VERSION 5.8 ;
BUSBITCHARS "[]" ;
DIVIDERCHAR "/" ;
UNITS
    DATABASE MICRONS 1000 ;
END UNITS

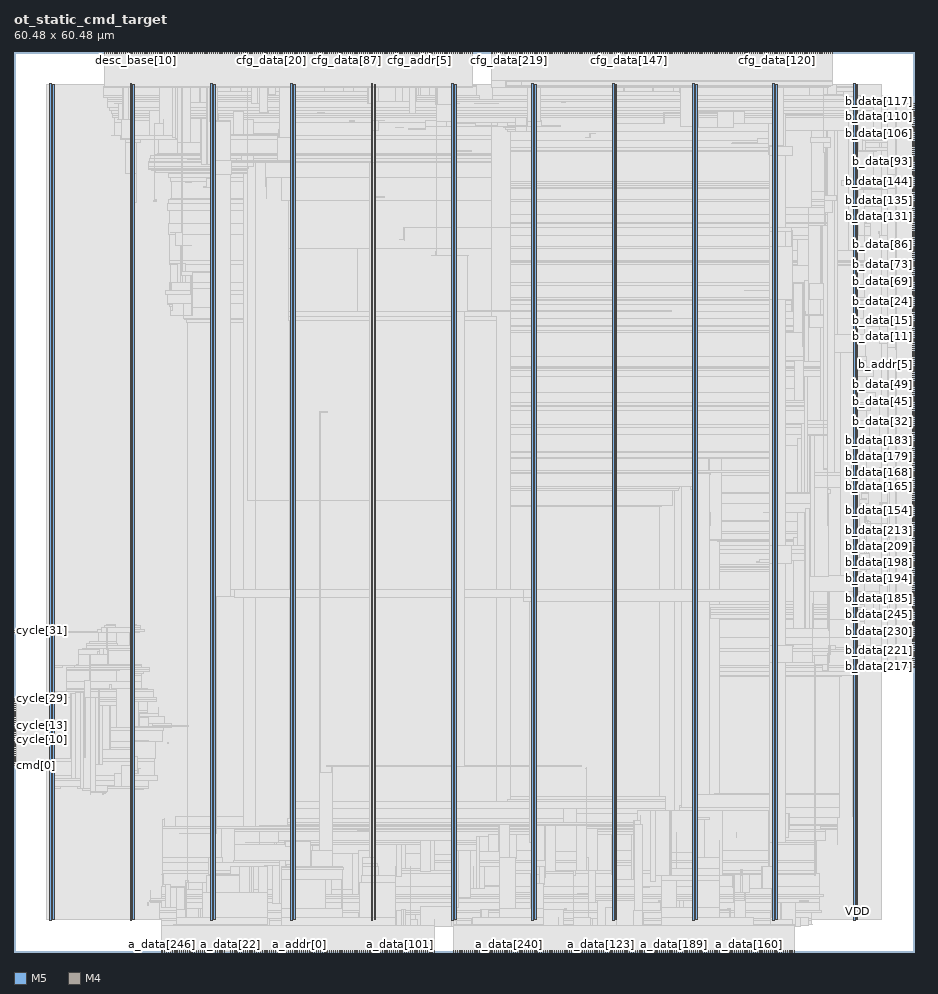
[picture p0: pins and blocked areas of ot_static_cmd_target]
MACRO ot_static_cmd_target
  FOREIGN ot_static_cmd_target 0 0 ;
  CLASS BLOCK ;
  SIZE 60.48 BY 60.48 ;
  PIN a_addr[0]
    DIRECTION OUTPUT ;
    USE SIGNAL ;
    PORT
      LAYER M5 ;
        RECT  19.152 0 19.176 0.084 ;
    END
  END a_addr[0]
  PIN a_addr[1]
    DIRECTION OUTPUT ;
    USE SIGNAL ;
    PORT
      LAYER M5 ;
        RECT  19.296 0 19.32 0.084 ;
    END
  END a_addr[1]
  PIN a_addr[2]
    DIRECTION OUTPUT ;
    USE SIGNAL ;
    PORT
      LAYER M5 ;
        RECT  19.44 0 19.464 0.084 ;
    END
  END a_addr[2]
  PIN a_addr[3]
    DIRECTION OUTPUT ;
    USE SIGNAL ;
    PORT
      LAYER M5 ;
        RECT  19.584 0 19.608 0.084 ;
    END
  END a_addr[3]
  PIN a_addr[4]
    DIRECTION OUTPUT ;
    USE SIGNAL ;
    PORT
      LAYER M5 ;
        RECT  19.728 0 19.752 0.084 ;
    END
  END a_addr[4]
  PIN a_addr[5]
    DIRECTION OUTPUT ;
    USE SIGNAL ;
    PORT
      LAYER M5 ;
        RECT  19.872 0 19.896 0.084 ;
    END
  END a_addr[5]
  PIN a_addr[6]
    DIRECTION OUTPUT ;
    USE SIGNAL ;
    PORT
      LAYER M5 ;
        RECT  20.016 0 20.04 0.084 ;
    END
  END a_addr[6]
  PIN a_addr[7]
    DIRECTION OUTPUT ;
    USE SIGNAL ;
    PORT
      LAYER M5 ;
        RECT  20.16 0 20.184 0.084 ;
    END
  END a_addr[7]
  PIN a_addr[8]
    DIRECTION OUTPUT ;
    USE SIGNAL ;
    PORT
      LAYER M5 ;
        RECT  20.304 0 20.328 0.084 ;
    END
  END a_addr[8]
  PIN a_addr[9]
    DIRECTION OUTPUT ;
    USE SIGNAL ;
    PORT
      LAYER M5 ;
        RECT  20.448 0 20.472 0.084 ;
    END
  END a_addr[9]
  PIN a_data[0]
    DIRECTION OUTPUT ;
    USE SIGNAL ;
    PORT
      LAYER M5 ;
        RECT  20.592 0 20.616 0.084 ;
    END
  END a_data[0]
  PIN a_data[100]
    DIRECTION OUTPUT ;
    USE SIGNAL ;
    PORT
      LAYER M5 ;
        RECT  25.776 0 25.8 0.084 ;
    END
  END a_data[100]
  PIN a_data[101]
    DIRECTION OUTPUT ;
    USE SIGNAL ;
    PORT
      LAYER M5 ;
        RECT  25.92 0 25.944 0.084 ;
    END
  END a_data[101]
  PIN a_data[102]
    DIRECTION OUTPUT ;
    USE SIGNAL ;
    PORT
      LAYER M5 ;
        RECT  26.064 0 26.088 0.084 ;
    END
  END a_data[102]
  PIN a_data[103]
    DIRECTION OUTPUT ;
    USE SIGNAL ;
    PORT
      LAYER M5 ;
        RECT  26.208 0 26.232 0.084 ;
    END
  END a_data[103]
  PIN a_data[104]
    DIRECTION OUTPUT ;
    USE SIGNAL ;
    PORT
      LAYER M5 ;
        RECT  26.352 0 26.376 0.084 ;
    END
  END a_data[104]
  PIN a_data[105]
    DIRECTION OUTPUT ;
    USE SIGNAL ;
    PORT
      LAYER M5 ;
        RECT  26.496 0 26.52 0.084 ;
    END
  END a_data[105]
  PIN a_data[106]
    DIRECTION OUTPUT ;
    USE SIGNAL ;
    PORT
      LAYER M5 ;
        RECT  26.64 0 26.664 0.084 ;
    END
  END a_data[106]
  PIN a_data[107]
    DIRECTION OUTPUT ;
    USE SIGNAL ;
    PORT
      LAYER M5 ;
        RECT  26.784 0 26.808 0.084 ;
    END
  END a_data[107]
  PIN a_data[108]
    DIRECTION OUTPUT ;
    USE SIGNAL ;
    PORT
      LAYER M5 ;
        RECT  26.928 0 26.952 0.084 ;
    END
  END a_data[108]
  PIN a_data[109]
    DIRECTION OUTPUT ;
    USE SIGNAL ;
    PORT
      LAYER M5 ;
        RECT  27.072 0 27.096 0.084 ;
    END
  END a_data[109]
  PIN a_data[10]
    DIRECTION OUTPUT ;
    USE SIGNAL ;
    PORT
      LAYER M5 ;
        RECT  22.032 0 22.056 0.084 ;
    END
  END a_data[10]
  PIN a_data[110]
    DIRECTION OUTPUT ;
    USE SIGNAL ;
    PORT
      LAYER M5 ;
        RECT  27.216 0 27.24 0.084 ;
    END
  END a_data[110]
  PIN a_data[111]
    DIRECTION OUTPUT ;
    USE SIGNAL ;
    PORT
      LAYER M5 ;
        RECT  27.36 0 27.384 0.084 ;
    END
  END a_data[111]
  PIN a_data[112]
    DIRECTION OUTPUT ;
    USE SIGNAL ;
    PORT
      LAYER M5 ;
        RECT  27.504 0 27.528 0.084 ;
    END
  END a_data[112]
  PIN a_data[113]
    DIRECTION OUTPUT ;
    USE SIGNAL ;
    PORT
      LAYER M5 ;
        RECT  27.648 0 27.672 0.084 ;
    END
  END a_data[113]
  PIN a_data[114]
    DIRECTION OUTPUT ;
    USE SIGNAL ;
    PORT
      LAYER M5 ;
        RECT  27.792 0 27.816 0.084 ;
    END
  END a_data[114]
  PIN a_data[115]
    DIRECTION OUTPUT ;
    USE SIGNAL ;
    PORT
      LAYER M5 ;
        RECT  27.936 0 27.96 0.084 ;
    END
  END a_data[115]
  PIN a_data[116]
    DIRECTION OUTPUT ;
    USE SIGNAL ;
    PORT
      LAYER M5 ;
        RECT  28.08 0 28.104 0.084 ;
    END
  END a_data[116]
  PIN a_data[117]
    DIRECTION OUTPUT ;
    USE SIGNAL ;
    PORT
      LAYER M5 ;
        RECT  28.224 0 28.248 0.084 ;
    END
  END a_data[117]
  PIN a_data[118]
    DIRECTION OUTPUT ;
    USE SIGNAL ;
    PORT
      LAYER M5 ;
        RECT  38.736 0 38.76 0.084 ;
    END
  END a_data[118]
  PIN a_data[119]
    DIRECTION OUTPUT ;
    USE SIGNAL ;
    PORT
      LAYER M5 ;
        RECT  38.88 0 38.904 0.084 ;
    END
  END a_data[119]
  PIN a_data[11]
    DIRECTION OUTPUT ;
    USE SIGNAL ;
    PORT
      LAYER M5 ;
        RECT  22.176 0 22.2 0.084 ;
    END
  END a_data[11]
  PIN a_data[120]
    DIRECTION OUTPUT ;
    USE SIGNAL ;
    PORT
      LAYER M5 ;
        RECT  39.024 0 39.048 0.084 ;
    END
  END a_data[120]
  PIN a_data[121]
    DIRECTION OUTPUT ;
    USE SIGNAL ;
    PORT
      LAYER M5 ;
        RECT  39.168 0 39.192 0.084 ;
    END
  END a_data[121]
  PIN a_data[122]
    DIRECTION OUTPUT ;
    USE SIGNAL ;
    PORT
      LAYER M5 ;
        RECT  39.312 0 39.336 0.084 ;
    END
  END a_data[122]
  PIN a_data[123]
    DIRECTION OUTPUT ;
    USE SIGNAL ;
    PORT
      LAYER M5 ;
        RECT  39.456 0 39.48 0.084 ;
    END
  END a_data[123]
  PIN a_data[124]
    DIRECTION OUTPUT ;
    USE SIGNAL ;
    PORT
      LAYER M5 ;
        RECT  39.6 0 39.624 0.084 ;
    END
  END a_data[124]
  PIN a_data[125]
    DIRECTION OUTPUT ;
    USE SIGNAL ;
    PORT
      LAYER M5 ;
        RECT  39.744 0 39.768 0.084 ;
    END
  END a_data[125]
  PIN a_data[126]
    DIRECTION OUTPUT ;
    USE SIGNAL ;
    PORT
      LAYER M5 ;
        RECT  39.888 0 39.912 0.084 ;
    END
  END a_data[126]
  PIN a_data[127]
    DIRECTION OUTPUT ;
    USE SIGNAL ;
    PORT
      LAYER M5 ;
        RECT  40.032 0 40.056 0.084 ;
    END
  END a_data[127]
  PIN a_data[128]
    DIRECTION OUTPUT ;
    USE SIGNAL ;
    PORT
      LAYER M5 ;
        RECT  40.176 0 40.2 0.084 ;
    END
  END a_data[128]
  PIN a_data[129]
    DIRECTION OUTPUT ;
    USE SIGNAL ;
    PORT
      LAYER M5 ;
        RECT  40.32 0 40.344 0.084 ;
    END
  END a_data[129]
  PIN a_data[12]
    DIRECTION OUTPUT ;
    USE SIGNAL ;
    PORT
      LAYER M5 ;
        RECT  22.32 0 22.344 0.084 ;
    END
  END a_data[12]
  PIN a_data[130]
    DIRECTION OUTPUT ;
    USE SIGNAL ;
    PORT
      LAYER M5 ;
        RECT  40.464 0 40.488 0.084 ;
    END
  END a_data[130]
  PIN a_data[131]
    DIRECTION OUTPUT ;
    USE SIGNAL ;
    PORT
      LAYER M5 ;
        RECT  40.608 0 40.632 0.084 ;
    END
  END a_data[131]
  PIN a_data[132]
    DIRECTION OUTPUT ;
    USE SIGNAL ;
    PORT
      LAYER M5 ;
        RECT  40.752 0 40.776 0.084 ;
    END
  END a_data[132]
  PIN a_data[133]
    DIRECTION OUTPUT ;
    USE SIGNAL ;
    PORT
      LAYER M5 ;
        RECT  40.896 0 40.92 0.084 ;
    END
  END a_data[133]
  PIN a_data[134]
    DIRECTION OUTPUT ;
    USE SIGNAL ;
    PORT
      LAYER M5 ;
        RECT  41.04 0 41.064 0.084 ;
    END
  END a_data[134]
  PIN a_data[135]
    DIRECTION OUTPUT ;
    USE SIGNAL ;
    PORT
      LAYER M5 ;
        RECT  41.184 0 41.208 0.084 ;
    END
  END a_data[135]
  PIN a_data[136]
    DIRECTION OUTPUT ;
    USE SIGNAL ;
    PORT
      LAYER M5 ;
        RECT  41.328 0 41.352 0.084 ;
    END
  END a_data[136]
  PIN a_data[137]
    DIRECTION OUTPUT ;
    USE SIGNAL ;
    PORT
      LAYER M5 ;
        RECT  41.472 0 41.496 0.084 ;
    END
  END a_data[137]
  PIN a_data[138]
    DIRECTION OUTPUT ;
    USE SIGNAL ;
    PORT
      LAYER M5 ;
        RECT  41.616 0 41.64 0.084 ;
    END
  END a_data[138]
  PIN a_data[139]
    DIRECTION OUTPUT ;
    USE SIGNAL ;
    PORT
      LAYER M5 ;
        RECT  41.76 0 41.784 0.084 ;
    END
  END a_data[139]
  PIN a_data[13]
    DIRECTION OUTPUT ;
    USE SIGNAL ;
    PORT
      LAYER M5 ;
        RECT  22.464 0 22.488 0.084 ;
    END
  END a_data[13]
  PIN a_data[140]
    DIRECTION OUTPUT ;
    USE SIGNAL ;
    PORT
      LAYER M5 ;
        RECT  41.904 0 41.928 0.084 ;
    END
  END a_data[140]
  PIN a_data[141]
    DIRECTION OUTPUT ;
    USE SIGNAL ;
    PORT
      LAYER M5 ;
        RECT  42.048 0 42.072 0.084 ;
    END
  END a_data[141]
  PIN a_data[142]
    DIRECTION OUTPUT ;
    USE SIGNAL ;
    PORT
      LAYER M5 ;
        RECT  42.192 0 42.216 0.084 ;
    END
  END a_data[142]
  PIN a_data[143]
    DIRECTION OUTPUT ;
    USE SIGNAL ;
    PORT
      LAYER M5 ;
        RECT  42.336 0 42.36 0.084 ;
    END
  END a_data[143]
  PIN a_data[144]
    DIRECTION OUTPUT ;
    USE SIGNAL ;
    PORT
      LAYER M5 ;
        RECT  42.48 0 42.504 0.084 ;
    END
  END a_data[144]
  PIN a_data[145]
    DIRECTION OUTPUT ;
    USE SIGNAL ;
    PORT
      LAYER M5 ;
        RECT  42.624 0 42.648 0.084 ;
    END
  END a_data[145]
  PIN a_data[146]
    DIRECTION OUTPUT ;
    USE SIGNAL ;
    PORT
      LAYER M5 ;
        RECT  42.768 0 42.792 0.084 ;
    END
  END a_data[146]
  PIN a_data[147]
    DIRECTION OUTPUT ;
    USE SIGNAL ;
    PORT
      LAYER M5 ;
        RECT  42.912 0 42.936 0.084 ;
    END
  END a_data[147]
  PIN a_data[148]
    DIRECTION OUTPUT ;
    USE SIGNAL ;
    PORT
      LAYER M5 ;
        RECT  43.056 0 43.08 0.084 ;
    END
  END a_data[148]
  PIN a_data[149]
    DIRECTION OUTPUT ;
    USE SIGNAL ;
    PORT
      LAYER M5 ;
        RECT  43.2 0 43.224 0.084 ;
    END
  END a_data[149]
  PIN a_data[14]
    DIRECTION OUTPUT ;
    USE SIGNAL ;
    PORT
      LAYER M5 ;
        RECT  22.608 0 22.632 0.084 ;
    END
  END a_data[14]
  PIN a_data[150]
    DIRECTION OUTPUT ;
    USE SIGNAL ;
    PORT
      LAYER M5 ;
        RECT  47.952 0 47.976 0.084 ;
    END
  END a_data[150]
  PIN a_data[151]
    DIRECTION OUTPUT ;
    USE SIGNAL ;
    PORT
      LAYER M5 ;
        RECT  48.096 0 48.12 0.084 ;
    END
  END a_data[151]
  PIN a_data[152]
    DIRECTION OUTPUT ;
    USE SIGNAL ;
    PORT
      LAYER M5 ;
        RECT  48.24 0 48.264 0.084 ;
    END
  END a_data[152]
  PIN a_data[153]
    DIRECTION OUTPUT ;
    USE SIGNAL ;
    PORT
      LAYER M5 ;
        RECT  48.384 0 48.408 0.084 ;
    END
  END a_data[153]
  PIN a_data[154]
    DIRECTION OUTPUT ;
    USE SIGNAL ;
    PORT
      LAYER M5 ;
        RECT  48.528 0 48.552 0.084 ;
    END
  END a_data[154]
  PIN a_data[155]
    DIRECTION OUTPUT ;
    USE SIGNAL ;
    PORT
      LAYER M5 ;
        RECT  48.672 0 48.696 0.084 ;
    END
  END a_data[155]
  PIN a_data[156]
    DIRECTION OUTPUT ;
    USE SIGNAL ;
    PORT
      LAYER M5 ;
        RECT  48.816 0 48.84 0.084 ;
    END
  END a_data[156]
  PIN a_data[157]
    DIRECTION OUTPUT ;
    USE SIGNAL ;
    PORT
      LAYER M5 ;
        RECT  48.96 0 48.984 0.084 ;
    END
  END a_data[157]
  PIN a_data[158]
    DIRECTION OUTPUT ;
    USE SIGNAL ;
    PORT
      LAYER M5 ;
        RECT  49.104 0 49.128 0.084 ;
    END
  END a_data[158]
  PIN a_data[159]
    DIRECTION OUTPUT ;
    USE SIGNAL ;
    PORT
      LAYER M5 ;
        RECT  49.248 0 49.272 0.084 ;
    END
  END a_data[159]
  PIN a_data[15]
    DIRECTION OUTPUT ;
    USE SIGNAL ;
    PORT
      LAYER M5 ;
        RECT  22.752 0 22.776 0.084 ;
    END
  END a_data[15]
  PIN a_data[160]
    DIRECTION OUTPUT ;
    USE SIGNAL ;
    PORT
      LAYER M5 ;
        RECT  49.392 0 49.416 0.084 ;
    END
  END a_data[160]
  PIN a_data[161]
    DIRECTION OUTPUT ;
    USE SIGNAL ;
    PORT
      LAYER M5 ;
        RECT  49.536 0 49.56 0.084 ;
    END
  END a_data[161]
  PIN a_data[162]
    DIRECTION OUTPUT ;
    USE SIGNAL ;
    PORT
      LAYER M5 ;
        RECT  49.68 0 49.704 0.084 ;
    END
  END a_data[162]
  PIN a_data[163]
    DIRECTION OUTPUT ;
    USE SIGNAL ;
    PORT
      LAYER M5 ;
        RECT  49.824 0 49.848 0.084 ;
    END
  END a_data[163]
  PIN a_data[164]
    DIRECTION OUTPUT ;
    USE SIGNAL ;
    PORT
      LAYER M5 ;
        RECT  49.968 0 49.992 0.084 ;
    END
  END a_data[164]
  PIN a_data[165]
    DIRECTION OUTPUT ;
    USE SIGNAL ;
    PORT
      LAYER M5 ;
        RECT  50.112 0 50.136 0.084 ;
    END
  END a_data[165]
  PIN a_data[166]
    DIRECTION OUTPUT ;
    USE SIGNAL ;
    PORT
      LAYER M5 ;
        RECT  50.256 0 50.28 0.084 ;
    END
  END a_data[166]
  PIN a_data[167]
    DIRECTION OUTPUT ;
    USE SIGNAL ;
    PORT
      LAYER M5 ;
        RECT  50.4 0 50.424 0.084 ;
    END
  END a_data[167]
  PIN a_data[168]
    DIRECTION OUTPUT ;
    USE SIGNAL ;
    PORT
      LAYER M5 ;
        RECT  50.544 0 50.568 0.084 ;
    END
  END a_data[168]
  PIN a_data[169]
    DIRECTION OUTPUT ;
    USE SIGNAL ;
    PORT
      LAYER M5 ;
        RECT  50.688 0 50.712 0.084 ;
    END
  END a_data[169]
  PIN a_data[16]
    DIRECTION OUTPUT ;
    USE SIGNAL ;
    PORT
      LAYER M5 ;
        RECT  22.896 0 22.92 0.084 ;
    END
  END a_data[16]
  PIN a_data[170]
    DIRECTION OUTPUT ;
    USE SIGNAL ;
    PORT
      LAYER M5 ;
        RECT  50.832 0 50.856 0.084 ;
    END
  END a_data[170]
  PIN a_data[171]
    DIRECTION OUTPUT ;
    USE SIGNAL ;
    PORT
      LAYER M5 ;
        RECT  50.976 0 51 0.084 ;
    END
  END a_data[171]
  PIN a_data[172]
    DIRECTION OUTPUT ;
    USE SIGNAL ;
    PORT
      LAYER M5 ;
        RECT  51.12 0 51.144 0.084 ;
    END
  END a_data[172]
  PIN a_data[173]
    DIRECTION OUTPUT ;
    USE SIGNAL ;
    PORT
      LAYER M5 ;
        RECT  51.264 0 51.288 0.084 ;
    END
  END a_data[173]
  PIN a_data[174]
    DIRECTION OUTPUT ;
    USE SIGNAL ;
    PORT
      LAYER M5 ;
        RECT  51.408 0 51.432 0.084 ;
    END
  END a_data[174]
  PIN a_data[175]
    DIRECTION OUTPUT ;
    USE SIGNAL ;
    PORT
      LAYER M5 ;
        RECT  51.552 0 51.576 0.084 ;
    END
  END a_data[175]
  PIN a_data[176]
    DIRECTION OUTPUT ;
    USE SIGNAL ;
    PORT
      LAYER M5 ;
        RECT  51.696 0 51.72 0.084 ;
    END
  END a_data[176]
  PIN a_data[177]
    DIRECTION OUTPUT ;
    USE SIGNAL ;
    PORT
      LAYER M5 ;
        RECT  51.84 0 51.864 0.084 ;
    END
  END a_data[177]
  PIN a_data[178]
    DIRECTION OUTPUT ;
    USE SIGNAL ;
    PORT
      LAYER M5 ;
        RECT  51.984 0 52.008 0.084 ;
    END
  END a_data[178]
  PIN a_data[179]
    DIRECTION OUTPUT ;
    USE SIGNAL ;
    PORT
      LAYER M5 ;
        RECT  52.128 0 52.152 0.084 ;
    END
  END a_data[179]
  PIN a_data[17]
    DIRECTION OUTPUT ;
    USE SIGNAL ;
    PORT
      LAYER M5 ;
        RECT  23.04 0 23.064 0.084 ;
    END
  END a_data[17]
  PIN a_data[180]
    DIRECTION OUTPUT ;
    USE SIGNAL ;
    PORT
      LAYER M5 ;
        RECT  52.272 0 52.296 0.084 ;
    END
  END a_data[180]
  PIN a_data[181]
    DIRECTION OUTPUT ;
    USE SIGNAL ;
    PORT
      LAYER M5 ;
        RECT  52.416 0 52.44 0.084 ;
    END
  END a_data[181]
  PIN a_data[182]
    DIRECTION OUTPUT ;
    USE SIGNAL ;
    PORT
      LAYER M5 ;
        RECT  43.344 0 43.368 0.084 ;
    END
  END a_data[182]
  PIN a_data[183]
    DIRECTION OUTPUT ;
    USE SIGNAL ;
    PORT
      LAYER M5 ;
        RECT  43.488 0 43.512 0.084 ;
    END
  END a_data[183]
  PIN a_data[184]
    DIRECTION OUTPUT ;
    USE SIGNAL ;
    PORT
      LAYER M5 ;
        RECT  43.632 0 43.656 0.084 ;
    END
  END a_data[184]
  PIN a_data[185]
    DIRECTION OUTPUT ;
    USE SIGNAL ;
    PORT
      LAYER M5 ;
        RECT  43.776 0 43.8 0.084 ;
    END
  END a_data[185]
  PIN a_data[186]
    DIRECTION OUTPUT ;
    USE SIGNAL ;
    PORT
      LAYER M5 ;
        RECT  43.92 0 43.944 0.084 ;
    END
  END a_data[186]
  PIN a_data[187]
    DIRECTION OUTPUT ;
    USE SIGNAL ;
    PORT
      LAYER M5 ;
        RECT  44.064 0 44.088 0.084 ;
    END
  END a_data[187]
  PIN a_data[188]
    DIRECTION OUTPUT ;
    USE SIGNAL ;
    PORT
      LAYER M5 ;
        RECT  44.208 0 44.232 0.084 ;
    END
  END a_data[188]
  PIN a_data[189]
    DIRECTION OUTPUT ;
    USE SIGNAL ;
    PORT
      LAYER M5 ;
        RECT  44.352 0 44.376 0.084 ;
    END
  END a_data[189]
  PIN a_data[18]
    DIRECTION OUTPUT ;
    USE SIGNAL ;
    PORT
      LAYER M5 ;
        RECT  23.184 0 23.208 0.084 ;
    END
  END a_data[18]
  PIN a_data[190]
    DIRECTION OUTPUT ;
    USE SIGNAL ;
    PORT
      LAYER M5 ;
        RECT  44.496 0 44.52 0.084 ;
    END
  END a_data[190]
  PIN a_data[191]
    DIRECTION OUTPUT ;
    USE SIGNAL ;
    PORT
      LAYER M5 ;
        RECT  44.64 0 44.664 0.084 ;
    END
  END a_data[191]
  PIN a_data[192]
    DIRECTION OUTPUT ;
    USE SIGNAL ;
    PORT
      LAYER M5 ;
        RECT  44.784 0 44.808 0.084 ;
    END
  END a_data[192]
  PIN a_data[193]
    DIRECTION OUTPUT ;
    USE SIGNAL ;
    PORT
      LAYER M5 ;
        RECT  44.928 0 44.952 0.084 ;
    END
  END a_data[193]
  PIN a_data[194]
    DIRECTION OUTPUT ;
    USE SIGNAL ;
    PORT
      LAYER M5 ;
        RECT  45.072 0 45.096 0.084 ;
    END
  END a_data[194]
  PIN a_data[195]
    DIRECTION OUTPUT ;
    USE SIGNAL ;
    PORT
      LAYER M5 ;
        RECT  45.216 0 45.24 0.084 ;
    END
  END a_data[195]
  PIN a_data[196]
    DIRECTION OUTPUT ;
    USE SIGNAL ;
    PORT
      LAYER M5 ;
        RECT  45.36 0 45.384 0.084 ;
    END
  END a_data[196]
  PIN a_data[197]
    DIRECTION OUTPUT ;
    USE SIGNAL ;
    PORT
      LAYER M5 ;
        RECT  45.504 0 45.528 0.084 ;
    END
  END a_data[197]
  PIN a_data[198]
    DIRECTION OUTPUT ;
    USE SIGNAL ;
    PORT
      LAYER M5 ;
        RECT  45.648 0 45.672 0.084 ;
    END
  END a_data[198]
  PIN a_data[199]
    DIRECTION OUTPUT ;
    USE SIGNAL ;
    PORT
      LAYER M5 ;
        RECT  45.792 0 45.816 0.084 ;
    END
  END a_data[199]
  PIN a_data[19]
    DIRECTION OUTPUT ;
    USE SIGNAL ;
    PORT
      LAYER M5 ;
        RECT  23.328 0 23.352 0.084 ;
    END
  END a_data[19]
  PIN a_data[1]
    DIRECTION OUTPUT ;
    USE SIGNAL ;
    PORT
      LAYER M5 ;
        RECT  20.736 0 20.76 0.084 ;
    END
  END a_data[1]
  PIN a_data[200]
    DIRECTION OUTPUT ;
    USE SIGNAL ;
    PORT
      LAYER M5 ;
        RECT  45.936 0 45.96 0.084 ;
    END
  END a_data[200]
  PIN a_data[201]
    DIRECTION OUTPUT ;
    USE SIGNAL ;
    PORT
      LAYER M5 ;
        RECT  46.08 0 46.104 0.084 ;
    END
  END a_data[201]
  PIN a_data[202]
    DIRECTION OUTPUT ;
    USE SIGNAL ;
    PORT
      LAYER M5 ;
        RECT  46.224 0 46.248 0.084 ;
    END
  END a_data[202]
  PIN a_data[203]
    DIRECTION OUTPUT ;
    USE SIGNAL ;
    PORT
      LAYER M5 ;
        RECT  46.368 0 46.392 0.084 ;
    END
  END a_data[203]
  PIN a_data[204]
    DIRECTION OUTPUT ;
    USE SIGNAL ;
    PORT
      LAYER M5 ;
        RECT  46.512 0 46.536 0.084 ;
    END
  END a_data[204]
  PIN a_data[205]
    DIRECTION OUTPUT ;
    USE SIGNAL ;
    PORT
      LAYER M5 ;
        RECT  46.656 0 46.68 0.084 ;
    END
  END a_data[205]
  PIN a_data[206]
    DIRECTION OUTPUT ;
    USE SIGNAL ;
    PORT
      LAYER M5 ;
        RECT  46.8 0 46.824 0.084 ;
    END
  END a_data[206]
  PIN a_data[207]
    DIRECTION OUTPUT ;
    USE SIGNAL ;
    PORT
      LAYER M5 ;
        RECT  46.944 0 46.968 0.084 ;
    END
  END a_data[207]
  PIN a_data[208]
    DIRECTION OUTPUT ;
    USE SIGNAL ;
    PORT
      LAYER M5 ;
        RECT  47.088 0 47.112 0.084 ;
    END
  END a_data[208]
  PIN a_data[209]
    DIRECTION OUTPUT ;
    USE SIGNAL ;
    PORT
      LAYER M5 ;
        RECT  47.232 0 47.256 0.084 ;
    END
  END a_data[209]
  PIN a_data[20]
    DIRECTION OUTPUT ;
    USE SIGNAL ;
    PORT
      LAYER M5 ;
        RECT  23.472 0 23.496 0.084 ;
    END
  END a_data[20]
  PIN a_data[210]
    DIRECTION OUTPUT ;
    USE SIGNAL ;
    PORT
      LAYER M5 ;
        RECT  47.376 0 47.4 0.084 ;
    END
  END a_data[210]
  PIN a_data[211]
    DIRECTION OUTPUT ;
    USE SIGNAL ;
    PORT
      LAYER M5 ;
        RECT  47.52 0 47.544 0.084 ;
    END
  END a_data[211]
  PIN a_data[212]
    DIRECTION OUTPUT ;
    USE SIGNAL ;
    PORT
      LAYER M5 ;
        RECT  47.664 0 47.688 0.084 ;
    END
  END a_data[212]
  PIN a_data[213]
    DIRECTION OUTPUT ;
    USE SIGNAL ;
    PORT
      LAYER M5 ;
        RECT  47.808 0 47.832 0.084 ;
    END
  END a_data[213]
  PIN a_data[214]
    DIRECTION OUTPUT ;
    USE SIGNAL ;
    PORT
      LAYER M5 ;
        RECT  29.52 0 29.544 0.084 ;
    END
  END a_data[214]
  PIN a_data[215]
    DIRECTION OUTPUT ;
    USE SIGNAL ;
    PORT
      LAYER M5 ;
        RECT  29.664 0 29.688 0.084 ;
    END
  END a_data[215]
  PIN a_data[216]
    DIRECTION OUTPUT ;
    USE SIGNAL ;
    PORT
      LAYER M5 ;
        RECT  29.808 0 29.832 0.084 ;
    END
  END a_data[216]
  PIN a_data[217]
    DIRECTION OUTPUT ;
    USE SIGNAL ;
    PORT
      LAYER M5 ;
        RECT  29.952 0 29.976 0.084 ;
    END
  END a_data[217]
  PIN a_data[218]
    DIRECTION OUTPUT ;
    USE SIGNAL ;
    PORT
      LAYER M5 ;
        RECT  30.096 0 30.12 0.084 ;
    END
  END a_data[218]
  PIN a_data[219]
    DIRECTION OUTPUT ;
    USE SIGNAL ;
    PORT
      LAYER M5 ;
        RECT  30.24 0 30.264 0.084 ;
    END
  END a_data[219]
  PIN a_data[21]
    DIRECTION OUTPUT ;
    USE SIGNAL ;
    PORT
      LAYER M5 ;
        RECT  23.616 0 23.64 0.084 ;
    END
  END a_data[21]
  PIN a_data[220]
    DIRECTION OUTPUT ;
    USE SIGNAL ;
    PORT
      LAYER M5 ;
        RECT  30.384 0 30.408 0.084 ;
    END
  END a_data[220]
  PIN a_data[221]
    DIRECTION OUTPUT ;
    USE SIGNAL ;
    PORT
      LAYER M5 ;
        RECT  30.528 0 30.552 0.084 ;
    END
  END a_data[221]
  PIN a_data[222]
    DIRECTION OUTPUT ;
    USE SIGNAL ;
    PORT
      LAYER M5 ;
        RECT  30.672 0 30.696 0.084 ;
    END
  END a_data[222]
  PIN a_data[223]
    DIRECTION OUTPUT ;
    USE SIGNAL ;
    PORT
      LAYER M5 ;
        RECT  30.816 0 30.84 0.084 ;
    END
  END a_data[223]
  PIN a_data[224]
    DIRECTION OUTPUT ;
    USE SIGNAL ;
    PORT
      LAYER M5 ;
        RECT  30.96 0 30.984 0.084 ;
    END
  END a_data[224]
  PIN a_data[225]
    DIRECTION OUTPUT ;
    USE SIGNAL ;
    PORT
      LAYER M5 ;
        RECT  31.104 0 31.128 0.084 ;
    END
  END a_data[225]
  PIN a_data[226]
    DIRECTION OUTPUT ;
    USE SIGNAL ;
    PORT
      LAYER M5 ;
        RECT  31.248 0 31.272 0.084 ;
    END
  END a_data[226]
  PIN a_data[227]
    DIRECTION OUTPUT ;
    USE SIGNAL ;
    PORT
      LAYER M5 ;
        RECT  31.392 0 31.416 0.084 ;
    END
  END a_data[227]
  PIN a_data[228]
    DIRECTION OUTPUT ;
    USE SIGNAL ;
    PORT
      LAYER M5 ;
        RECT  31.536 0 31.56 0.084 ;
    END
  END a_data[228]
  PIN a_data[229]
    DIRECTION OUTPUT ;
    USE SIGNAL ;
    PORT
      LAYER M5 ;
        RECT  31.68 0 31.704 0.084 ;
    END
  END a_data[229]
  PIN a_data[22]
    DIRECTION OUTPUT ;
    USE SIGNAL ;
    PORT
      LAYER M5 ;
        RECT  14.544 0 14.568 0.084 ;
    END
  END a_data[22]
  PIN a_data[230]
    DIRECTION OUTPUT ;
    USE SIGNAL ;
    PORT
      LAYER M5 ;
        RECT  31.824 0 31.848 0.084 ;
    END
  END a_data[230]
  PIN a_data[231]
    DIRECTION OUTPUT ;
    USE SIGNAL ;
    PORT
      LAYER M5 ;
        RECT  31.968 0 31.992 0.084 ;
    END
  END a_data[231]
  PIN a_data[232]
    DIRECTION OUTPUT ;
    USE SIGNAL ;
    PORT
      LAYER M5 ;
        RECT  32.112 0 32.136 0.084 ;
    END
  END a_data[232]
  PIN a_data[233]
    DIRECTION OUTPUT ;
    USE SIGNAL ;
    PORT
      LAYER M5 ;
        RECT  32.256 0 32.28 0.084 ;
    END
  END a_data[233]
  PIN a_data[234]
    DIRECTION OUTPUT ;
    USE SIGNAL ;
    PORT
      LAYER M5 ;
        RECT  32.4 0 32.424 0.084 ;
    END
  END a_data[234]
  PIN a_data[235]
    DIRECTION OUTPUT ;
    USE SIGNAL ;
    PORT
      LAYER M5 ;
        RECT  32.544 0 32.568 0.084 ;
    END
  END a_data[235]
  PIN a_data[236]
    DIRECTION OUTPUT ;
    USE SIGNAL ;
    PORT
      LAYER M5 ;
        RECT  32.688 0 32.712 0.084 ;
    END
  END a_data[236]
  PIN a_data[237]
    DIRECTION OUTPUT ;
    USE SIGNAL ;
    PORT
      LAYER M5 ;
        RECT  32.832 0 32.856 0.084 ;
    END
  END a_data[237]
  PIN a_data[238]
    DIRECTION OUTPUT ;
    USE SIGNAL ;
    PORT
      LAYER M5 ;
        RECT  32.976 0 33 0.084 ;
    END
  END a_data[238]
  PIN a_data[239]
    DIRECTION OUTPUT ;
    USE SIGNAL ;
    PORT
      LAYER M5 ;
        RECT  33.12 0 33.144 0.084 ;
    END
  END a_data[239]
  PIN a_data[23]
    DIRECTION OUTPUT ;
    USE SIGNAL ;
    PORT
      LAYER M5 ;
        RECT  14.688 0 14.712 0.084 ;
    END
  END a_data[23]
  PIN a_data[240]
    DIRECTION OUTPUT ;
    USE SIGNAL ;
    PORT
      LAYER M5 ;
        RECT  33.264 0 33.288 0.084 ;
    END
  END a_data[240]
  PIN a_data[241]
    DIRECTION OUTPUT ;
    USE SIGNAL ;
    PORT
      LAYER M5 ;
        RECT  33.408 0 33.432 0.084 ;
    END
  END a_data[241]
  PIN a_data[242]
    DIRECTION OUTPUT ;
    USE SIGNAL ;
    PORT
      LAYER M5 ;
        RECT  33.552 0 33.576 0.084 ;
    END
  END a_data[242]
  PIN a_data[243]
    DIRECTION OUTPUT ;
    USE SIGNAL ;
    PORT
      LAYER M5 ;
        RECT  33.696 0 33.72 0.084 ;
    END
  END a_data[243]
  PIN a_data[244]
    DIRECTION OUTPUT ;
    USE SIGNAL ;
    PORT
      LAYER M5 ;
        RECT  33.84 0 33.864 0.084 ;
    END
  END a_data[244]
  PIN a_data[245]
    DIRECTION OUTPUT ;
    USE SIGNAL ;
    PORT
      LAYER M5 ;
        RECT  33.984 0 34.008 0.084 ;
    END
  END a_data[245]
  PIN a_data[246]
    DIRECTION OUTPUT ;
    USE SIGNAL ;
    PORT
      LAYER M5 ;
        RECT  9.936 0 9.96 0.084 ;
    END
  END a_data[246]
  PIN a_data[247]
    DIRECTION OUTPUT ;
    USE SIGNAL ;
    PORT
      LAYER M5 ;
        RECT  10.08 0 10.104 0.084 ;
    END
  END a_data[247]
  PIN a_data[248]
    DIRECTION OUTPUT ;
    USE SIGNAL ;
    PORT
      LAYER M5 ;
        RECT  10.224 0 10.248 0.084 ;
    END
  END a_data[248]
  PIN a_data[249]
    DIRECTION OUTPUT ;
    USE SIGNAL ;
    PORT
      LAYER M5 ;
        RECT  10.368 0 10.392 0.084 ;
    END
  END a_data[249]
  PIN a_data[24]
    DIRECTION OUTPUT ;
    USE SIGNAL ;
    PORT
      LAYER M5 ;
        RECT  14.832 0 14.856 0.084 ;
    END
  END a_data[24]
  PIN a_data[250]
    DIRECTION OUTPUT ;
    USE SIGNAL ;
    PORT
      LAYER M5 ;
        RECT  10.512 0 10.536 0.084 ;
    END
  END a_data[250]
  PIN a_data[251]
    DIRECTION OUTPUT ;
    USE SIGNAL ;
    PORT
      LAYER M5 ;
        RECT  10.656 0 10.68 0.084 ;
    END
  END a_data[251]
  PIN a_data[252]
    DIRECTION OUTPUT ;
    USE SIGNAL ;
    PORT
      LAYER M5 ;
        RECT  10.8 0 10.824 0.084 ;
    END
  END a_data[252]
  PIN a_data[253]
    DIRECTION OUTPUT ;
    USE SIGNAL ;
    PORT
      LAYER M5 ;
        RECT  10.944 0 10.968 0.084 ;
    END
  END a_data[253]
  PIN a_data[254]
    DIRECTION OUTPUT ;
    USE SIGNAL ;
    PORT
      LAYER M5 ;
        RECT  11.088 0 11.112 0.084 ;
    END
  END a_data[254]
  PIN a_data[255]
    DIRECTION OUTPUT ;
    USE SIGNAL ;
    PORT
      LAYER M5 ;
        RECT  11.232 0 11.256 0.084 ;
    END
  END a_data[255]
  PIN a_data[25]
    DIRECTION OUTPUT ;
    USE SIGNAL ;
    PORT
      LAYER M5 ;
        RECT  14.976 0 15 0.084 ;
    END
  END a_data[25]
  PIN a_data[26]
    DIRECTION OUTPUT ;
    USE SIGNAL ;
    PORT
      LAYER M5 ;
        RECT  15.12 0 15.144 0.084 ;
    END
  END a_data[26]
  PIN a_data[27]
    DIRECTION OUTPUT ;
    USE SIGNAL ;
    PORT
      LAYER M5 ;
        RECT  15.264 0 15.288 0.084 ;
    END
  END a_data[27]
  PIN a_data[28]
    DIRECTION OUTPUT ;
    USE SIGNAL ;
    PORT
      LAYER M5 ;
        RECT  15.408 0 15.432 0.084 ;
    END
  END a_data[28]
  PIN a_data[29]
    DIRECTION OUTPUT ;
    USE SIGNAL ;
    PORT
      LAYER M5 ;
        RECT  15.552 0 15.576 0.084 ;
    END
  END a_data[29]
  PIN a_data[2]
    DIRECTION OUTPUT ;
    USE SIGNAL ;
    PORT
      LAYER M5 ;
        RECT  20.88 0 20.904 0.084 ;
    END
  END a_data[2]
  PIN a_data[30]
    DIRECTION OUTPUT ;
    USE SIGNAL ;
    PORT
      LAYER M5 ;
        RECT  15.696 0 15.72 0.084 ;
    END
  END a_data[30]
  PIN a_data[31]
    DIRECTION OUTPUT ;
    USE SIGNAL ;
    PORT
      LAYER M5 ;
        RECT  15.84 0 15.864 0.084 ;
    END
  END a_data[31]
  PIN a_data[32]
    DIRECTION OUTPUT ;
    USE SIGNAL ;
    PORT
      LAYER M5 ;
        RECT  15.984 0 16.008 0.084 ;
    END
  END a_data[32]
  PIN a_data[33]
    DIRECTION OUTPUT ;
    USE SIGNAL ;
    PORT
      LAYER M5 ;
        RECT  16.128 0 16.152 0.084 ;
    END
  END a_data[33]
  PIN a_data[34]
    DIRECTION OUTPUT ;
    USE SIGNAL ;
    PORT
      LAYER M5 ;
        RECT  16.272 0 16.296 0.084 ;
    END
  END a_data[34]
  PIN a_data[35]
    DIRECTION OUTPUT ;
    USE SIGNAL ;
    PORT
      LAYER M5 ;
        RECT  16.416 0 16.44 0.084 ;
    END
  END a_data[35]
  PIN a_data[36]
    DIRECTION OUTPUT ;
    USE SIGNAL ;
    PORT
      LAYER M5 ;
        RECT  16.56 0 16.584 0.084 ;
    END
  END a_data[36]
  PIN a_data[37]
    DIRECTION OUTPUT ;
    USE SIGNAL ;
    PORT
      LAYER M5 ;
        RECT  16.704 0 16.728 0.084 ;
    END
  END a_data[37]
  PIN a_data[38]
    DIRECTION OUTPUT ;
    USE SIGNAL ;
    PORT
      LAYER M5 ;
        RECT  16.848 0 16.872 0.084 ;
    END
  END a_data[38]
  PIN a_data[39]
    DIRECTION OUTPUT ;
    USE SIGNAL ;
    PORT
      LAYER M5 ;
        RECT  16.992 0 17.016 0.084 ;
    END
  END a_data[39]
  PIN a_data[3]
    DIRECTION OUTPUT ;
    USE SIGNAL ;
    PORT
      LAYER M5 ;
        RECT  21.024 0 21.048 0.084 ;
    END
  END a_data[3]
  PIN a_data[40]
    DIRECTION OUTPUT ;
    USE SIGNAL ;
    PORT
      LAYER M5 ;
        RECT  17.136 0 17.16 0.084 ;
    END
  END a_data[40]
  PIN a_data[41]
    DIRECTION OUTPUT ;
    USE SIGNAL ;
    PORT
      LAYER M5 ;
        RECT  17.28 0 17.304 0.084 ;
    END
  END a_data[41]
  PIN a_data[42]
    DIRECTION OUTPUT ;
    USE SIGNAL ;
    PORT
      LAYER M5 ;
        RECT  17.424 0 17.448 0.084 ;
    END
  END a_data[42]
  PIN a_data[43]
    DIRECTION OUTPUT ;
    USE SIGNAL ;
    PORT
      LAYER M5 ;
        RECT  17.568 0 17.592 0.084 ;
    END
  END a_data[43]
  PIN a_data[44]
    DIRECTION OUTPUT ;
    USE SIGNAL ;
    PORT
      LAYER M5 ;
        RECT  17.712 0 17.736 0.084 ;
    END
  END a_data[44]
  PIN a_data[45]
    DIRECTION OUTPUT ;
    USE SIGNAL ;
    PORT
      LAYER M5 ;
        RECT  17.856 0 17.88 0.084 ;
    END
  END a_data[45]
  PIN a_data[46]
    DIRECTION OUTPUT ;
    USE SIGNAL ;
    PORT
      LAYER M5 ;
        RECT  18 0 18.024 0.084 ;
    END
  END a_data[46]
  PIN a_data[47]
    DIRECTION OUTPUT ;
    USE SIGNAL ;
    PORT
      LAYER M5 ;
        RECT  18.144 0 18.168 0.084 ;
    END
  END a_data[47]
  PIN a_data[48]
    DIRECTION OUTPUT ;
    USE SIGNAL ;
    PORT
      LAYER M5 ;
        RECT  18.288 0 18.312 0.084 ;
    END
  END a_data[48]
  PIN a_data[49]
    DIRECTION OUTPUT ;
    USE SIGNAL ;
    PORT
      LAYER M5 ;
        RECT  18.432 0 18.456 0.084 ;
    END
  END a_data[49]
  PIN a_data[4]
    DIRECTION OUTPUT ;
    USE SIGNAL ;
    PORT
      LAYER M5 ;
        RECT  21.168 0 21.192 0.084 ;
    END
  END a_data[4]
  PIN a_data[50]
    DIRECTION OUTPUT ;
    USE SIGNAL ;
    PORT
      LAYER M5 ;
        RECT  18.576 0 18.6 0.084 ;
    END
  END a_data[50]
  PIN a_data[51]
    DIRECTION OUTPUT ;
    USE SIGNAL ;
    PORT
      LAYER M5 ;
        RECT  18.72 0 18.744 0.084 ;
    END
  END a_data[51]
  PIN a_data[52]
    DIRECTION OUTPUT ;
    USE SIGNAL ;
    PORT
      LAYER M5 ;
        RECT  18.864 0 18.888 0.084 ;
    END
  END a_data[52]
  PIN a_data[53]
    DIRECTION OUTPUT ;
    USE SIGNAL ;
    PORT
      LAYER M5 ;
        RECT  19.008 0 19.032 0.084 ;
    END
  END a_data[53]
  PIN a_data[54]
    DIRECTION OUTPUT ;
    USE SIGNAL ;
    PORT
      LAYER M5 ;
        RECT  34.128 0 34.152 0.084 ;
    END
  END a_data[54]
  PIN a_data[55]
    DIRECTION OUTPUT ;
    USE SIGNAL ;
    PORT
      LAYER M5 ;
        RECT  34.272 0 34.296 0.084 ;
    END
  END a_data[55]
  PIN a_data[56]
    DIRECTION OUTPUT ;
    USE SIGNAL ;
    PORT
      LAYER M5 ;
        RECT  34.416 0 34.44 0.084 ;
    END
  END a_data[56]
  PIN a_data[57]
    DIRECTION OUTPUT ;
    USE SIGNAL ;
    PORT
      LAYER M5 ;
        RECT  34.56 0 34.584 0.084 ;
    END
  END a_data[57]
  PIN a_data[58]
    DIRECTION OUTPUT ;
    USE SIGNAL ;
    PORT
      LAYER M5 ;
        RECT  34.704 0 34.728 0.084 ;
    END
  END a_data[58]
  PIN a_data[59]
    DIRECTION OUTPUT ;
    USE SIGNAL ;
    PORT
      LAYER M5 ;
        RECT  34.848 0 34.872 0.084 ;
    END
  END a_data[59]
  PIN a_data[5]
    DIRECTION OUTPUT ;
    USE SIGNAL ;
    PORT
      LAYER M5 ;
        RECT  21.312 0 21.336 0.084 ;
    END
  END a_data[5]
  PIN a_data[60]
    DIRECTION OUTPUT ;
    USE SIGNAL ;
    PORT
      LAYER M5 ;
        RECT  34.992 0 35.016 0.084 ;
    END
  END a_data[60]
  PIN a_data[61]
    DIRECTION OUTPUT ;
    USE SIGNAL ;
    PORT
      LAYER M5 ;
        RECT  35.136 0 35.16 0.084 ;
    END
  END a_data[61]
  PIN a_data[62]
    DIRECTION OUTPUT ;
    USE SIGNAL ;
    PORT
      LAYER M5 ;
        RECT  35.28 0 35.304 0.084 ;
    END
  END a_data[62]
  PIN a_data[63]
    DIRECTION OUTPUT ;
    USE SIGNAL ;
    PORT
      LAYER M5 ;
        RECT  35.424 0 35.448 0.084 ;
    END
  END a_data[63]
  PIN a_data[64]
    DIRECTION OUTPUT ;
    USE SIGNAL ;
    PORT
      LAYER M5 ;
        RECT  35.568 0 35.592 0.084 ;
    END
  END a_data[64]
  PIN a_data[65]
    DIRECTION OUTPUT ;
    USE SIGNAL ;
    PORT
      LAYER M5 ;
        RECT  35.712 0 35.736 0.084 ;
    END
  END a_data[65]
  PIN a_data[66]
    DIRECTION OUTPUT ;
    USE SIGNAL ;
    PORT
      LAYER M5 ;
        RECT  35.856 0 35.88 0.084 ;
    END
  END a_data[66]
  PIN a_data[67]
    DIRECTION OUTPUT ;
    USE SIGNAL ;
    PORT
      LAYER M5 ;
        RECT  36 0 36.024 0.084 ;
    END
  END a_data[67]
  PIN a_data[68]
    DIRECTION OUTPUT ;
    USE SIGNAL ;
    PORT
      LAYER M5 ;
        RECT  36.144 0 36.168 0.084 ;
    END
  END a_data[68]
  PIN a_data[69]
    DIRECTION OUTPUT ;
    USE SIGNAL ;
    PORT
      LAYER M5 ;
        RECT  36.288 0 36.312 0.084 ;
    END
  END a_data[69]
  PIN a_data[6]
    DIRECTION OUTPUT ;
    USE SIGNAL ;
    PORT
      LAYER M5 ;
        RECT  21.456 0 21.48 0.084 ;
    END
  END a_data[6]
  PIN a_data[70]
    DIRECTION OUTPUT ;
    USE SIGNAL ;
    PORT
      LAYER M5 ;
        RECT  36.432 0 36.456 0.084 ;
    END
  END a_data[70]
  PIN a_data[71]
    DIRECTION OUTPUT ;
    USE SIGNAL ;
    PORT
      LAYER M5 ;
        RECT  36.576 0 36.6 0.084 ;
    END
  END a_data[71]
  PIN a_data[72]
    DIRECTION OUTPUT ;
    USE SIGNAL ;
    PORT
      LAYER M5 ;
        RECT  36.72 0 36.744 0.084 ;
    END
  END a_data[72]
  PIN a_data[73]
    DIRECTION OUTPUT ;
    USE SIGNAL ;
    PORT
      LAYER M5 ;
        RECT  36.864 0 36.888 0.084 ;
    END
  END a_data[73]
  PIN a_data[74]
    DIRECTION OUTPUT ;
    USE SIGNAL ;
    PORT
      LAYER M5 ;
        RECT  37.008 0 37.032 0.084 ;
    END
  END a_data[74]
  PIN a_data[75]
    DIRECTION OUTPUT ;
    USE SIGNAL ;
    PORT
      LAYER M5 ;
        RECT  37.152 0 37.176 0.084 ;
    END
  END a_data[75]
  PIN a_data[76]
    DIRECTION OUTPUT ;
    USE SIGNAL ;
    PORT
      LAYER M5 ;
        RECT  37.296 0 37.32 0.084 ;
    END
  END a_data[76]
  PIN a_data[77]
    DIRECTION OUTPUT ;
    USE SIGNAL ;
    PORT
      LAYER M5 ;
        RECT  37.44 0 37.464 0.084 ;
    END
  END a_data[77]
  PIN a_data[78]
    DIRECTION OUTPUT ;
    USE SIGNAL ;
    PORT
      LAYER M5 ;
        RECT  37.584 0 37.608 0.084 ;
    END
  END a_data[78]
  PIN a_data[79]
    DIRECTION OUTPUT ;
    USE SIGNAL ;
    PORT
      LAYER M5 ;
        RECT  37.728 0 37.752 0.084 ;
    END
  END a_data[79]
  PIN a_data[7]
    DIRECTION OUTPUT ;
    USE SIGNAL ;
    PORT
      LAYER M5 ;
        RECT  21.6 0 21.624 0.084 ;
    END
  END a_data[7]
  PIN a_data[80]
    DIRECTION OUTPUT ;
    USE SIGNAL ;
    PORT
      LAYER M5 ;
        RECT  37.872 0 37.896 0.084 ;
    END
  END a_data[80]
  PIN a_data[81]
    DIRECTION OUTPUT ;
    USE SIGNAL ;
    PORT
      LAYER M5 ;
        RECT  38.016 0 38.04 0.084 ;
    END
  END a_data[81]
  PIN a_data[82]
    DIRECTION OUTPUT ;
    USE SIGNAL ;
    PORT
      LAYER M5 ;
        RECT  38.16 0 38.184 0.084 ;
    END
  END a_data[82]
  PIN a_data[83]
    DIRECTION OUTPUT ;
    USE SIGNAL ;
    PORT
      LAYER M5 ;
        RECT  38.304 0 38.328 0.084 ;
    END
  END a_data[83]
  PIN a_data[84]
    DIRECTION OUTPUT ;
    USE SIGNAL ;
    PORT
      LAYER M5 ;
        RECT  38.448 0 38.472 0.084 ;
    END
  END a_data[84]
  PIN a_data[85]
    DIRECTION OUTPUT ;
    USE SIGNAL ;
    PORT
      LAYER M5 ;
        RECT  38.592 0 38.616 0.084 ;
    END
  END a_data[85]
  PIN a_data[86]
    DIRECTION OUTPUT ;
    USE SIGNAL ;
    PORT
      LAYER M5 ;
        RECT  23.76 0 23.784 0.084 ;
    END
  END a_data[86]
  PIN a_data[87]
    DIRECTION OUTPUT ;
    USE SIGNAL ;
    PORT
      LAYER M5 ;
        RECT  23.904 0 23.928 0.084 ;
    END
  END a_data[87]
  PIN a_data[88]
    DIRECTION OUTPUT ;
    USE SIGNAL ;
    PORT
      LAYER M5 ;
        RECT  24.048 0 24.072 0.084 ;
    END
  END a_data[88]
  PIN a_data[89]
    DIRECTION OUTPUT ;
    USE SIGNAL ;
    PORT
      LAYER M5 ;
        RECT  24.192 0 24.216 0.084 ;
    END
  END a_data[89]
  PIN a_data[8]
    DIRECTION OUTPUT ;
    USE SIGNAL ;
    PORT
      LAYER M5 ;
        RECT  21.744 0 21.768 0.084 ;
    END
  END a_data[8]
  PIN a_data[90]
    DIRECTION OUTPUT ;
    USE SIGNAL ;
    PORT
      LAYER M5 ;
        RECT  24.336 0 24.36 0.084 ;
    END
  END a_data[90]
  PIN a_data[91]
    DIRECTION OUTPUT ;
    USE SIGNAL ;
    PORT
      LAYER M5 ;
        RECT  24.48 0 24.504 0.084 ;
    END
  END a_data[91]
  PIN a_data[92]
    DIRECTION OUTPUT ;
    USE SIGNAL ;
    PORT
      LAYER M5 ;
        RECT  24.624 0 24.648 0.084 ;
    END
  END a_data[92]
  PIN a_data[93]
    DIRECTION OUTPUT ;
    USE SIGNAL ;
    PORT
      LAYER M5 ;
        RECT  24.768 0 24.792 0.084 ;
    END
  END a_data[93]
  PIN a_data[94]
    DIRECTION OUTPUT ;
    USE SIGNAL ;
    PORT
      LAYER M5 ;
        RECT  24.912 0 24.936 0.084 ;
    END
  END a_data[94]
  PIN a_data[95]
    DIRECTION OUTPUT ;
    USE SIGNAL ;
    PORT
      LAYER M5 ;
        RECT  25.056 0 25.08 0.084 ;
    END
  END a_data[95]
  PIN a_data[96]
    DIRECTION OUTPUT ;
    USE SIGNAL ;
    PORT
      LAYER M5 ;
        RECT  25.2 0 25.224 0.084 ;
    END
  END a_data[96]
  PIN a_data[97]
    DIRECTION OUTPUT ;
    USE SIGNAL ;
    PORT
      LAYER M5 ;
        RECT  25.344 0 25.368 0.084 ;
    END
  END a_data[97]
  PIN a_data[98]
    DIRECTION OUTPUT ;
    USE SIGNAL ;
    PORT
      LAYER M5 ;
        RECT  25.488 0 25.512 0.084 ;
    END
  END a_data[98]
  PIN a_data[99]
    DIRECTION OUTPUT ;
    USE SIGNAL ;
    PORT
      LAYER M5 ;
        RECT  25.632 0 25.656 0.084 ;
    END
  END a_data[99]
  PIN a_data[9]
    DIRECTION OUTPUT ;
    USE SIGNAL ;
    PORT
      LAYER M5 ;
        RECT  21.888 0 21.912 0.084 ;
    END
  END a_data[9]
  PIN a_we
    DIRECTION OUTPUT ;
    USE SIGNAL ;
    PORT
      LAYER M5 ;
        RECT  11.376 0 11.4 0.084 ;
    END
  END a_we
  PIN active
    DIRECTION OUTPUT ;
    USE SIGNAL ;
    PORT
      LAYER M5 ;
        RECT  26.352 60.396 26.376 60.48 ;
    END
  END active
  PIN b_addr[0]
    DIRECTION OUTPUT ;
    USE SIGNAL ;
    PORT
      LAYER M4 ;
        RECT  60.396 38.736 60.48 38.76 ;
    END
  END b_addr[0]
  PIN b_addr[1]
    DIRECTION OUTPUT ;
    USE SIGNAL ;
    PORT
      LAYER M4 ;
        RECT  60.396 38.88 60.48 38.904 ;
    END
  END b_addr[1]
  PIN b_addr[2]
    DIRECTION OUTPUT ;
    USE SIGNAL ;
    PORT
      LAYER M4 ;
        RECT  60.396 39.024 60.48 39.048 ;
    END
  END b_addr[2]
  PIN b_addr[3]
    DIRECTION OUTPUT ;
    USE SIGNAL ;
    PORT
      LAYER M4 ;
        RECT  60.396 39.168 60.48 39.192 ;
    END
  END b_addr[3]
  PIN b_addr[4]
    DIRECTION OUTPUT ;
    USE SIGNAL ;
    PORT
      LAYER M4 ;
        RECT  60.396 39.312 60.48 39.336 ;
    END
  END b_addr[4]
  PIN b_addr[5]
    DIRECTION OUTPUT ;
    USE SIGNAL ;
    PORT
      LAYER M4 ;
        RECT  60.396 39.456 60.48 39.48 ;
    END
  END b_addr[5]
  PIN b_addr[6]
    DIRECTION OUTPUT ;
    USE SIGNAL ;
    PORT
      LAYER M4 ;
        RECT  60.396 39.6 60.48 39.624 ;
    END
  END b_addr[6]
  PIN b_data[0]
    DIRECTION OUTPUT ;
    USE SIGNAL ;
    PORT
      LAYER M4 ;
        RECT  60.396 39.744 60.48 39.768 ;
    END
  END b_data[0]
  PIN b_data[100]
    DIRECTION OUTPUT ;
    USE SIGNAL ;
    PORT
      LAYER M4 ;
        RECT  60.396 54.144 60.48 54.168 ;
    END
  END b_data[100]
  PIN b_data[101]
    DIRECTION OUTPUT ;
    USE SIGNAL ;
    PORT
      LAYER M4 ;
        RECT  60.396 54.288 60.48 54.312 ;
    END
  END b_data[101]
  PIN b_data[102]
    DIRECTION OUTPUT ;
    USE SIGNAL ;
    PORT
      LAYER M4 ;
        RECT  60.396 54.432 60.48 54.456 ;
    END
  END b_data[102]
  PIN b_data[103]
    DIRECTION OUTPUT ;
    USE SIGNAL ;
    PORT
      LAYER M4 ;
        RECT  60.396 54.576 60.48 54.6 ;
    END
  END b_data[103]
  PIN b_data[104]
    DIRECTION OUTPUT ;
    USE SIGNAL ;
    PORT
      LAYER M4 ;
        RECT  60.396 54.72 60.48 54.744 ;
    END
  END b_data[104]
  PIN b_data[105]
    DIRECTION OUTPUT ;
    USE SIGNAL ;
    PORT
      LAYER M4 ;
        RECT  60.396 54.864 60.48 54.888 ;
    END
  END b_data[105]
  PIN b_data[106]
    DIRECTION OUTPUT ;
    USE SIGNAL ;
    PORT
      LAYER M4 ;
        RECT  60.396 55.008 60.48 55.032 ;
    END
  END b_data[106]
  PIN b_data[107]
    DIRECTION OUTPUT ;
    USE SIGNAL ;
    PORT
      LAYER M4 ;
        RECT  60.396 55.152 60.48 55.176 ;
    END
  END b_data[107]
  PIN b_data[108]
    DIRECTION OUTPUT ;
    USE SIGNAL ;
    PORT
      LAYER M4 ;
        RECT  60.396 55.296 60.48 55.32 ;
    END
  END b_data[108]
  PIN b_data[109]
    DIRECTION OUTPUT ;
    USE SIGNAL ;
    PORT
      LAYER M4 ;
        RECT  60.396 55.44 60.48 55.464 ;
    END
  END b_data[109]
  PIN b_data[10]
    DIRECTION OUTPUT ;
    USE SIGNAL ;
    PORT
      LAYER M4 ;
        RECT  60.396 41.184 60.48 41.208 ;
    END
  END b_data[10]
  PIN b_data[110]
    DIRECTION OUTPUT ;
    USE SIGNAL ;
    PORT
      LAYER M4 ;
        RECT  60.396 55.584 60.48 55.608 ;
    END
  END b_data[110]
  PIN b_data[111]
    DIRECTION OUTPUT ;
    USE SIGNAL ;
    PORT
      LAYER M4 ;
        RECT  60.396 55.728 60.48 55.752 ;
    END
  END b_data[111]
  PIN b_data[112]
    DIRECTION OUTPUT ;
    USE SIGNAL ;
    PORT
      LAYER M4 ;
        RECT  60.396 55.872 60.48 55.896 ;
    END
  END b_data[112]
  PIN b_data[113]
    DIRECTION OUTPUT ;
    USE SIGNAL ;
    PORT
      LAYER M4 ;
        RECT  60.396 56.016 60.48 56.04 ;
    END
  END b_data[113]
  PIN b_data[114]
    DIRECTION OUTPUT ;
    USE SIGNAL ;
    PORT
      LAYER M4 ;
        RECT  60.396 56.16 60.48 56.184 ;
    END
  END b_data[114]
  PIN b_data[115]
    DIRECTION OUTPUT ;
    USE SIGNAL ;
    PORT
      LAYER M4 ;
        RECT  60.396 56.304 60.48 56.328 ;
    END
  END b_data[115]
  PIN b_data[116]
    DIRECTION OUTPUT ;
    USE SIGNAL ;
    PORT
      LAYER M4 ;
        RECT  60.396 56.448 60.48 56.472 ;
    END
  END b_data[116]
  PIN b_data[117]
    DIRECTION OUTPUT ;
    USE SIGNAL ;
    PORT
      LAYER M4 ;
        RECT  60.396 56.592 60.48 56.616 ;
    END
  END b_data[117]
  PIN b_data[118]
    DIRECTION OUTPUT ;
    USE SIGNAL ;
    PORT
      LAYER M4 ;
        RECT  60.396 56.736 60.48 56.76 ;
    END
  END b_data[118]
  PIN b_data[119]
    DIRECTION OUTPUT ;
    USE SIGNAL ;
    PORT
      LAYER M4 ;
        RECT  60.396 56.88 60.48 56.904 ;
    END
  END b_data[119]
  PIN b_data[11]
    DIRECTION OUTPUT ;
    USE SIGNAL ;
    PORT
      LAYER M4 ;
        RECT  60.396 41.328 60.48 41.352 ;
    END
  END b_data[11]
  PIN b_data[120]
    DIRECTION OUTPUT ;
    USE SIGNAL ;
    PORT
      LAYER M4 ;
        RECT  60.396 57.024 60.48 57.048 ;
    END
  END b_data[120]
  PIN b_data[121]
    DIRECTION OUTPUT ;
    USE SIGNAL ;
    PORT
      LAYER M4 ;
        RECT  60.396 47.952 60.48 47.976 ;
    END
  END b_data[121]
  PIN b_data[122]
    DIRECTION OUTPUT ;
    USE SIGNAL ;
    PORT
      LAYER M4 ;
        RECT  60.396 48.096 60.48 48.12 ;
    END
  END b_data[122]
  PIN b_data[123]
    DIRECTION OUTPUT ;
    USE SIGNAL ;
    PORT
      LAYER M4 ;
        RECT  60.396 48.24 60.48 48.264 ;
    END
  END b_data[123]
  PIN b_data[124]
    DIRECTION OUTPUT ;
    USE SIGNAL ;
    PORT
      LAYER M4 ;
        RECT  60.396 48.384 60.48 48.408 ;
    END
  END b_data[124]
  PIN b_data[125]
    DIRECTION OUTPUT ;
    USE SIGNAL ;
    PORT
      LAYER M4 ;
        RECT  60.396 48.528 60.48 48.552 ;
    END
  END b_data[125]
  PIN b_data[126]
    DIRECTION OUTPUT ;
    USE SIGNAL ;
    PORT
      LAYER M4 ;
        RECT  60.396 48.672 60.48 48.696 ;
    END
  END b_data[126]
  PIN b_data[127]
    DIRECTION OUTPUT ;
    USE SIGNAL ;
    PORT
      LAYER M4 ;
        RECT  60.396 48.816 60.48 48.84 ;
    END
  END b_data[127]
  PIN b_data[128]
    DIRECTION OUTPUT ;
    USE SIGNAL ;
    PORT
      LAYER M4 ;
        RECT  60.396 48.96 60.48 48.984 ;
    END
  END b_data[128]
  PIN b_data[129]
    DIRECTION OUTPUT ;
    USE SIGNAL ;
    PORT
      LAYER M4 ;
        RECT  60.396 49.104 60.48 49.128 ;
    END
  END b_data[129]
  PIN b_data[12]
    DIRECTION OUTPUT ;
    USE SIGNAL ;
    PORT
      LAYER M4 ;
        RECT  60.396 41.472 60.48 41.496 ;
    END
  END b_data[12]
  PIN b_data[130]
    DIRECTION OUTPUT ;
    USE SIGNAL ;
    PORT
      LAYER M4 ;
        RECT  60.396 49.248 60.48 49.272 ;
    END
  END b_data[130]
  PIN b_data[131]
    DIRECTION OUTPUT ;
    USE SIGNAL ;
    PORT
      LAYER M4 ;
        RECT  60.396 49.392 60.48 49.416 ;
    END
  END b_data[131]
  PIN b_data[132]
    DIRECTION OUTPUT ;
    USE SIGNAL ;
    PORT
      LAYER M4 ;
        RECT  60.396 49.536 60.48 49.56 ;
    END
  END b_data[132]
  PIN b_data[133]
    DIRECTION OUTPUT ;
    USE SIGNAL ;
    PORT
      LAYER M4 ;
        RECT  60.396 49.68 60.48 49.704 ;
    END
  END b_data[133]
  PIN b_data[134]
    DIRECTION OUTPUT ;
    USE SIGNAL ;
    PORT
      LAYER M4 ;
        RECT  60.396 49.824 60.48 49.848 ;
    END
  END b_data[134]
  PIN b_data[135]
    DIRECTION OUTPUT ;
    USE SIGNAL ;
    PORT
      LAYER M4 ;
        RECT  60.396 49.968 60.48 49.992 ;
    END
  END b_data[135]
  PIN b_data[136]
    DIRECTION OUTPUT ;
    USE SIGNAL ;
    PORT
      LAYER M4 ;
        RECT  60.396 50.112 60.48 50.136 ;
    END
  END b_data[136]
  PIN b_data[137]
    DIRECTION OUTPUT ;
    USE SIGNAL ;
    PORT
      LAYER M4 ;
        RECT  60.396 50.256 60.48 50.28 ;
    END
  END b_data[137]
  PIN b_data[138]
    DIRECTION OUTPUT ;
    USE SIGNAL ;
    PORT
      LAYER M4 ;
        RECT  60.396 50.4 60.48 50.424 ;
    END
  END b_data[138]
  PIN b_data[139]
    DIRECTION OUTPUT ;
    USE SIGNAL ;
    PORT
      LAYER M4 ;
        RECT  60.396 50.544 60.48 50.568 ;
    END
  END b_data[139]
  PIN b_data[13]
    DIRECTION OUTPUT ;
    USE SIGNAL ;
    PORT
      LAYER M4 ;
        RECT  60.396 41.616 60.48 41.64 ;
    END
  END b_data[13]
  PIN b_data[140]
    DIRECTION OUTPUT ;
    USE SIGNAL ;
    PORT
      LAYER M4 ;
        RECT  60.396 50.688 60.48 50.712 ;
    END
  END b_data[140]
  PIN b_data[141]
    DIRECTION OUTPUT ;
    USE SIGNAL ;
    PORT
      LAYER M4 ;
        RECT  60.396 50.832 60.48 50.856 ;
    END
  END b_data[141]
  PIN b_data[142]
    DIRECTION OUTPUT ;
    USE SIGNAL ;
    PORT
      LAYER M4 ;
        RECT  60.396 50.976 60.48 51 ;
    END
  END b_data[142]
  PIN b_data[143]
    DIRECTION OUTPUT ;
    USE SIGNAL ;
    PORT
      LAYER M4 ;
        RECT  60.396 51.12 60.48 51.144 ;
    END
  END b_data[143]
  PIN b_data[144]
    DIRECTION OUTPUT ;
    USE SIGNAL ;
    PORT
      LAYER M4 ;
        RECT  60.396 51.264 60.48 51.288 ;
    END
  END b_data[144]
  PIN b_data[145]
    DIRECTION OUTPUT ;
    USE SIGNAL ;
    PORT
      LAYER M4 ;
        RECT  60.396 51.408 60.48 51.432 ;
    END
  END b_data[145]
  PIN b_data[146]
    DIRECTION OUTPUT ;
    USE SIGNAL ;
    PORT
      LAYER M4 ;
        RECT  60.396 51.552 60.48 51.576 ;
    END
  END b_data[146]
  PIN b_data[147]
    DIRECTION OUTPUT ;
    USE SIGNAL ;
    PORT
      LAYER M4 ;
        RECT  60.396 51.696 60.48 51.72 ;
    END
  END b_data[147]
  PIN b_data[148]
    DIRECTION OUTPUT ;
    USE SIGNAL ;
    PORT
      LAYER M4 ;
        RECT  60.396 51.84 60.48 51.864 ;
    END
  END b_data[148]
  PIN b_data[149]
    DIRECTION OUTPUT ;
    USE SIGNAL ;
    PORT
      LAYER M4 ;
        RECT  60.396 51.984 60.48 52.008 ;
    END
  END b_data[149]
  PIN b_data[14]
    DIRECTION OUTPUT ;
    USE SIGNAL ;
    PORT
      LAYER M4 ;
        RECT  60.396 41.76 60.48 41.784 ;
    END
  END b_data[14]
  PIN b_data[150]
    DIRECTION OUTPUT ;
    USE SIGNAL ;
    PORT
      LAYER M4 ;
        RECT  60.396 52.128 60.48 52.152 ;
    END
  END b_data[150]
  PIN b_data[151]
    DIRECTION OUTPUT ;
    USE SIGNAL ;
    PORT
      LAYER M4 ;
        RECT  60.396 52.272 60.48 52.296 ;
    END
  END b_data[151]
  PIN b_data[152]
    DIRECTION OUTPUT ;
    USE SIGNAL ;
    PORT
      LAYER M4 ;
        RECT  60.396 52.416 60.48 52.44 ;
    END
  END b_data[152]
  PIN b_data[153]
    DIRECTION OUTPUT ;
    USE SIGNAL ;
    PORT
      LAYER M4 ;
        RECT  60.396 29.52 60.48 29.544 ;
    END
  END b_data[153]
  PIN b_data[154]
    DIRECTION OUTPUT ;
    USE SIGNAL ;
    PORT
      LAYER M4 ;
        RECT  60.396 29.664 60.48 29.688 ;
    END
  END b_data[154]
  PIN b_data[155]
    DIRECTION OUTPUT ;
    USE SIGNAL ;
    PORT
      LAYER M4 ;
        RECT  60.396 29.808 60.48 29.832 ;
    END
  END b_data[155]
  PIN b_data[156]
    DIRECTION OUTPUT ;
    USE SIGNAL ;
    PORT
      LAYER M4 ;
        RECT  60.396 29.952 60.48 29.976 ;
    END
  END b_data[156]
  PIN b_data[157]
    DIRECTION OUTPUT ;
    USE SIGNAL ;
    PORT
      LAYER M4 ;
        RECT  60.396 30.096 60.48 30.12 ;
    END
  END b_data[157]
  PIN b_data[158]
    DIRECTION OUTPUT ;
    USE SIGNAL ;
    PORT
      LAYER M4 ;
        RECT  60.396 30.24 60.48 30.264 ;
    END
  END b_data[158]
  PIN b_data[159]
    DIRECTION OUTPUT ;
    USE SIGNAL ;
    PORT
      LAYER M4 ;
        RECT  60.396 30.384 60.48 30.408 ;
    END
  END b_data[159]
  PIN b_data[15]
    DIRECTION OUTPUT ;
    USE SIGNAL ;
    PORT
      LAYER M4 ;
        RECT  60.396 41.904 60.48 41.928 ;
    END
  END b_data[15]
  PIN b_data[160]
    DIRECTION OUTPUT ;
    USE SIGNAL ;
    PORT
      LAYER M4 ;
        RECT  60.396 30.528 60.48 30.552 ;
    END
  END b_data[160]
  PIN b_data[161]
    DIRECTION OUTPUT ;
    USE SIGNAL ;
    PORT
      LAYER M4 ;
        RECT  60.396 30.672 60.48 30.696 ;
    END
  END b_data[161]
  PIN b_data[162]
    DIRECTION OUTPUT ;
    USE SIGNAL ;
    PORT
      LAYER M4 ;
        RECT  60.396 30.816 60.48 30.84 ;
    END
  END b_data[162]
  PIN b_data[163]
    DIRECTION OUTPUT ;
    USE SIGNAL ;
    PORT
      LAYER M4 ;
        RECT  60.396 30.96 60.48 30.984 ;
    END
  END b_data[163]
  PIN b_data[164]
    DIRECTION OUTPUT ;
    USE SIGNAL ;
    PORT
      LAYER M4 ;
        RECT  60.396 31.104 60.48 31.128 ;
    END
  END b_data[164]
  PIN b_data[165]
    DIRECTION OUTPUT ;
    USE SIGNAL ;
    PORT
      LAYER M4 ;
        RECT  60.396 31.248 60.48 31.272 ;
    END
  END b_data[165]
  PIN b_data[166]
    DIRECTION OUTPUT ;
    USE SIGNAL ;
    PORT
      LAYER M4 ;
        RECT  60.396 31.392 60.48 31.416 ;
    END
  END b_data[166]
  PIN b_data[167]
    DIRECTION OUTPUT ;
    USE SIGNAL ;
    PORT
      LAYER M4 ;
        RECT  60.396 31.536 60.48 31.56 ;
    END
  END b_data[167]
  PIN b_data[168]
    DIRECTION OUTPUT ;
    USE SIGNAL ;
    PORT
      LAYER M4 ;
        RECT  60.396 31.68 60.48 31.704 ;
    END
  END b_data[168]
  PIN b_data[169]
    DIRECTION OUTPUT ;
    USE SIGNAL ;
    PORT
      LAYER M4 ;
        RECT  60.396 31.824 60.48 31.848 ;
    END
  END b_data[169]
  PIN b_data[16]
    DIRECTION OUTPUT ;
    USE SIGNAL ;
    PORT
      LAYER M4 ;
        RECT  60.396 42.048 60.48 42.072 ;
    END
  END b_data[16]
  PIN b_data[170]
    DIRECTION OUTPUT ;
    USE SIGNAL ;
    PORT
      LAYER M4 ;
        RECT  60.396 31.968 60.48 31.992 ;
    END
  END b_data[170]
  PIN b_data[171]
    DIRECTION OUTPUT ;
    USE SIGNAL ;
    PORT
      LAYER M4 ;
        RECT  60.396 32.112 60.48 32.136 ;
    END
  END b_data[171]
  PIN b_data[172]
    DIRECTION OUTPUT ;
    USE SIGNAL ;
    PORT
      LAYER M4 ;
        RECT  60.396 32.256 60.48 32.28 ;
    END
  END b_data[172]
  PIN b_data[173]
    DIRECTION OUTPUT ;
    USE SIGNAL ;
    PORT
      LAYER M4 ;
        RECT  60.396 32.4 60.48 32.424 ;
    END
  END b_data[173]
  PIN b_data[174]
    DIRECTION OUTPUT ;
    USE SIGNAL ;
    PORT
      LAYER M4 ;
        RECT  60.396 32.544 60.48 32.568 ;
    END
  END b_data[174]
  PIN b_data[175]
    DIRECTION OUTPUT ;
    USE SIGNAL ;
    PORT
      LAYER M4 ;
        RECT  60.396 32.688 60.48 32.712 ;
    END
  END b_data[175]
  PIN b_data[176]
    DIRECTION OUTPUT ;
    USE SIGNAL ;
    PORT
      LAYER M4 ;
        RECT  60.396 32.832 60.48 32.856 ;
    END
  END b_data[176]
  PIN b_data[177]
    DIRECTION OUTPUT ;
    USE SIGNAL ;
    PORT
      LAYER M4 ;
        RECT  60.396 32.976 60.48 33 ;
    END
  END b_data[177]
  PIN b_data[178]
    DIRECTION OUTPUT ;
    USE SIGNAL ;
    PORT
      LAYER M4 ;
        RECT  60.396 33.12 60.48 33.144 ;
    END
  END b_data[178]
  PIN b_data[179]
    DIRECTION OUTPUT ;
    USE SIGNAL ;
    PORT
      LAYER M4 ;
        RECT  60.396 33.264 60.48 33.288 ;
    END
  END b_data[179]
  PIN b_data[17]
    DIRECTION OUTPUT ;
    USE SIGNAL ;
    PORT
      LAYER M4 ;
        RECT  60.396 42.192 60.48 42.216 ;
    END
  END b_data[17]
  PIN b_data[180]
    DIRECTION OUTPUT ;
    USE SIGNAL ;
    PORT
      LAYER M4 ;
        RECT  60.396 33.408 60.48 33.432 ;
    END
  END b_data[180]
  PIN b_data[181]
    DIRECTION OUTPUT ;
    USE SIGNAL ;
    PORT
      LAYER M4 ;
        RECT  60.396 33.552 60.48 33.576 ;
    END
  END b_data[181]
  PIN b_data[182]
    DIRECTION OUTPUT ;
    USE SIGNAL ;
    PORT
      LAYER M4 ;
        RECT  60.396 33.696 60.48 33.72 ;
    END
  END b_data[182]
  PIN b_data[183]
    DIRECTION OUTPUT ;
    USE SIGNAL ;
    PORT
      LAYER M4 ;
        RECT  60.396 33.84 60.48 33.864 ;
    END
  END b_data[183]
  PIN b_data[184]
    DIRECTION OUTPUT ;
    USE SIGNAL ;
    PORT
      LAYER M4 ;
        RECT  60.396 33.984 60.48 34.008 ;
    END
  END b_data[184]
  PIN b_data[185]
    DIRECTION OUTPUT ;
    USE SIGNAL ;
    PORT
      LAYER M4 ;
        RECT  60.396 23.76 60.48 23.784 ;
    END
  END b_data[185]
  PIN b_data[186]
    DIRECTION OUTPUT ;
    USE SIGNAL ;
    PORT
      LAYER M4 ;
        RECT  60.396 23.904 60.48 23.928 ;
    END
  END b_data[186]
  PIN b_data[187]
    DIRECTION OUTPUT ;
    USE SIGNAL ;
    PORT
      LAYER M4 ;
        RECT  60.396 24.048 60.48 24.072 ;
    END
  END b_data[187]
  PIN b_data[188]
    DIRECTION OUTPUT ;
    USE SIGNAL ;
    PORT
      LAYER M4 ;
        RECT  60.396 24.192 60.48 24.216 ;
    END
  END b_data[188]
  PIN b_data[189]
    DIRECTION OUTPUT ;
    USE SIGNAL ;
    PORT
      LAYER M4 ;
        RECT  60.396 24.336 60.48 24.36 ;
    END
  END b_data[189]
  PIN b_data[18]
    DIRECTION OUTPUT ;
    USE SIGNAL ;
    PORT
      LAYER M4 ;
        RECT  60.396 42.336 60.48 42.36 ;
    END
  END b_data[18]
  PIN b_data[190]
    DIRECTION OUTPUT ;
    USE SIGNAL ;
    PORT
      LAYER M4 ;
        RECT  60.396 24.48 60.48 24.504 ;
    END
  END b_data[190]
  PIN b_data[191]
    DIRECTION OUTPUT ;
    USE SIGNAL ;
    PORT
      LAYER M4 ;
        RECT  60.396 24.624 60.48 24.648 ;
    END
  END b_data[191]
  PIN b_data[192]
    DIRECTION OUTPUT ;
    USE SIGNAL ;
    PORT
      LAYER M4 ;
        RECT  60.396 24.768 60.48 24.792 ;
    END
  END b_data[192]
  PIN b_data[193]
    DIRECTION OUTPUT ;
    USE SIGNAL ;
    PORT
      LAYER M4 ;
        RECT  60.396 24.912 60.48 24.936 ;
    END
  END b_data[193]
  PIN b_data[194]
    DIRECTION OUTPUT ;
    USE SIGNAL ;
    PORT
      LAYER M4 ;
        RECT  60.396 25.056 60.48 25.08 ;
    END
  END b_data[194]
  PIN b_data[195]
    DIRECTION OUTPUT ;
    USE SIGNAL ;
    PORT
      LAYER M4 ;
        RECT  60.396 25.2 60.48 25.224 ;
    END
  END b_data[195]
  PIN b_data[196]
    DIRECTION OUTPUT ;
    USE SIGNAL ;
    PORT
      LAYER M4 ;
        RECT  60.396 25.344 60.48 25.368 ;
    END
  END b_data[196]
  PIN b_data[197]
    DIRECTION OUTPUT ;
    USE SIGNAL ;
    PORT
      LAYER M4 ;
        RECT  60.396 25.488 60.48 25.512 ;
    END
  END b_data[197]
  PIN b_data[198]
    DIRECTION OUTPUT ;
    USE SIGNAL ;
    PORT
      LAYER M4 ;
        RECT  60.396 25.632 60.48 25.656 ;
    END
  END b_data[198]
  PIN b_data[199]
    DIRECTION OUTPUT ;
    USE SIGNAL ;
    PORT
      LAYER M4 ;
        RECT  60.396 25.776 60.48 25.8 ;
    END
  END b_data[199]
  PIN b_data[19]
    DIRECTION OUTPUT ;
    USE SIGNAL ;
    PORT
      LAYER M4 ;
        RECT  60.396 42.48 60.48 42.504 ;
    END
  END b_data[19]
  PIN b_data[1]
    DIRECTION OUTPUT ;
    USE SIGNAL ;
    PORT
      LAYER M4 ;
        RECT  60.396 39.888 60.48 39.912 ;
    END
  END b_data[1]
  PIN b_data[200]
    DIRECTION OUTPUT ;
    USE SIGNAL ;
    PORT
      LAYER M4 ;
        RECT  60.396 25.92 60.48 25.944 ;
    END
  END b_data[200]
  PIN b_data[201]
    DIRECTION OUTPUT ;
    USE SIGNAL ;
    PORT
      LAYER M4 ;
        RECT  60.396 26.064 60.48 26.088 ;
    END
  END b_data[201]
  PIN b_data[202]
    DIRECTION OUTPUT ;
    USE SIGNAL ;
    PORT
      LAYER M4 ;
        RECT  60.396 26.208 60.48 26.232 ;
    END
  END b_data[202]
  PIN b_data[203]
    DIRECTION OUTPUT ;
    USE SIGNAL ;
    PORT
      LAYER M4 ;
        RECT  60.396 26.352 60.48 26.376 ;
    END
  END b_data[203]
  PIN b_data[204]
    DIRECTION OUTPUT ;
    USE SIGNAL ;
    PORT
      LAYER M4 ;
        RECT  60.396 26.496 60.48 26.52 ;
    END
  END b_data[204]
  PIN b_data[205]
    DIRECTION OUTPUT ;
    USE SIGNAL ;
    PORT
      LAYER M4 ;
        RECT  60.396 26.64 60.48 26.664 ;
    END
  END b_data[205]
  PIN b_data[206]
    DIRECTION OUTPUT ;
    USE SIGNAL ;
    PORT
      LAYER M4 ;
        RECT  60.396 26.784 60.48 26.808 ;
    END
  END b_data[206]
  PIN b_data[207]
    DIRECTION OUTPUT ;
    USE SIGNAL ;
    PORT
      LAYER M4 ;
        RECT  60.396 26.928 60.48 26.952 ;
    END
  END b_data[207]
  PIN b_data[208]
    DIRECTION OUTPUT ;
    USE SIGNAL ;
    PORT
      LAYER M4 ;
        RECT  60.396 27.072 60.48 27.096 ;
    END
  END b_data[208]
  PIN b_data[209]
    DIRECTION OUTPUT ;
    USE SIGNAL ;
    PORT
      LAYER M4 ;
        RECT  60.396 27.216 60.48 27.24 ;
    END
  END b_data[209]
  PIN b_data[20]
    DIRECTION OUTPUT ;
    USE SIGNAL ;
    PORT
      LAYER M4 ;
        RECT  60.396 42.624 60.48 42.648 ;
    END
  END b_data[20]
  PIN b_data[210]
    DIRECTION OUTPUT ;
    USE SIGNAL ;
    PORT
      LAYER M4 ;
        RECT  60.396 27.36 60.48 27.384 ;
    END
  END b_data[210]
  PIN b_data[211]
    DIRECTION OUTPUT ;
    USE SIGNAL ;
    PORT
      LAYER M4 ;
        RECT  60.396 27.504 60.48 27.528 ;
    END
  END b_data[211]
  PIN b_data[212]
    DIRECTION OUTPUT ;
    USE SIGNAL ;
    PORT
      LAYER M4 ;
        RECT  60.396 27.648 60.48 27.672 ;
    END
  END b_data[212]
  PIN b_data[213]
    DIRECTION OUTPUT ;
    USE SIGNAL ;
    PORT
      LAYER M4 ;
        RECT  60.396 27.792 60.48 27.816 ;
    END
  END b_data[213]
  PIN b_data[214]
    DIRECTION OUTPUT ;
    USE SIGNAL ;
    PORT
      LAYER M4 ;
        RECT  60.396 27.936 60.48 27.96 ;
    END
  END b_data[214]
  PIN b_data[215]
    DIRECTION OUTPUT ;
    USE SIGNAL ;
    PORT
      LAYER M4 ;
        RECT  60.396 28.08 60.48 28.104 ;
    END
  END b_data[215]
  PIN b_data[216]
    DIRECTION OUTPUT ;
    USE SIGNAL ;
    PORT
      LAYER M4 ;
        RECT  60.396 28.224 60.48 28.248 ;
    END
  END b_data[216]
  PIN b_data[217]
    DIRECTION OUTPUT ;
    USE SIGNAL ;
    PORT
      LAYER M4 ;
        RECT  60.396 19.152 60.48 19.176 ;
    END
  END b_data[217]
  PIN b_data[218]
    DIRECTION OUTPUT ;
    USE SIGNAL ;
    PORT
      LAYER M4 ;
        RECT  60.396 19.296 60.48 19.32 ;
    END
  END b_data[218]
  PIN b_data[219]
    DIRECTION OUTPUT ;
    USE SIGNAL ;
    PORT
      LAYER M4 ;
        RECT  60.396 19.44 60.48 19.464 ;
    END
  END b_data[219]
  PIN b_data[21]
    DIRECTION OUTPUT ;
    USE SIGNAL ;
    PORT
      LAYER M4 ;
        RECT  60.396 42.768 60.48 42.792 ;
    END
  END b_data[21]
  PIN b_data[220]
    DIRECTION OUTPUT ;
    USE SIGNAL ;
    PORT
      LAYER M4 ;
        RECT  60.396 19.584 60.48 19.608 ;
    END
  END b_data[220]
  PIN b_data[221]
    DIRECTION OUTPUT ;
    USE SIGNAL ;
    PORT
      LAYER M4 ;
        RECT  60.396 19.728 60.48 19.752 ;
    END
  END b_data[221]
  PIN b_data[222]
    DIRECTION OUTPUT ;
    USE SIGNAL ;
    PORT
      LAYER M4 ;
        RECT  60.396 19.872 60.48 19.896 ;
    END
  END b_data[222]
  PIN b_data[223]
    DIRECTION OUTPUT ;
    USE SIGNAL ;
    PORT
      LAYER M4 ;
        RECT  60.396 20.016 60.48 20.04 ;
    END
  END b_data[223]
  PIN b_data[224]
    DIRECTION OUTPUT ;
    USE SIGNAL ;
    PORT
      LAYER M4 ;
        RECT  60.396 20.16 60.48 20.184 ;
    END
  END b_data[224]
  PIN b_data[225]
    DIRECTION OUTPUT ;
    USE SIGNAL ;
    PORT
      LAYER M4 ;
        RECT  60.396 20.304 60.48 20.328 ;
    END
  END b_data[225]
  PIN b_data[226]
    DIRECTION OUTPUT ;
    USE SIGNAL ;
    PORT
      LAYER M4 ;
        RECT  60.396 20.448 60.48 20.472 ;
    END
  END b_data[226]
  PIN b_data[227]
    DIRECTION OUTPUT ;
    USE SIGNAL ;
    PORT
      LAYER M4 ;
        RECT  60.396 20.592 60.48 20.616 ;
    END
  END b_data[227]
  PIN b_data[228]
    DIRECTION OUTPUT ;
    USE SIGNAL ;
    PORT
      LAYER M4 ;
        RECT  60.396 20.736 60.48 20.76 ;
    END
  END b_data[228]
  PIN b_data[229]
    DIRECTION OUTPUT ;
    USE SIGNAL ;
    PORT
      LAYER M4 ;
        RECT  60.396 20.88 60.48 20.904 ;
    END
  END b_data[229]
  PIN b_data[22]
    DIRECTION OUTPUT ;
    USE SIGNAL ;
    PORT
      LAYER M4 ;
        RECT  60.396 42.912 60.48 42.936 ;
    END
  END b_data[22]
  PIN b_data[230]
    DIRECTION OUTPUT ;
    USE SIGNAL ;
    PORT
      LAYER M4 ;
        RECT  60.396 21.024 60.48 21.048 ;
    END
  END b_data[230]
  PIN b_data[231]
    DIRECTION OUTPUT ;
    USE SIGNAL ;
    PORT
      LAYER M4 ;
        RECT  60.396 21.168 60.48 21.192 ;
    END
  END b_data[231]
  PIN b_data[232]
    DIRECTION OUTPUT ;
    USE SIGNAL ;
    PORT
      LAYER M4 ;
        RECT  60.396 21.312 60.48 21.336 ;
    END
  END b_data[232]
  PIN b_data[233]
    DIRECTION OUTPUT ;
    USE SIGNAL ;
    PORT
      LAYER M4 ;
        RECT  60.396 21.456 60.48 21.48 ;
    END
  END b_data[233]
  PIN b_data[234]
    DIRECTION OUTPUT ;
    USE SIGNAL ;
    PORT
      LAYER M4 ;
        RECT  60.396 21.6 60.48 21.624 ;
    END
  END b_data[234]
  PIN b_data[235]
    DIRECTION OUTPUT ;
    USE SIGNAL ;
    PORT
      LAYER M4 ;
        RECT  60.396 21.744 60.48 21.768 ;
    END
  END b_data[235]
  PIN b_data[236]
    DIRECTION OUTPUT ;
    USE SIGNAL ;
    PORT
      LAYER M4 ;
        RECT  60.396 21.888 60.48 21.912 ;
    END
  END b_data[236]
  PIN b_data[237]
    DIRECTION OUTPUT ;
    USE SIGNAL ;
    PORT
      LAYER M4 ;
        RECT  60.396 22.032 60.48 22.056 ;
    END
  END b_data[237]
  PIN b_data[238]
    DIRECTION OUTPUT ;
    USE SIGNAL ;
    PORT
      LAYER M4 ;
        RECT  60.396 22.176 60.48 22.2 ;
    END
  END b_data[238]
  PIN b_data[239]
    DIRECTION OUTPUT ;
    USE SIGNAL ;
    PORT
      LAYER M4 ;
        RECT  60.396 22.32 60.48 22.344 ;
    END
  END b_data[239]
  PIN b_data[23]
    DIRECTION OUTPUT ;
    USE SIGNAL ;
    PORT
      LAYER M4 ;
        RECT  60.396 43.056 60.48 43.08 ;
    END
  END b_data[23]
  PIN b_data[240]
    DIRECTION OUTPUT ;
    USE SIGNAL ;
    PORT
      LAYER M4 ;
        RECT  60.396 22.464 60.48 22.488 ;
    END
  END b_data[240]
  PIN b_data[241]
    DIRECTION OUTPUT ;
    USE SIGNAL ;
    PORT
      LAYER M4 ;
        RECT  60.396 22.608 60.48 22.632 ;
    END
  END b_data[241]
  PIN b_data[242]
    DIRECTION OUTPUT ;
    USE SIGNAL ;
    PORT
      LAYER M4 ;
        RECT  60.396 22.752 60.48 22.776 ;
    END
  END b_data[242]
  PIN b_data[243]
    DIRECTION OUTPUT ;
    USE SIGNAL ;
    PORT
      LAYER M4 ;
        RECT  60.396 22.896 60.48 22.92 ;
    END
  END b_data[243]
  PIN b_data[244]
    DIRECTION OUTPUT ;
    USE SIGNAL ;
    PORT
      LAYER M4 ;
        RECT  60.396 23.04 60.48 23.064 ;
    END
  END b_data[244]
  PIN b_data[245]
    DIRECTION OUTPUT ;
    USE SIGNAL ;
    PORT
      LAYER M4 ;
        RECT  60.396 23.184 60.48 23.208 ;
    END
  END b_data[245]
  PIN b_data[246]
    DIRECTION OUTPUT ;
    USE SIGNAL ;
    PORT
      LAYER M4 ;
        RECT  60.396 23.328 60.48 23.352 ;
    END
  END b_data[246]
  PIN b_data[247]
    DIRECTION OUTPUT ;
    USE SIGNAL ;
    PORT
      LAYER M4 ;
        RECT  60.396 23.472 60.48 23.496 ;
    END
  END b_data[247]
  PIN b_data[248]
    DIRECTION OUTPUT ;
    USE SIGNAL ;
    PORT
      LAYER M4 ;
        RECT  60.396 23.616 60.48 23.64 ;
    END
  END b_data[248]
  PIN b_data[249]
    DIRECTION OUTPUT ;
    USE SIGNAL ;
    PORT
      LAYER M4 ;
        RECT  60.396 28.368 60.48 28.392 ;
    END
  END b_data[249]
  PIN b_data[24]
    DIRECTION OUTPUT ;
    USE SIGNAL ;
    PORT
      LAYER M4 ;
        RECT  60.396 43.2 60.48 43.224 ;
    END
  END b_data[24]
  PIN b_data[250]
    DIRECTION OUTPUT ;
    USE SIGNAL ;
    PORT
      LAYER M4 ;
        RECT  60.396 28.512 60.48 28.536 ;
    END
  END b_data[250]
  PIN b_data[251]
    DIRECTION OUTPUT ;
    USE SIGNAL ;
    PORT
      LAYER M4 ;
        RECT  60.396 28.656 60.48 28.68 ;
    END
  END b_data[251]
  PIN b_data[252]
    DIRECTION OUTPUT ;
    USE SIGNAL ;
    PORT
      LAYER M4 ;
        RECT  60.396 28.8 60.48 28.824 ;
    END
  END b_data[252]
  PIN b_data[253]
    DIRECTION OUTPUT ;
    USE SIGNAL ;
    PORT
      LAYER M4 ;
        RECT  60.396 28.944 60.48 28.968 ;
    END
  END b_data[253]
  PIN b_data[254]
    DIRECTION OUTPUT ;
    USE SIGNAL ;
    PORT
      LAYER M4 ;
        RECT  60.396 29.088 60.48 29.112 ;
    END
  END b_data[254]
  PIN b_data[255]
    DIRECTION OUTPUT ;
    USE SIGNAL ;
    PORT
      LAYER M4 ;
        RECT  60.396 29.232 60.48 29.256 ;
    END
  END b_data[255]
  PIN b_data[25]
    DIRECTION OUTPUT ;
    USE SIGNAL ;
    PORT
      LAYER M4 ;
        RECT  60.396 34.128 60.48 34.152 ;
    END
  END b_data[25]
  PIN b_data[26]
    DIRECTION OUTPUT ;
    USE SIGNAL ;
    PORT
      LAYER M4 ;
        RECT  60.396 34.272 60.48 34.296 ;
    END
  END b_data[26]
  PIN b_data[27]
    DIRECTION OUTPUT ;
    USE SIGNAL ;
    PORT
      LAYER M4 ;
        RECT  60.396 34.416 60.48 34.44 ;
    END
  END b_data[27]
  PIN b_data[28]
    DIRECTION OUTPUT ;
    USE SIGNAL ;
    PORT
      LAYER M4 ;
        RECT  60.396 34.56 60.48 34.584 ;
    END
  END b_data[28]
  PIN b_data[29]
    DIRECTION OUTPUT ;
    USE SIGNAL ;
    PORT
      LAYER M4 ;
        RECT  60.396 34.704 60.48 34.728 ;
    END
  END b_data[29]
  PIN b_data[2]
    DIRECTION OUTPUT ;
    USE SIGNAL ;
    PORT
      LAYER M4 ;
        RECT  60.396 40.032 60.48 40.056 ;
    END
  END b_data[2]
  PIN b_data[30]
    DIRECTION OUTPUT ;
    USE SIGNAL ;
    PORT
      LAYER M4 ;
        RECT  60.396 34.848 60.48 34.872 ;
    END
  END b_data[30]
  PIN b_data[31]
    DIRECTION OUTPUT ;
    USE SIGNAL ;
    PORT
      LAYER M4 ;
        RECT  60.396 34.992 60.48 35.016 ;
    END
  END b_data[31]
  PIN b_data[32]
    DIRECTION OUTPUT ;
    USE SIGNAL ;
    PORT
      LAYER M4 ;
        RECT  60.396 35.136 60.48 35.16 ;
    END
  END b_data[32]
  PIN b_data[33]
    DIRECTION OUTPUT ;
    USE SIGNAL ;
    PORT
      LAYER M4 ;
        RECT  60.396 35.28 60.48 35.304 ;
    END
  END b_data[33]
  PIN b_data[34]
    DIRECTION OUTPUT ;
    USE SIGNAL ;
    PORT
      LAYER M4 ;
        RECT  60.396 35.424 60.48 35.448 ;
    END
  END b_data[34]
  PIN b_data[35]
    DIRECTION OUTPUT ;
    USE SIGNAL ;
    PORT
      LAYER M4 ;
        RECT  60.396 35.568 60.48 35.592 ;
    END
  END b_data[35]
  PIN b_data[36]
    DIRECTION OUTPUT ;
    USE SIGNAL ;
    PORT
      LAYER M4 ;
        RECT  60.396 35.712 60.48 35.736 ;
    END
  END b_data[36]
  PIN b_data[37]
    DIRECTION OUTPUT ;
    USE SIGNAL ;
    PORT
      LAYER M4 ;
        RECT  60.396 35.856 60.48 35.88 ;
    END
  END b_data[37]
  PIN b_data[38]
    DIRECTION OUTPUT ;
    USE SIGNAL ;
    PORT
      LAYER M4 ;
        RECT  60.396 36 60.48 36.024 ;
    END
  END b_data[38]
  PIN b_data[39]
    DIRECTION OUTPUT ;
    USE SIGNAL ;
    PORT
      LAYER M4 ;
        RECT  60.396 36.144 60.48 36.168 ;
    END
  END b_data[39]
  PIN b_data[3]
    DIRECTION OUTPUT ;
    USE SIGNAL ;
    PORT
      LAYER M4 ;
        RECT  60.396 40.176 60.48 40.2 ;
    END
  END b_data[3]
  PIN b_data[40]
    DIRECTION OUTPUT ;
    USE SIGNAL ;
    PORT
      LAYER M4 ;
        RECT  60.396 36.288 60.48 36.312 ;
    END
  END b_data[40]
  PIN b_data[41]
    DIRECTION OUTPUT ;
    USE SIGNAL ;
    PORT
      LAYER M4 ;
        RECT  60.396 36.432 60.48 36.456 ;
    END
  END b_data[41]
  PIN b_data[42]
    DIRECTION OUTPUT ;
    USE SIGNAL ;
    PORT
      LAYER M4 ;
        RECT  60.396 36.576 60.48 36.6 ;
    END
  END b_data[42]
  PIN b_data[43]
    DIRECTION OUTPUT ;
    USE SIGNAL ;
    PORT
      LAYER M4 ;
        RECT  60.396 36.72 60.48 36.744 ;
    END
  END b_data[43]
  PIN b_data[44]
    DIRECTION OUTPUT ;
    USE SIGNAL ;
    PORT
      LAYER M4 ;
        RECT  60.396 36.864 60.48 36.888 ;
    END
  END b_data[44]
  PIN b_data[45]
    DIRECTION OUTPUT ;
    USE SIGNAL ;
    PORT
      LAYER M4 ;
        RECT  60.396 37.008 60.48 37.032 ;
    END
  END b_data[45]
  PIN b_data[46]
    DIRECTION OUTPUT ;
    USE SIGNAL ;
    PORT
      LAYER M4 ;
        RECT  60.396 37.152 60.48 37.176 ;
    END
  END b_data[46]
  PIN b_data[47]
    DIRECTION OUTPUT ;
    USE SIGNAL ;
    PORT
      LAYER M4 ;
        RECT  60.396 37.296 60.48 37.32 ;
    END
  END b_data[47]
  PIN b_data[48]
    DIRECTION OUTPUT ;
    USE SIGNAL ;
    PORT
      LAYER M4 ;
        RECT  60.396 37.44 60.48 37.464 ;
    END
  END b_data[48]
  PIN b_data[49]
    DIRECTION OUTPUT ;
    USE SIGNAL ;
    PORT
      LAYER M4 ;
        RECT  60.396 37.584 60.48 37.608 ;
    END
  END b_data[49]
  PIN b_data[4]
    DIRECTION OUTPUT ;
    USE SIGNAL ;
    PORT
      LAYER M4 ;
        RECT  60.396 40.32 60.48 40.344 ;
    END
  END b_data[4]
  PIN b_data[50]
    DIRECTION OUTPUT ;
    USE SIGNAL ;
    PORT
      LAYER M4 ;
        RECT  60.396 37.728 60.48 37.752 ;
    END
  END b_data[50]
  PIN b_data[51]
    DIRECTION OUTPUT ;
    USE SIGNAL ;
    PORT
      LAYER M4 ;
        RECT  60.396 37.872 60.48 37.896 ;
    END
  END b_data[51]
  PIN b_data[52]
    DIRECTION OUTPUT ;
    USE SIGNAL ;
    PORT
      LAYER M4 ;
        RECT  60.396 38.016 60.48 38.04 ;
    END
  END b_data[52]
  PIN b_data[53]
    DIRECTION OUTPUT ;
    USE SIGNAL ;
    PORT
      LAYER M4 ;
        RECT  60.396 38.16 60.48 38.184 ;
    END
  END b_data[53]
  PIN b_data[54]
    DIRECTION OUTPUT ;
    USE SIGNAL ;
    PORT
      LAYER M4 ;
        RECT  60.396 38.304 60.48 38.328 ;
    END
  END b_data[54]
  PIN b_data[55]
    DIRECTION OUTPUT ;
    USE SIGNAL ;
    PORT
      LAYER M4 ;
        RECT  60.396 38.448 60.48 38.472 ;
    END
  END b_data[55]
  PIN b_data[56]
    DIRECTION OUTPUT ;
    USE SIGNAL ;
    PORT
      LAYER M4 ;
        RECT  60.396 38.592 60.48 38.616 ;
    END
  END b_data[56]
  PIN b_data[57]
    DIRECTION OUTPUT ;
    USE SIGNAL ;
    PORT
      LAYER M4 ;
        RECT  60.396 43.344 60.48 43.368 ;
    END
  END b_data[57]
  PIN b_data[58]
    DIRECTION OUTPUT ;
    USE SIGNAL ;
    PORT
      LAYER M4 ;
        RECT  60.396 43.488 60.48 43.512 ;
    END
  END b_data[58]
  PIN b_data[59]
    DIRECTION OUTPUT ;
    USE SIGNAL ;
    PORT
      LAYER M4 ;
        RECT  60.396 43.632 60.48 43.656 ;
    END
  END b_data[59]
  PIN b_data[5]
    DIRECTION OUTPUT ;
    USE SIGNAL ;
    PORT
      LAYER M4 ;
        RECT  60.396 40.464 60.48 40.488 ;
    END
  END b_data[5]
  PIN b_data[60]
    DIRECTION OUTPUT ;
    USE SIGNAL ;
    PORT
      LAYER M4 ;
        RECT  60.396 43.776 60.48 43.8 ;
    END
  END b_data[60]
  PIN b_data[61]
    DIRECTION OUTPUT ;
    USE SIGNAL ;
    PORT
      LAYER M4 ;
        RECT  60.396 43.92 60.48 43.944 ;
    END
  END b_data[61]
  PIN b_data[62]
    DIRECTION OUTPUT ;
    USE SIGNAL ;
    PORT
      LAYER M4 ;
        RECT  60.396 44.064 60.48 44.088 ;
    END
  END b_data[62]
  PIN b_data[63]
    DIRECTION OUTPUT ;
    USE SIGNAL ;
    PORT
      LAYER M4 ;
        RECT  60.396 44.208 60.48 44.232 ;
    END
  END b_data[63]
  PIN b_data[64]
    DIRECTION OUTPUT ;
    USE SIGNAL ;
    PORT
      LAYER M4 ;
        RECT  60.396 44.352 60.48 44.376 ;
    END
  END b_data[64]
  PIN b_data[65]
    DIRECTION OUTPUT ;
    USE SIGNAL ;
    PORT
      LAYER M4 ;
        RECT  60.396 44.496 60.48 44.52 ;
    END
  END b_data[65]
  PIN b_data[66]
    DIRECTION OUTPUT ;
    USE SIGNAL ;
    PORT
      LAYER M4 ;
        RECT  60.396 44.64 60.48 44.664 ;
    END
  END b_data[66]
  PIN b_data[67]
    DIRECTION OUTPUT ;
    USE SIGNAL ;
    PORT
      LAYER M4 ;
        RECT  60.396 44.784 60.48 44.808 ;
    END
  END b_data[67]
  PIN b_data[68]
    DIRECTION OUTPUT ;
    USE SIGNAL ;
    PORT
      LAYER M4 ;
        RECT  60.396 44.928 60.48 44.952 ;
    END
  END b_data[68]
  PIN b_data[69]
    DIRECTION OUTPUT ;
    USE SIGNAL ;
    PORT
      LAYER M4 ;
        RECT  60.396 45.072 60.48 45.096 ;
    END
  END b_data[69]
  PIN b_data[6]
    DIRECTION OUTPUT ;
    USE SIGNAL ;
    PORT
      LAYER M4 ;
        RECT  60.396 40.608 60.48 40.632 ;
    END
  END b_data[6]
  PIN b_data[70]
    DIRECTION OUTPUT ;
    USE SIGNAL ;
    PORT
      LAYER M4 ;
        RECT  60.396 45.216 60.48 45.24 ;
    END
  END b_data[70]
  PIN b_data[71]
    DIRECTION OUTPUT ;
    USE SIGNAL ;
    PORT
      LAYER M4 ;
        RECT  60.396 45.36 60.48 45.384 ;
    END
  END b_data[71]
  PIN b_data[72]
    DIRECTION OUTPUT ;
    USE SIGNAL ;
    PORT
      LAYER M4 ;
        RECT  60.396 45.504 60.48 45.528 ;
    END
  END b_data[72]
  PIN b_data[73]
    DIRECTION OUTPUT ;
    USE SIGNAL ;
    PORT
      LAYER M4 ;
        RECT  60.396 45.648 60.48 45.672 ;
    END
  END b_data[73]
  PIN b_data[74]
    DIRECTION OUTPUT ;
    USE SIGNAL ;
    PORT
      LAYER M4 ;
        RECT  60.396 45.792 60.48 45.816 ;
    END
  END b_data[74]
  PIN b_data[75]
    DIRECTION OUTPUT ;
    USE SIGNAL ;
    PORT
      LAYER M4 ;
        RECT  60.396 45.936 60.48 45.96 ;
    END
  END b_data[75]
  PIN b_data[76]
    DIRECTION OUTPUT ;
    USE SIGNAL ;
    PORT
      LAYER M4 ;
        RECT  60.396 46.08 60.48 46.104 ;
    END
  END b_data[76]
  PIN b_data[77]
    DIRECTION OUTPUT ;
    USE SIGNAL ;
    PORT
      LAYER M4 ;
        RECT  60.396 46.224 60.48 46.248 ;
    END
  END b_data[77]
  PIN b_data[78]
    DIRECTION OUTPUT ;
    USE SIGNAL ;
    PORT
      LAYER M4 ;
        RECT  60.396 46.368 60.48 46.392 ;
    END
  END b_data[78]
  PIN b_data[79]
    DIRECTION OUTPUT ;
    USE SIGNAL ;
    PORT
      LAYER M4 ;
        RECT  60.396 46.512 60.48 46.536 ;
    END
  END b_data[79]
  PIN b_data[7]
    DIRECTION OUTPUT ;
    USE SIGNAL ;
    PORT
      LAYER M4 ;
        RECT  60.396 40.752 60.48 40.776 ;
    END
  END b_data[7]
  PIN b_data[80]
    DIRECTION OUTPUT ;
    USE SIGNAL ;
    PORT
      LAYER M4 ;
        RECT  60.396 46.656 60.48 46.68 ;
    END
  END b_data[80]
  PIN b_data[81]
    DIRECTION OUTPUT ;
    USE SIGNAL ;
    PORT
      LAYER M4 ;
        RECT  60.396 46.8 60.48 46.824 ;
    END
  END b_data[81]
  PIN b_data[82]
    DIRECTION OUTPUT ;
    USE SIGNAL ;
    PORT
      LAYER M4 ;
        RECT  60.396 46.944 60.48 46.968 ;
    END
  END b_data[82]
  PIN b_data[83]
    DIRECTION OUTPUT ;
    USE SIGNAL ;
    PORT
      LAYER M4 ;
        RECT  60.396 47.088 60.48 47.112 ;
    END
  END b_data[83]
  PIN b_data[84]
    DIRECTION OUTPUT ;
    USE SIGNAL ;
    PORT
      LAYER M4 ;
        RECT  60.396 47.232 60.48 47.256 ;
    END
  END b_data[84]
  PIN b_data[85]
    DIRECTION OUTPUT ;
    USE SIGNAL ;
    PORT
      LAYER M4 ;
        RECT  60.396 47.376 60.48 47.4 ;
    END
  END b_data[85]
  PIN b_data[86]
    DIRECTION OUTPUT ;
    USE SIGNAL ;
    PORT
      LAYER M4 ;
        RECT  60.396 47.52 60.48 47.544 ;
    END
  END b_data[86]
  PIN b_data[87]
    DIRECTION OUTPUT ;
    USE SIGNAL ;
    PORT
      LAYER M4 ;
        RECT  60.396 47.664 60.48 47.688 ;
    END
  END b_data[87]
  PIN b_data[88]
    DIRECTION OUTPUT ;
    USE SIGNAL ;
    PORT
      LAYER M4 ;
        RECT  60.396 47.808 60.48 47.832 ;
    END
  END b_data[88]
  PIN b_data[89]
    DIRECTION OUTPUT ;
    USE SIGNAL ;
    PORT
      LAYER M4 ;
        RECT  60.396 52.56 60.48 52.584 ;
    END
  END b_data[89]
  PIN b_data[8]
    DIRECTION OUTPUT ;
    USE SIGNAL ;
    PORT
      LAYER M4 ;
        RECT  60.396 40.896 60.48 40.92 ;
    END
  END b_data[8]
  PIN b_data[90]
    DIRECTION OUTPUT ;
    USE SIGNAL ;
    PORT
      LAYER M4 ;
        RECT  60.396 52.704 60.48 52.728 ;
    END
  END b_data[90]
  PIN b_data[91]
    DIRECTION OUTPUT ;
    USE SIGNAL ;
    PORT
      LAYER M4 ;
        RECT  60.396 52.848 60.48 52.872 ;
    END
  END b_data[91]
  PIN b_data[92]
    DIRECTION OUTPUT ;
    USE SIGNAL ;
    PORT
      LAYER M4 ;
        RECT  60.396 52.992 60.48 53.016 ;
    END
  END b_data[92]
  PIN b_data[93]
    DIRECTION OUTPUT ;
    USE SIGNAL ;
    PORT
      LAYER M4 ;
        RECT  60.396 53.136 60.48 53.16 ;
    END
  END b_data[93]
  PIN b_data[94]
    DIRECTION OUTPUT ;
    USE SIGNAL ;
    PORT
      LAYER M4 ;
        RECT  60.396 53.28 60.48 53.304 ;
    END
  END b_data[94]
  PIN b_data[95]
    DIRECTION OUTPUT ;
    USE SIGNAL ;
    PORT
      LAYER M4 ;
        RECT  60.396 53.424 60.48 53.448 ;
    END
  END b_data[95]
  PIN b_data[96]
    DIRECTION OUTPUT ;
    USE SIGNAL ;
    PORT
      LAYER M4 ;
        RECT  60.396 53.568 60.48 53.592 ;
    END
  END b_data[96]
  PIN b_data[97]
    DIRECTION OUTPUT ;
    USE SIGNAL ;
    PORT
      LAYER M4 ;
        RECT  60.396 53.712 60.48 53.736 ;
    END
  END b_data[97]
  PIN b_data[98]
    DIRECTION OUTPUT ;
    USE SIGNAL ;
    PORT
      LAYER M4 ;
        RECT  60.396 53.856 60.48 53.88 ;
    END
  END b_data[98]
  PIN b_data[99]
    DIRECTION OUTPUT ;
    USE SIGNAL ;
    PORT
      LAYER M4 ;
        RECT  60.396 54 60.48 54.024 ;
    END
  END b_data[99]
  PIN b_data[9]
    DIRECTION OUTPUT ;
    USE SIGNAL ;
    PORT
      LAYER M4 ;
        RECT  60.396 41.04 60.48 41.064 ;
    END
  END b_data[9]
  PIN b_we
    DIRECTION OUTPUT ;
    USE SIGNAL ;
    PORT
      LAYER M4 ;
        RECT  60.396 29.376 60.48 29.4 ;
    END
  END b_we
  PIN cfg_addr[0]
    DIRECTION INPUT ;
    USE SIGNAL ;
    PORT
      LAYER M5 ;
        RECT  26.496 60.396 26.52 60.48 ;
    END
  END cfg_addr[0]
  PIN cfg_addr[10]
    DIRECTION INPUT ;
    USE SIGNAL ;
    PORT
      LAYER M5 ;
        RECT  27.936 60.396 27.96 60.48 ;
    END
  END cfg_addr[10]
  PIN cfg_addr[11]
    DIRECTION INPUT ;
    USE SIGNAL ;
    PORT
      LAYER M5 ;
        RECT  28.08 60.396 28.104 60.48 ;
    END
  END cfg_addr[11]
  PIN cfg_addr[1]
    DIRECTION INPUT ;
    USE SIGNAL ;
    PORT
      LAYER M5 ;
        RECT  26.64 60.396 26.664 60.48 ;
    END
  END cfg_addr[1]
  PIN cfg_addr[2]
    DIRECTION INPUT ;
    USE SIGNAL ;
    PORT
      LAYER M5 ;
        RECT  26.784 60.396 26.808 60.48 ;
    END
  END cfg_addr[2]
  PIN cfg_addr[3]
    DIRECTION INPUT ;
    USE SIGNAL ;
    PORT
      LAYER M5 ;
        RECT  26.928 60.396 26.952 60.48 ;
    END
  END cfg_addr[3]
  PIN cfg_addr[4]
    DIRECTION INPUT ;
    USE SIGNAL ;
    PORT
      LAYER M5 ;
        RECT  27.072 60.396 27.096 60.48 ;
    END
  END cfg_addr[4]
  PIN cfg_addr[5]
    DIRECTION INPUT ;
    USE SIGNAL ;
    PORT
      LAYER M5 ;
        RECT  27.216 60.396 27.24 60.48 ;
    END
  END cfg_addr[5]
  PIN cfg_addr[6]
    DIRECTION INPUT ;
    USE SIGNAL ;
    PORT
      LAYER M5 ;
        RECT  27.36 60.396 27.384 60.48 ;
    END
  END cfg_addr[6]
  PIN cfg_addr[7]
    DIRECTION INPUT ;
    USE SIGNAL ;
    PORT
      LAYER M5 ;
        RECT  27.504 60.396 27.528 60.48 ;
    END
  END cfg_addr[7]
  PIN cfg_addr[8]
    DIRECTION INPUT ;
    USE SIGNAL ;
    PORT
      LAYER M5 ;
        RECT  27.648 60.396 27.672 60.48 ;
    END
  END cfg_addr[8]
  PIN cfg_addr[9]
    DIRECTION INPUT ;
    USE SIGNAL ;
    PORT
      LAYER M5 ;
        RECT  27.792 60.396 27.816 60.48 ;
    END
  END cfg_addr[9]
  PIN cfg_data[0]
    DIRECTION INPUT ;
    USE SIGNAL ;
    PORT
      LAYER M5 ;
        RECT  28.224 60.396 28.248 60.48 ;
    END
  END cfg_data[0]
  PIN cfg_data[100]
    DIRECTION INPUT ;
    USE SIGNAL ;
    PORT
      LAYER M5 ;
        RECT  24.192 60.396 24.216 60.48 ;
    END
  END cfg_data[100]
  PIN cfg_data[101]
    DIRECTION INPUT ;
    USE SIGNAL ;
    PORT
      LAYER M5 ;
        RECT  24.336 60.396 24.36 60.48 ;
    END
  END cfg_data[101]
  PIN cfg_data[102]
    DIRECTION INPUT ;
    USE SIGNAL ;
    PORT
      LAYER M5 ;
        RECT  24.48 60.396 24.504 60.48 ;
    END
  END cfg_data[102]
  PIN cfg_data[103]
    DIRECTION INPUT ;
    USE SIGNAL ;
    PORT
      LAYER M5 ;
        RECT  24.624 60.396 24.648 60.48 ;
    END
  END cfg_data[103]
  PIN cfg_data[104]
    DIRECTION INPUT ;
    USE SIGNAL ;
    PORT
      LAYER M5 ;
        RECT  24.768 60.396 24.792 60.48 ;
    END
  END cfg_data[104]
  PIN cfg_data[105]
    DIRECTION INPUT ;
    USE SIGNAL ;
    PORT
      LAYER M5 ;
        RECT  24.912 60.396 24.936 60.48 ;
    END
  END cfg_data[105]
  PIN cfg_data[106]
    DIRECTION INPUT ;
    USE SIGNAL ;
    PORT
      LAYER M5 ;
        RECT  25.056 60.396 25.08 60.48 ;
    END
  END cfg_data[106]
  PIN cfg_data[107]
    DIRECTION INPUT ;
    USE SIGNAL ;
    PORT
      LAYER M5 ;
        RECT  25.2 60.396 25.224 60.48 ;
    END
  END cfg_data[107]
  PIN cfg_data[108]
    DIRECTION INPUT ;
    USE SIGNAL ;
    PORT
      LAYER M5 ;
        RECT  25.344 60.396 25.368 60.48 ;
    END
  END cfg_data[108]
  PIN cfg_data[109]
    DIRECTION INPUT ;
    USE SIGNAL ;
    PORT
      LAYER M5 ;
        RECT  25.488 60.396 25.512 60.48 ;
    END
  END cfg_data[109]
  PIN cfg_data[10]
    DIRECTION INPUT ;
    USE SIGNAL ;
    PORT
      LAYER M5 ;
        RECT  29.664 60.396 29.688 60.48 ;
    END
  END cfg_data[10]
  PIN cfg_data[110]
    DIRECTION INPUT ;
    USE SIGNAL ;
    PORT
      LAYER M5 ;
        RECT  25.632 60.396 25.656 60.48 ;
    END
  END cfg_data[110]
  PIN cfg_data[111]
    DIRECTION INPUT ;
    USE SIGNAL ;
    PORT
      LAYER M5 ;
        RECT  25.776 60.396 25.8 60.48 ;
    END
  END cfg_data[111]
  PIN cfg_data[112]
    DIRECTION INPUT ;
    USE SIGNAL ;
    PORT
      LAYER M5 ;
        RECT  25.92 60.396 25.944 60.48 ;
    END
  END cfg_data[112]
  PIN cfg_data[113]
    DIRECTION INPUT ;
    USE SIGNAL ;
    PORT
      LAYER M5 ;
        RECT  26.064 60.396 26.088 60.48 ;
    END
  END cfg_data[113]
  PIN cfg_data[114]
    DIRECTION INPUT ;
    USE SIGNAL ;
    PORT
      LAYER M5 ;
        RECT  26.208 60.396 26.232 60.48 ;
    END
  END cfg_data[114]
  PIN cfg_data[115]
    DIRECTION INPUT ;
    USE SIGNAL ;
    PORT
      LAYER M5 ;
        RECT  50.544 60.396 50.568 60.48 ;
    END
  END cfg_data[115]
  PIN cfg_data[116]
    DIRECTION INPUT ;
    USE SIGNAL ;
    PORT
      LAYER M5 ;
        RECT  50.688 60.396 50.712 60.48 ;
    END
  END cfg_data[116]
  PIN cfg_data[117]
    DIRECTION INPUT ;
    USE SIGNAL ;
    PORT
      LAYER M5 ;
        RECT  50.832 60.396 50.856 60.48 ;
    END
  END cfg_data[117]
  PIN cfg_data[118]
    DIRECTION INPUT ;
    USE SIGNAL ;
    PORT
      LAYER M5 ;
        RECT  50.976 60.396 51 60.48 ;
    END
  END cfg_data[118]
  PIN cfg_data[119]
    DIRECTION INPUT ;
    USE SIGNAL ;
    PORT
      LAYER M5 ;
        RECT  51.12 60.396 51.144 60.48 ;
    END
  END cfg_data[119]
  PIN cfg_data[11]
    DIRECTION INPUT ;
    USE SIGNAL ;
    PORT
      LAYER M5 ;
        RECT  29.808 60.396 29.832 60.48 ;
    END
  END cfg_data[11]
  PIN cfg_data[120]
    DIRECTION INPUT ;
    USE SIGNAL ;
    PORT
      LAYER M5 ;
        RECT  51.264 60.396 51.288 60.48 ;
    END
  END cfg_data[120]
  PIN cfg_data[121]
    DIRECTION INPUT ;
    USE SIGNAL ;
    PORT
      LAYER M5 ;
        RECT  51.408 60.396 51.432 60.48 ;
    END
  END cfg_data[121]
  PIN cfg_data[122]
    DIRECTION INPUT ;
    USE SIGNAL ;
    PORT
      LAYER M5 ;
        RECT  51.552 60.396 51.576 60.48 ;
    END
  END cfg_data[122]
  PIN cfg_data[123]
    DIRECTION INPUT ;
    USE SIGNAL ;
    PORT
      LAYER M5 ;
        RECT  51.696 60.396 51.72 60.48 ;
    END
  END cfg_data[123]
  PIN cfg_data[124]
    DIRECTION INPUT ;
    USE SIGNAL ;
    PORT
      LAYER M5 ;
        RECT  51.84 60.396 51.864 60.48 ;
    END
  END cfg_data[124]
  PIN cfg_data[125]
    DIRECTION INPUT ;
    USE SIGNAL ;
    PORT
      LAYER M5 ;
        RECT  51.984 60.396 52.008 60.48 ;
    END
  END cfg_data[125]
  PIN cfg_data[126]
    DIRECTION INPUT ;
    USE SIGNAL ;
    PORT
      LAYER M5 ;
        RECT  52.128 60.396 52.152 60.48 ;
    END
  END cfg_data[126]
  PIN cfg_data[127]
    DIRECTION INPUT ;
    USE SIGNAL ;
    PORT
      LAYER M5 ;
        RECT  52.272 60.396 52.296 60.48 ;
    END
  END cfg_data[127]
  PIN cfg_data[128]
    DIRECTION INPUT ;
    USE SIGNAL ;
    PORT
      LAYER M5 ;
        RECT  52.416 60.396 52.44 60.48 ;
    END
  END cfg_data[128]
  PIN cfg_data[129]
    DIRECTION INPUT ;
    USE SIGNAL ;
    PORT
      LAYER M5 ;
        RECT  52.56 60.396 52.584 60.48 ;
    END
  END cfg_data[129]
  PIN cfg_data[12]
    DIRECTION INPUT ;
    USE SIGNAL ;
    PORT
      LAYER M5 ;
        RECT  29.952 60.396 29.976 60.48 ;
    END
  END cfg_data[12]
  PIN cfg_data[130]
    DIRECTION INPUT ;
    USE SIGNAL ;
    PORT
      LAYER M5 ;
        RECT  52.704 60.396 52.728 60.48 ;
    END
  END cfg_data[130]
  PIN cfg_data[131]
    DIRECTION INPUT ;
    USE SIGNAL ;
    PORT
      LAYER M5 ;
        RECT  52.848 60.396 52.872 60.48 ;
    END
  END cfg_data[131]
  PIN cfg_data[132]
    DIRECTION INPUT ;
    USE SIGNAL ;
    PORT
      LAYER M5 ;
        RECT  52.992 60.396 53.016 60.48 ;
    END
  END cfg_data[132]
  PIN cfg_data[133]
    DIRECTION INPUT ;
    USE SIGNAL ;
    PORT
      LAYER M5 ;
        RECT  53.136 60.396 53.16 60.48 ;
    END
  END cfg_data[133]
  PIN cfg_data[134]
    DIRECTION INPUT ;
    USE SIGNAL ;
    PORT
      LAYER M5 ;
        RECT  53.28 60.396 53.304 60.48 ;
    END
  END cfg_data[134]
  PIN cfg_data[135]
    DIRECTION INPUT ;
    USE SIGNAL ;
    PORT
      LAYER M5 ;
        RECT  53.424 60.396 53.448 60.48 ;
    END
  END cfg_data[135]
  PIN cfg_data[136]
    DIRECTION INPUT ;
    USE SIGNAL ;
    PORT
      LAYER M5 ;
        RECT  53.568 60.396 53.592 60.48 ;
    END
  END cfg_data[136]
  PIN cfg_data[137]
    DIRECTION INPUT ;
    USE SIGNAL ;
    PORT
      LAYER M5 ;
        RECT  53.712 60.396 53.736 60.48 ;
    END
  END cfg_data[137]
  PIN cfg_data[138]
    DIRECTION INPUT ;
    USE SIGNAL ;
    PORT
      LAYER M5 ;
        RECT  53.856 60.396 53.88 60.48 ;
    END
  END cfg_data[138]
  PIN cfg_data[139]
    DIRECTION INPUT ;
    USE SIGNAL ;
    PORT
      LAYER M5 ;
        RECT  54 60.396 54.024 60.48 ;
    END
  END cfg_data[139]
  PIN cfg_data[13]
    DIRECTION INPUT ;
    USE SIGNAL ;
    PORT
      LAYER M5 ;
        RECT  30.096 60.396 30.12 60.48 ;
    END
  END cfg_data[13]
  PIN cfg_data[140]
    DIRECTION INPUT ;
    USE SIGNAL ;
    PORT
      LAYER M5 ;
        RECT  54.144 60.396 54.168 60.48 ;
    END
  END cfg_data[140]
  PIN cfg_data[141]
    DIRECTION INPUT ;
    USE SIGNAL ;
    PORT
      LAYER M5 ;
        RECT  54.288 60.396 54.312 60.48 ;
    END
  END cfg_data[141]
  PIN cfg_data[142]
    DIRECTION INPUT ;
    USE SIGNAL ;
    PORT
      LAYER M5 ;
        RECT  54.432 60.396 54.456 60.48 ;
    END
  END cfg_data[142]
  PIN cfg_data[143]
    DIRECTION INPUT ;
    USE SIGNAL ;
    PORT
      LAYER M5 ;
        RECT  54.576 60.396 54.6 60.48 ;
    END
  END cfg_data[143]
  PIN cfg_data[144]
    DIRECTION INPUT ;
    USE SIGNAL ;
    PORT
      LAYER M5 ;
        RECT  54.72 60.396 54.744 60.48 ;
    END
  END cfg_data[144]
  PIN cfg_data[145]
    DIRECTION INPUT ;
    USE SIGNAL ;
    PORT
      LAYER M5 ;
        RECT  54.864 60.396 54.888 60.48 ;
    END
  END cfg_data[145]
  PIN cfg_data[146]
    DIRECTION INPUT ;
    USE SIGNAL ;
    PORT
      LAYER M5 ;
        RECT  55.008 60.396 55.032 60.48 ;
    END
  END cfg_data[146]
  PIN cfg_data[147]
    DIRECTION INPUT ;
    USE SIGNAL ;
    PORT
      LAYER M5 ;
        RECT  41.328 60.396 41.352 60.48 ;
    END
  END cfg_data[147]
  PIN cfg_data[148]
    DIRECTION INPUT ;
    USE SIGNAL ;
    PORT
      LAYER M5 ;
        RECT  41.472 60.396 41.496 60.48 ;
    END
  END cfg_data[148]
  PIN cfg_data[149]
    DIRECTION INPUT ;
    USE SIGNAL ;
    PORT
      LAYER M5 ;
        RECT  41.616 60.396 41.64 60.48 ;
    END
  END cfg_data[149]
  PIN cfg_data[14]
    DIRECTION INPUT ;
    USE SIGNAL ;
    PORT
      LAYER M5 ;
        RECT  30.24 60.396 30.264 60.48 ;
    END
  END cfg_data[14]
  PIN cfg_data[150]
    DIRECTION INPUT ;
    USE SIGNAL ;
    PORT
      LAYER M5 ;
        RECT  41.76 60.396 41.784 60.48 ;
    END
  END cfg_data[150]
  PIN cfg_data[151]
    DIRECTION INPUT ;
    USE SIGNAL ;
    PORT
      LAYER M5 ;
        RECT  41.904 60.396 41.928 60.48 ;
    END
  END cfg_data[151]
  PIN cfg_data[152]
    DIRECTION INPUT ;
    USE SIGNAL ;
    PORT
      LAYER M5 ;
        RECT  42.048 60.396 42.072 60.48 ;
    END
  END cfg_data[152]
  PIN cfg_data[153]
    DIRECTION INPUT ;
    USE SIGNAL ;
    PORT
      LAYER M5 ;
        RECT  42.192 60.396 42.216 60.48 ;
    END
  END cfg_data[153]
  PIN cfg_data[154]
    DIRECTION INPUT ;
    USE SIGNAL ;
    PORT
      LAYER M5 ;
        RECT  42.336 60.396 42.36 60.48 ;
    END
  END cfg_data[154]
  PIN cfg_data[155]
    DIRECTION INPUT ;
    USE SIGNAL ;
    PORT
      LAYER M5 ;
        RECT  42.48 60.396 42.504 60.48 ;
    END
  END cfg_data[155]
  PIN cfg_data[156]
    DIRECTION INPUT ;
    USE SIGNAL ;
    PORT
      LAYER M5 ;
        RECT  42.624 60.396 42.648 60.48 ;
    END
  END cfg_data[156]
  PIN cfg_data[157]
    DIRECTION INPUT ;
    USE SIGNAL ;
    PORT
      LAYER M5 ;
        RECT  42.768 60.396 42.792 60.48 ;
    END
  END cfg_data[157]
  PIN cfg_data[158]
    DIRECTION INPUT ;
    USE SIGNAL ;
    PORT
      LAYER M5 ;
        RECT  42.912 60.396 42.936 60.48 ;
    END
  END cfg_data[158]
  PIN cfg_data[159]
    DIRECTION INPUT ;
    USE SIGNAL ;
    PORT
      LAYER M5 ;
        RECT  43.056 60.396 43.08 60.48 ;
    END
  END cfg_data[159]
  PIN cfg_data[15]
    DIRECTION INPUT ;
    USE SIGNAL ;
    PORT
      LAYER M5 ;
        RECT  30.384 60.396 30.408 60.48 ;
    END
  END cfg_data[15]
  PIN cfg_data[160]
    DIRECTION INPUT ;
    USE SIGNAL ;
    PORT
      LAYER M5 ;
        RECT  43.2 60.396 43.224 60.48 ;
    END
  END cfg_data[160]
  PIN cfg_data[161]
    DIRECTION INPUT ;
    USE SIGNAL ;
    PORT
      LAYER M5 ;
        RECT  43.344 60.396 43.368 60.48 ;
    END
  END cfg_data[161]
  PIN cfg_data[162]
    DIRECTION INPUT ;
    USE SIGNAL ;
    PORT
      LAYER M5 ;
        RECT  43.488 60.396 43.512 60.48 ;
    END
  END cfg_data[162]
  PIN cfg_data[163]
    DIRECTION INPUT ;
    USE SIGNAL ;
    PORT
      LAYER M5 ;
        RECT  43.632 60.396 43.656 60.48 ;
    END
  END cfg_data[163]
  PIN cfg_data[164]
    DIRECTION INPUT ;
    USE SIGNAL ;
    PORT
      LAYER M5 ;
        RECT  43.776 60.396 43.8 60.48 ;
    END
  END cfg_data[164]
  PIN cfg_data[165]
    DIRECTION INPUT ;
    USE SIGNAL ;
    PORT
      LAYER M5 ;
        RECT  43.92 60.396 43.944 60.48 ;
    END
  END cfg_data[165]
  PIN cfg_data[166]
    DIRECTION INPUT ;
    USE SIGNAL ;
    PORT
      LAYER M5 ;
        RECT  44.064 60.396 44.088 60.48 ;
    END
  END cfg_data[166]
  PIN cfg_data[167]
    DIRECTION INPUT ;
    USE SIGNAL ;
    PORT
      LAYER M5 ;
        RECT  44.208 60.396 44.232 60.48 ;
    END
  END cfg_data[167]
  PIN cfg_data[168]
    DIRECTION INPUT ;
    USE SIGNAL ;
    PORT
      LAYER M5 ;
        RECT  44.352 60.396 44.376 60.48 ;
    END
  END cfg_data[168]
  PIN cfg_data[169]
    DIRECTION INPUT ;
    USE SIGNAL ;
    PORT
      LAYER M5 ;
        RECT  44.496 60.396 44.52 60.48 ;
    END
  END cfg_data[169]
  PIN cfg_data[16]
    DIRECTION INPUT ;
    USE SIGNAL ;
    PORT
      LAYER M5 ;
        RECT  30.528 60.396 30.552 60.48 ;
    END
  END cfg_data[16]
  PIN cfg_data[170]
    DIRECTION INPUT ;
    USE SIGNAL ;
    PORT
      LAYER M5 ;
        RECT  44.64 60.396 44.664 60.48 ;
    END
  END cfg_data[170]
  PIN cfg_data[171]
    DIRECTION INPUT ;
    USE SIGNAL ;
    PORT
      LAYER M5 ;
        RECT  44.784 60.396 44.808 60.48 ;
    END
  END cfg_data[171]
  PIN cfg_data[172]
    DIRECTION INPUT ;
    USE SIGNAL ;
    PORT
      LAYER M5 ;
        RECT  44.928 60.396 44.952 60.48 ;
    END
  END cfg_data[172]
  PIN cfg_data[173]
    DIRECTION INPUT ;
    USE SIGNAL ;
    PORT
      LAYER M5 ;
        RECT  45.072 60.396 45.096 60.48 ;
    END
  END cfg_data[173]
  PIN cfg_data[174]
    DIRECTION INPUT ;
    USE SIGNAL ;
    PORT
      LAYER M5 ;
        RECT  45.216 60.396 45.24 60.48 ;
    END
  END cfg_data[174]
  PIN cfg_data[175]
    DIRECTION INPUT ;
    USE SIGNAL ;
    PORT
      LAYER M5 ;
        RECT  45.36 60.396 45.384 60.48 ;
    END
  END cfg_data[175]
  PIN cfg_data[176]
    DIRECTION INPUT ;
    USE SIGNAL ;
    PORT
      LAYER M5 ;
        RECT  45.504 60.396 45.528 60.48 ;
    END
  END cfg_data[176]
  PIN cfg_data[177]
    DIRECTION INPUT ;
    USE SIGNAL ;
    PORT
      LAYER M5 ;
        RECT  45.648 60.396 45.672 60.48 ;
    END
  END cfg_data[177]
  PIN cfg_data[178]
    DIRECTION INPUT ;
    USE SIGNAL ;
    PORT
      LAYER M5 ;
        RECT  45.792 60.396 45.816 60.48 ;
    END
  END cfg_data[178]
  PIN cfg_data[179]
    DIRECTION INPUT ;
    USE SIGNAL ;
    PORT
      LAYER M5 ;
        RECT  45.936 60.396 45.96 60.48 ;
    END
  END cfg_data[179]
  PIN cfg_data[17]
    DIRECTION INPUT ;
    USE SIGNAL ;
    PORT
      LAYER M5 ;
        RECT  30.672 60.396 30.696 60.48 ;
    END
  END cfg_data[17]
  PIN cfg_data[180]
    DIRECTION INPUT ;
    USE SIGNAL ;
    PORT
      LAYER M5 ;
        RECT  46.08 60.396 46.104 60.48 ;
    END
  END cfg_data[180]
  PIN cfg_data[181]
    DIRECTION INPUT ;
    USE SIGNAL ;
    PORT
      LAYER M5 ;
        RECT  46.224 60.396 46.248 60.48 ;
    END
  END cfg_data[181]
  PIN cfg_data[182]
    DIRECTION INPUT ;
    USE SIGNAL ;
    PORT
      LAYER M5 ;
        RECT  46.368 60.396 46.392 60.48 ;
    END
  END cfg_data[182]
  PIN cfg_data[183]
    DIRECTION INPUT ;
    USE SIGNAL ;
    PORT
      LAYER M5 ;
        RECT  46.512 60.396 46.536 60.48 ;
    END
  END cfg_data[183]
  PIN cfg_data[184]
    DIRECTION INPUT ;
    USE SIGNAL ;
    PORT
      LAYER M5 ;
        RECT  46.656 60.396 46.68 60.48 ;
    END
  END cfg_data[184]
  PIN cfg_data[185]
    DIRECTION INPUT ;
    USE SIGNAL ;
    PORT
      LAYER M5 ;
        RECT  46.8 60.396 46.824 60.48 ;
    END
  END cfg_data[185]
  PIN cfg_data[186]
    DIRECTION INPUT ;
    USE SIGNAL ;
    PORT
      LAYER M5 ;
        RECT  46.944 60.396 46.968 60.48 ;
    END
  END cfg_data[186]
  PIN cfg_data[187]
    DIRECTION INPUT ;
    USE SIGNAL ;
    PORT
      LAYER M5 ;
        RECT  47.088 60.396 47.112 60.48 ;
    END
  END cfg_data[187]
  PIN cfg_data[188]
    DIRECTION INPUT ;
    USE SIGNAL ;
    PORT
      LAYER M5 ;
        RECT  47.232 60.396 47.256 60.48 ;
    END
  END cfg_data[188]
  PIN cfg_data[189]
    DIRECTION INPUT ;
    USE SIGNAL ;
    PORT
      LAYER M5 ;
        RECT  47.376 60.396 47.4 60.48 ;
    END
  END cfg_data[189]
  PIN cfg_data[18]
    DIRECTION INPUT ;
    USE SIGNAL ;
    PORT
      LAYER M5 ;
        RECT  30.816 60.396 30.84 60.48 ;
    END
  END cfg_data[18]
  PIN cfg_data[190]
    DIRECTION INPUT ;
    USE SIGNAL ;
    PORT
      LAYER M5 ;
        RECT  47.52 60.396 47.544 60.48 ;
    END
  END cfg_data[190]
  PIN cfg_data[191]
    DIRECTION INPUT ;
    USE SIGNAL ;
    PORT
      LAYER M5 ;
        RECT  47.664 60.396 47.688 60.48 ;
    END
  END cfg_data[191]
  PIN cfg_data[192]
    DIRECTION INPUT ;
    USE SIGNAL ;
    PORT
      LAYER M5 ;
        RECT  47.808 60.396 47.832 60.48 ;
    END
  END cfg_data[192]
  PIN cfg_data[193]
    DIRECTION INPUT ;
    USE SIGNAL ;
    PORT
      LAYER M5 ;
        RECT  47.952 60.396 47.976 60.48 ;
    END
  END cfg_data[193]
  PIN cfg_data[194]
    DIRECTION INPUT ;
    USE SIGNAL ;
    PORT
      LAYER M5 ;
        RECT  48.096 60.396 48.12 60.48 ;
    END
  END cfg_data[194]
  PIN cfg_data[195]
    DIRECTION INPUT ;
    USE SIGNAL ;
    PORT
      LAYER M5 ;
        RECT  48.24 60.396 48.264 60.48 ;
    END
  END cfg_data[195]
  PIN cfg_data[196]
    DIRECTION INPUT ;
    USE SIGNAL ;
    PORT
      LAYER M5 ;
        RECT  48.384 60.396 48.408 60.48 ;
    END
  END cfg_data[196]
  PIN cfg_data[197]
    DIRECTION INPUT ;
    USE SIGNAL ;
    PORT
      LAYER M5 ;
        RECT  48.528 60.396 48.552 60.48 ;
    END
  END cfg_data[197]
  PIN cfg_data[198]
    DIRECTION INPUT ;
    USE SIGNAL ;
    PORT
      LAYER M5 ;
        RECT  48.672 60.396 48.696 60.48 ;
    END
  END cfg_data[198]
  PIN cfg_data[199]
    DIRECTION INPUT ;
    USE SIGNAL ;
    PORT
      LAYER M5 ;
        RECT  48.816 60.396 48.84 60.48 ;
    END
  END cfg_data[199]
  PIN cfg_data[19]
    DIRECTION INPUT ;
    USE SIGNAL ;
    PORT
      LAYER M5 ;
        RECT  17.136 60.396 17.16 60.48 ;
    END
  END cfg_data[19]
  PIN cfg_data[1]
    DIRECTION INPUT ;
    USE SIGNAL ;
    PORT
      LAYER M5 ;
        RECT  28.368 60.396 28.392 60.48 ;
    END
  END cfg_data[1]
  PIN cfg_data[200]
    DIRECTION INPUT ;
    USE SIGNAL ;
    PORT
      LAYER M5 ;
        RECT  48.96 60.396 48.984 60.48 ;
    END
  END cfg_data[200]
  PIN cfg_data[201]
    DIRECTION INPUT ;
    USE SIGNAL ;
    PORT
      LAYER M5 ;
        RECT  49.104 60.396 49.128 60.48 ;
    END
  END cfg_data[201]
  PIN cfg_data[202]
    DIRECTION INPUT ;
    USE SIGNAL ;
    PORT
      LAYER M5 ;
        RECT  49.248 60.396 49.272 60.48 ;
    END
  END cfg_data[202]
  PIN cfg_data[203]
    DIRECTION INPUT ;
    USE SIGNAL ;
    PORT
      LAYER M5 ;
        RECT  49.392 60.396 49.416 60.48 ;
    END
  END cfg_data[203]
  PIN cfg_data[204]
    DIRECTION INPUT ;
    USE SIGNAL ;
    PORT
      LAYER M5 ;
        RECT  49.536 60.396 49.56 60.48 ;
    END
  END cfg_data[204]
  PIN cfg_data[205]
    DIRECTION INPUT ;
    USE SIGNAL ;
    PORT
      LAYER M5 ;
        RECT  49.68 60.396 49.704 60.48 ;
    END
  END cfg_data[205]
  PIN cfg_data[206]
    DIRECTION INPUT ;
    USE SIGNAL ;
    PORT
      LAYER M5 ;
        RECT  49.824 60.396 49.848 60.48 ;
    END
  END cfg_data[206]
  PIN cfg_data[207]
    DIRECTION INPUT ;
    USE SIGNAL ;
    PORT
      LAYER M5 ;
        RECT  49.968 60.396 49.992 60.48 ;
    END
  END cfg_data[207]
  PIN cfg_data[208]
    DIRECTION INPUT ;
    USE SIGNAL ;
    PORT
      LAYER M5 ;
        RECT  50.112 60.396 50.136 60.48 ;
    END
  END cfg_data[208]
  PIN cfg_data[209]
    DIRECTION INPUT ;
    USE SIGNAL ;
    PORT
      LAYER M5 ;
        RECT  50.256 60.396 50.28 60.48 ;
    END
  END cfg_data[209]
  PIN cfg_data[20]
    DIRECTION INPUT ;
    USE SIGNAL ;
    PORT
      LAYER M5 ;
        RECT  17.28 60.396 17.304 60.48 ;
    END
  END cfg_data[20]
  PIN cfg_data[210]
    DIRECTION INPUT ;
    USE SIGNAL ;
    PORT
      LAYER M5 ;
        RECT  50.4 60.396 50.424 60.48 ;
    END
  END cfg_data[210]
  PIN cfg_data[211]
    DIRECTION INPUT ;
    USE SIGNAL ;
    PORT
      LAYER M5 ;
        RECT  32.112 60.396 32.136 60.48 ;
    END
  END cfg_data[211]
  PIN cfg_data[212]
    DIRECTION INPUT ;
    USE SIGNAL ;
    PORT
      LAYER M5 ;
        RECT  32.256 60.396 32.28 60.48 ;
    END
  END cfg_data[212]
  PIN cfg_data[213]
    DIRECTION INPUT ;
    USE SIGNAL ;
    PORT
      LAYER M5 ;
        RECT  32.4 60.396 32.424 60.48 ;
    END
  END cfg_data[213]
  PIN cfg_data[214]
    DIRECTION INPUT ;
    USE SIGNAL ;
    PORT
      LAYER M5 ;
        RECT  32.544 60.396 32.568 60.48 ;
    END
  END cfg_data[214]
  PIN cfg_data[215]
    DIRECTION INPUT ;
    USE SIGNAL ;
    PORT
      LAYER M5 ;
        RECT  32.688 60.396 32.712 60.48 ;
    END
  END cfg_data[215]
  PIN cfg_data[216]
    DIRECTION INPUT ;
    USE SIGNAL ;
    PORT
      LAYER M5 ;
        RECT  32.832 60.396 32.856 60.48 ;
    END
  END cfg_data[216]
  PIN cfg_data[217]
    DIRECTION INPUT ;
    USE SIGNAL ;
    PORT
      LAYER M5 ;
        RECT  32.976 60.396 33 60.48 ;
    END
  END cfg_data[217]
  PIN cfg_data[218]
    DIRECTION INPUT ;
    USE SIGNAL ;
    PORT
      LAYER M5 ;
        RECT  33.12 60.396 33.144 60.48 ;
    END
  END cfg_data[218]
  PIN cfg_data[219]
    DIRECTION INPUT ;
    USE SIGNAL ;
    PORT
      LAYER M5 ;
        RECT  33.264 60.396 33.288 60.48 ;
    END
  END cfg_data[219]
  PIN cfg_data[21]
    DIRECTION INPUT ;
    USE SIGNAL ;
    PORT
      LAYER M5 ;
        RECT  17.424 60.396 17.448 60.48 ;
    END
  END cfg_data[21]
  PIN cfg_data[220]
    DIRECTION INPUT ;
    USE SIGNAL ;
    PORT
      LAYER M5 ;
        RECT  33.408 60.396 33.432 60.48 ;
    END
  END cfg_data[220]
  PIN cfg_data[221]
    DIRECTION INPUT ;
    USE SIGNAL ;
    PORT
      LAYER M5 ;
        RECT  33.552 60.396 33.576 60.48 ;
    END
  END cfg_data[221]
  PIN cfg_data[222]
    DIRECTION INPUT ;
    USE SIGNAL ;
    PORT
      LAYER M5 ;
        RECT  33.696 60.396 33.72 60.48 ;
    END
  END cfg_data[222]
  PIN cfg_data[223]
    DIRECTION INPUT ;
    USE SIGNAL ;
    PORT
      LAYER M5 ;
        RECT  33.84 60.396 33.864 60.48 ;
    END
  END cfg_data[223]
  PIN cfg_data[224]
    DIRECTION INPUT ;
    USE SIGNAL ;
    PORT
      LAYER M5 ;
        RECT  33.984 60.396 34.008 60.48 ;
    END
  END cfg_data[224]
  PIN cfg_data[225]
    DIRECTION INPUT ;
    USE SIGNAL ;
    PORT
      LAYER M5 ;
        RECT  34.128 60.396 34.152 60.48 ;
    END
  END cfg_data[225]
  PIN cfg_data[226]
    DIRECTION INPUT ;
    USE SIGNAL ;
    PORT
      LAYER M5 ;
        RECT  34.272 60.396 34.296 60.48 ;
    END
  END cfg_data[226]
  PIN cfg_data[227]
    DIRECTION INPUT ;
    USE SIGNAL ;
    PORT
      LAYER M5 ;
        RECT  34.416 60.396 34.44 60.48 ;
    END
  END cfg_data[227]
  PIN cfg_data[228]
    DIRECTION INPUT ;
    USE SIGNAL ;
    PORT
      LAYER M5 ;
        RECT  34.56 60.396 34.584 60.48 ;
    END
  END cfg_data[228]
  PIN cfg_data[229]
    DIRECTION INPUT ;
    USE SIGNAL ;
    PORT
      LAYER M5 ;
        RECT  34.704 60.396 34.728 60.48 ;
    END
  END cfg_data[229]
  PIN cfg_data[22]
    DIRECTION INPUT ;
    USE SIGNAL ;
    PORT
      LAYER M5 ;
        RECT  17.568 60.396 17.592 60.48 ;
    END
  END cfg_data[22]
  PIN cfg_data[230]
    DIRECTION INPUT ;
    USE SIGNAL ;
    PORT
      LAYER M5 ;
        RECT  34.848 60.396 34.872 60.48 ;
    END
  END cfg_data[230]
  PIN cfg_data[231]
    DIRECTION INPUT ;
    USE SIGNAL ;
    PORT
      LAYER M5 ;
        RECT  34.992 60.396 35.016 60.48 ;
    END
  END cfg_data[231]
  PIN cfg_data[232]
    DIRECTION INPUT ;
    USE SIGNAL ;
    PORT
      LAYER M5 ;
        RECT  35.136 60.396 35.16 60.48 ;
    END
  END cfg_data[232]
  PIN cfg_data[233]
    DIRECTION INPUT ;
    USE SIGNAL ;
    PORT
      LAYER M5 ;
        RECT  35.28 60.396 35.304 60.48 ;
    END
  END cfg_data[233]
  PIN cfg_data[234]
    DIRECTION INPUT ;
    USE SIGNAL ;
    PORT
      LAYER M5 ;
        RECT  35.424 60.396 35.448 60.48 ;
    END
  END cfg_data[234]
  PIN cfg_data[235]
    DIRECTION INPUT ;
    USE SIGNAL ;
    PORT
      LAYER M5 ;
        RECT  35.568 60.396 35.592 60.48 ;
    END
  END cfg_data[235]
  PIN cfg_data[236]
    DIRECTION INPUT ;
    USE SIGNAL ;
    PORT
      LAYER M5 ;
        RECT  35.712 60.396 35.736 60.48 ;
    END
  END cfg_data[236]
  PIN cfg_data[237]
    DIRECTION INPUT ;
    USE SIGNAL ;
    PORT
      LAYER M5 ;
        RECT  35.856 60.396 35.88 60.48 ;
    END
  END cfg_data[237]
  PIN cfg_data[238]
    DIRECTION INPUT ;
    USE SIGNAL ;
    PORT
      LAYER M5 ;
        RECT  36 60.396 36.024 60.48 ;
    END
  END cfg_data[238]
  PIN cfg_data[239]
    DIRECTION INPUT ;
    USE SIGNAL ;
    PORT
      LAYER M5 ;
        RECT  36.144 60.396 36.168 60.48 ;
    END
  END cfg_data[239]
  PIN cfg_data[23]
    DIRECTION INPUT ;
    USE SIGNAL ;
    PORT
      LAYER M5 ;
        RECT  17.712 60.396 17.736 60.48 ;
    END
  END cfg_data[23]
  PIN cfg_data[240]
    DIRECTION INPUT ;
    USE SIGNAL ;
    PORT
      LAYER M5 ;
        RECT  36.288 60.396 36.312 60.48 ;
    END
  END cfg_data[240]
  PIN cfg_data[241]
    DIRECTION INPUT ;
    USE SIGNAL ;
    PORT
      LAYER M5 ;
        RECT  36.432 60.396 36.456 60.48 ;
    END
  END cfg_data[241]
  PIN cfg_data[242]
    DIRECTION INPUT ;
    USE SIGNAL ;
    PORT
      LAYER M5 ;
        RECT  36.576 60.396 36.6 60.48 ;
    END
  END cfg_data[242]
  PIN cfg_data[243]
    DIRECTION INPUT ;
    USE SIGNAL ;
    PORT
      LAYER M5 ;
        RECT  12.528 60.396 12.552 60.48 ;
    END
  END cfg_data[243]
  PIN cfg_data[244]
    DIRECTION INPUT ;
    USE SIGNAL ;
    PORT
      LAYER M5 ;
        RECT  12.672 60.396 12.696 60.48 ;
    END
  END cfg_data[244]
  PIN cfg_data[245]
    DIRECTION INPUT ;
    USE SIGNAL ;
    PORT
      LAYER M5 ;
        RECT  12.816 60.396 12.84 60.48 ;
    END
  END cfg_data[245]
  PIN cfg_data[246]
    DIRECTION INPUT ;
    USE SIGNAL ;
    PORT
      LAYER M5 ;
        RECT  12.96 60.396 12.984 60.48 ;
    END
  END cfg_data[246]
  PIN cfg_data[247]
    DIRECTION INPUT ;
    USE SIGNAL ;
    PORT
      LAYER M5 ;
        RECT  13.104 60.396 13.128 60.48 ;
    END
  END cfg_data[247]
  PIN cfg_data[248]
    DIRECTION INPUT ;
    USE SIGNAL ;
    PORT
      LAYER M5 ;
        RECT  13.248 60.396 13.272 60.48 ;
    END
  END cfg_data[248]
  PIN cfg_data[249]
    DIRECTION INPUT ;
    USE SIGNAL ;
    PORT
      LAYER M5 ;
        RECT  13.392 60.396 13.416 60.48 ;
    END
  END cfg_data[249]
  PIN cfg_data[24]
    DIRECTION INPUT ;
    USE SIGNAL ;
    PORT
      LAYER M5 ;
        RECT  17.856 60.396 17.88 60.48 ;
    END
  END cfg_data[24]
  PIN cfg_data[250]
    DIRECTION INPUT ;
    USE SIGNAL ;
    PORT
      LAYER M5 ;
        RECT  13.536 60.396 13.56 60.48 ;
    END
  END cfg_data[250]
  PIN cfg_data[251]
    DIRECTION INPUT ;
    USE SIGNAL ;
    PORT
      LAYER M5 ;
        RECT  13.68 60.396 13.704 60.48 ;
    END
  END cfg_data[251]
  PIN cfg_data[252]
    DIRECTION INPUT ;
    USE SIGNAL ;
    PORT
      LAYER M5 ;
        RECT  13.824 60.396 13.848 60.48 ;
    END
  END cfg_data[252]
  PIN cfg_data[253]
    DIRECTION INPUT ;
    USE SIGNAL ;
    PORT
      LAYER M5 ;
        RECT  13.968 60.396 13.992 60.48 ;
    END
  END cfg_data[253]
  PIN cfg_data[254]
    DIRECTION INPUT ;
    USE SIGNAL ;
    PORT
      LAYER M5 ;
        RECT  14.112 60.396 14.136 60.48 ;
    END
  END cfg_data[254]
  PIN cfg_data[255]
    DIRECTION INPUT ;
    USE SIGNAL ;
    PORT
      LAYER M5 ;
        RECT  14.256 60.396 14.28 60.48 ;
    END
  END cfg_data[255]
  PIN cfg_data[25]
    DIRECTION INPUT ;
    USE SIGNAL ;
    PORT
      LAYER M5 ;
        RECT  18 60.396 18.024 60.48 ;
    END
  END cfg_data[25]
  PIN cfg_data[26]
    DIRECTION INPUT ;
    USE SIGNAL ;
    PORT
      LAYER M5 ;
        RECT  18.144 60.396 18.168 60.48 ;
    END
  END cfg_data[26]
  PIN cfg_data[27]
    DIRECTION INPUT ;
    USE SIGNAL ;
    PORT
      LAYER M5 ;
        RECT  18.288 60.396 18.312 60.48 ;
    END
  END cfg_data[27]
  PIN cfg_data[28]
    DIRECTION INPUT ;
    USE SIGNAL ;
    PORT
      LAYER M5 ;
        RECT  18.432 60.396 18.456 60.48 ;
    END
  END cfg_data[28]
  PIN cfg_data[29]
    DIRECTION INPUT ;
    USE SIGNAL ;
    PORT
      LAYER M5 ;
        RECT  18.576 60.396 18.6 60.48 ;
    END
  END cfg_data[29]
  PIN cfg_data[2]
    DIRECTION INPUT ;
    USE SIGNAL ;
    PORT
      LAYER M5 ;
        RECT  28.512 60.396 28.536 60.48 ;
    END
  END cfg_data[2]
  PIN cfg_data[30]
    DIRECTION INPUT ;
    USE SIGNAL ;
    PORT
      LAYER M5 ;
        RECT  18.72 60.396 18.744 60.48 ;
    END
  END cfg_data[30]
  PIN cfg_data[31]
    DIRECTION INPUT ;
    USE SIGNAL ;
    PORT
      LAYER M5 ;
        RECT  18.864 60.396 18.888 60.48 ;
    END
  END cfg_data[31]
  PIN cfg_data[32]
    DIRECTION INPUT ;
    USE SIGNAL ;
    PORT
      LAYER M5 ;
        RECT  19.008 60.396 19.032 60.48 ;
    END
  END cfg_data[32]
  PIN cfg_data[33]
    DIRECTION INPUT ;
    USE SIGNAL ;
    PORT
      LAYER M5 ;
        RECT  19.152 60.396 19.176 60.48 ;
    END
  END cfg_data[33]
  PIN cfg_data[34]
    DIRECTION INPUT ;
    USE SIGNAL ;
    PORT
      LAYER M5 ;
        RECT  19.296 60.396 19.32 60.48 ;
    END
  END cfg_data[34]
  PIN cfg_data[35]
    DIRECTION INPUT ;
    USE SIGNAL ;
    PORT
      LAYER M5 ;
        RECT  19.44 60.396 19.464 60.48 ;
    END
  END cfg_data[35]
  PIN cfg_data[36]
    DIRECTION INPUT ;
    USE SIGNAL ;
    PORT
      LAYER M5 ;
        RECT  19.584 60.396 19.608 60.48 ;
    END
  END cfg_data[36]
  PIN cfg_data[37]
    DIRECTION INPUT ;
    USE SIGNAL ;
    PORT
      LAYER M5 ;
        RECT  19.728 60.396 19.752 60.48 ;
    END
  END cfg_data[37]
  PIN cfg_data[38]
    DIRECTION INPUT ;
    USE SIGNAL ;
    PORT
      LAYER M5 ;
        RECT  19.872 60.396 19.896 60.48 ;
    END
  END cfg_data[38]
  PIN cfg_data[39]
    DIRECTION INPUT ;
    USE SIGNAL ;
    PORT
      LAYER M5 ;
        RECT  20.016 60.396 20.04 60.48 ;
    END
  END cfg_data[39]
  PIN cfg_data[3]
    DIRECTION INPUT ;
    USE SIGNAL ;
    PORT
      LAYER M5 ;
        RECT  28.656 60.396 28.68 60.48 ;
    END
  END cfg_data[3]
  PIN cfg_data[40]
    DIRECTION INPUT ;
    USE SIGNAL ;
    PORT
      LAYER M5 ;
        RECT  20.16 60.396 20.184 60.48 ;
    END
  END cfg_data[40]
  PIN cfg_data[41]
    DIRECTION INPUT ;
    USE SIGNAL ;
    PORT
      LAYER M5 ;
        RECT  20.304 60.396 20.328 60.48 ;
    END
  END cfg_data[41]
  PIN cfg_data[42]
    DIRECTION INPUT ;
    USE SIGNAL ;
    PORT
      LAYER M5 ;
        RECT  20.448 60.396 20.472 60.48 ;
    END
  END cfg_data[42]
  PIN cfg_data[43]
    DIRECTION INPUT ;
    USE SIGNAL ;
    PORT
      LAYER M5 ;
        RECT  20.592 60.396 20.616 60.48 ;
    END
  END cfg_data[43]
  PIN cfg_data[44]
    DIRECTION INPUT ;
    USE SIGNAL ;
    PORT
      LAYER M5 ;
        RECT  20.736 60.396 20.76 60.48 ;
    END
  END cfg_data[44]
  PIN cfg_data[45]
    DIRECTION INPUT ;
    USE SIGNAL ;
    PORT
      LAYER M5 ;
        RECT  20.88 60.396 20.904 60.48 ;
    END
  END cfg_data[45]
  PIN cfg_data[46]
    DIRECTION INPUT ;
    USE SIGNAL ;
    PORT
      LAYER M5 ;
        RECT  21.024 60.396 21.048 60.48 ;
    END
  END cfg_data[46]
  PIN cfg_data[47]
    DIRECTION INPUT ;
    USE SIGNAL ;
    PORT
      LAYER M5 ;
        RECT  21.168 60.396 21.192 60.48 ;
    END
  END cfg_data[47]
  PIN cfg_data[48]
    DIRECTION INPUT ;
    USE SIGNAL ;
    PORT
      LAYER M5 ;
        RECT  21.312 60.396 21.336 60.48 ;
    END
  END cfg_data[48]
  PIN cfg_data[49]
    DIRECTION INPUT ;
    USE SIGNAL ;
    PORT
      LAYER M5 ;
        RECT  21.456 60.396 21.48 60.48 ;
    END
  END cfg_data[49]
  PIN cfg_data[4]
    DIRECTION INPUT ;
    USE SIGNAL ;
    PORT
      LAYER M5 ;
        RECT  28.8 60.396 28.824 60.48 ;
    END
  END cfg_data[4]
  PIN cfg_data[50]
    DIRECTION INPUT ;
    USE SIGNAL ;
    PORT
      LAYER M5 ;
        RECT  21.6 60.396 21.624 60.48 ;
    END
  END cfg_data[50]
  PIN cfg_data[51]
    DIRECTION INPUT ;
    USE SIGNAL ;
    PORT
      LAYER M5 ;
        RECT  36.72 60.396 36.744 60.48 ;
    END
  END cfg_data[51]
  PIN cfg_data[52]
    DIRECTION INPUT ;
    USE SIGNAL ;
    PORT
      LAYER M5 ;
        RECT  36.864 60.396 36.888 60.48 ;
    END
  END cfg_data[52]
  PIN cfg_data[53]
    DIRECTION INPUT ;
    USE SIGNAL ;
    PORT
      LAYER M5 ;
        RECT  37.008 60.396 37.032 60.48 ;
    END
  END cfg_data[53]
  PIN cfg_data[54]
    DIRECTION INPUT ;
    USE SIGNAL ;
    PORT
      LAYER M5 ;
        RECT  37.152 60.396 37.176 60.48 ;
    END
  END cfg_data[54]
  PIN cfg_data[55]
    DIRECTION INPUT ;
    USE SIGNAL ;
    PORT
      LAYER M5 ;
        RECT  37.296 60.396 37.32 60.48 ;
    END
  END cfg_data[55]
  PIN cfg_data[56]
    DIRECTION INPUT ;
    USE SIGNAL ;
    PORT
      LAYER M5 ;
        RECT  37.44 60.396 37.464 60.48 ;
    END
  END cfg_data[56]
  PIN cfg_data[57]
    DIRECTION INPUT ;
    USE SIGNAL ;
    PORT
      LAYER M5 ;
        RECT  37.584 60.396 37.608 60.48 ;
    END
  END cfg_data[57]
  PIN cfg_data[58]
    DIRECTION INPUT ;
    USE SIGNAL ;
    PORT
      LAYER M5 ;
        RECT  37.728 60.396 37.752 60.48 ;
    END
  END cfg_data[58]
  PIN cfg_data[59]
    DIRECTION INPUT ;
    USE SIGNAL ;
    PORT
      LAYER M5 ;
        RECT  37.872 60.396 37.896 60.48 ;
    END
  END cfg_data[59]
  PIN cfg_data[5]
    DIRECTION INPUT ;
    USE SIGNAL ;
    PORT
      LAYER M5 ;
        RECT  28.944 60.396 28.968 60.48 ;
    END
  END cfg_data[5]
  PIN cfg_data[60]
    DIRECTION INPUT ;
    USE SIGNAL ;
    PORT
      LAYER M5 ;
        RECT  38.016 60.396 38.04 60.48 ;
    END
  END cfg_data[60]
  PIN cfg_data[61]
    DIRECTION INPUT ;
    USE SIGNAL ;
    PORT
      LAYER M5 ;
        RECT  38.16 60.396 38.184 60.48 ;
    END
  END cfg_data[61]
  PIN cfg_data[62]
    DIRECTION INPUT ;
    USE SIGNAL ;
    PORT
      LAYER M5 ;
        RECT  38.304 60.396 38.328 60.48 ;
    END
  END cfg_data[62]
  PIN cfg_data[63]
    DIRECTION INPUT ;
    USE SIGNAL ;
    PORT
      LAYER M5 ;
        RECT  38.448 60.396 38.472 60.48 ;
    END
  END cfg_data[63]
  PIN cfg_data[64]
    DIRECTION INPUT ;
    USE SIGNAL ;
    PORT
      LAYER M5 ;
        RECT  38.592 60.396 38.616 60.48 ;
    END
  END cfg_data[64]
  PIN cfg_data[65]
    DIRECTION INPUT ;
    USE SIGNAL ;
    PORT
      LAYER M5 ;
        RECT  38.736 60.396 38.76 60.48 ;
    END
  END cfg_data[65]
  PIN cfg_data[66]
    DIRECTION INPUT ;
    USE SIGNAL ;
    PORT
      LAYER M5 ;
        RECT  38.88 60.396 38.904 60.48 ;
    END
  END cfg_data[66]
  PIN cfg_data[67]
    DIRECTION INPUT ;
    USE SIGNAL ;
    PORT
      LAYER M5 ;
        RECT  39.024 60.396 39.048 60.48 ;
    END
  END cfg_data[67]
  PIN cfg_data[68]
    DIRECTION INPUT ;
    USE SIGNAL ;
    PORT
      LAYER M5 ;
        RECT  39.168 60.396 39.192 60.48 ;
    END
  END cfg_data[68]
  PIN cfg_data[69]
    DIRECTION INPUT ;
    USE SIGNAL ;
    PORT
      LAYER M5 ;
        RECT  39.312 60.396 39.336 60.48 ;
    END
  END cfg_data[69]
  PIN cfg_data[6]
    DIRECTION INPUT ;
    USE SIGNAL ;
    PORT
      LAYER M5 ;
        RECT  29.088 60.396 29.112 60.48 ;
    END
  END cfg_data[6]
  PIN cfg_data[70]
    DIRECTION INPUT ;
    USE SIGNAL ;
    PORT
      LAYER M5 ;
        RECT  39.456 60.396 39.48 60.48 ;
    END
  END cfg_data[70]
  PIN cfg_data[71]
    DIRECTION INPUT ;
    USE SIGNAL ;
    PORT
      LAYER M5 ;
        RECT  39.6 60.396 39.624 60.48 ;
    END
  END cfg_data[71]
  PIN cfg_data[72]
    DIRECTION INPUT ;
    USE SIGNAL ;
    PORT
      LAYER M5 ;
        RECT  39.744 60.396 39.768 60.48 ;
    END
  END cfg_data[72]
  PIN cfg_data[73]
    DIRECTION INPUT ;
    USE SIGNAL ;
    PORT
      LAYER M5 ;
        RECT  39.888 60.396 39.912 60.48 ;
    END
  END cfg_data[73]
  PIN cfg_data[74]
    DIRECTION INPUT ;
    USE SIGNAL ;
    PORT
      LAYER M5 ;
        RECT  40.032 60.396 40.056 60.48 ;
    END
  END cfg_data[74]
  PIN cfg_data[75]
    DIRECTION INPUT ;
    USE SIGNAL ;
    PORT
      LAYER M5 ;
        RECT  40.176 60.396 40.2 60.48 ;
    END
  END cfg_data[75]
  PIN cfg_data[76]
    DIRECTION INPUT ;
    USE SIGNAL ;
    PORT
      LAYER M5 ;
        RECT  40.32 60.396 40.344 60.48 ;
    END
  END cfg_data[76]
  PIN cfg_data[77]
    DIRECTION INPUT ;
    USE SIGNAL ;
    PORT
      LAYER M5 ;
        RECT  40.464 60.396 40.488 60.48 ;
    END
  END cfg_data[77]
  PIN cfg_data[78]
    DIRECTION INPUT ;
    USE SIGNAL ;
    PORT
      LAYER M5 ;
        RECT  40.608 60.396 40.632 60.48 ;
    END
  END cfg_data[78]
  PIN cfg_data[79]
    DIRECTION INPUT ;
    USE SIGNAL ;
    PORT
      LAYER M5 ;
        RECT  40.752 60.396 40.776 60.48 ;
    END
  END cfg_data[79]
  PIN cfg_data[7]
    DIRECTION INPUT ;
    USE SIGNAL ;
    PORT
      LAYER M5 ;
        RECT  29.232 60.396 29.256 60.48 ;
    END
  END cfg_data[7]
  PIN cfg_data[80]
    DIRECTION INPUT ;
    USE SIGNAL ;
    PORT
      LAYER M5 ;
        RECT  40.896 60.396 40.92 60.48 ;
    END
  END cfg_data[80]
  PIN cfg_data[81]
    DIRECTION INPUT ;
    USE SIGNAL ;
    PORT
      LAYER M5 ;
        RECT  41.04 60.396 41.064 60.48 ;
    END
  END cfg_data[81]
  PIN cfg_data[82]
    DIRECTION INPUT ;
    USE SIGNAL ;
    PORT
      LAYER M5 ;
        RECT  41.184 60.396 41.208 60.48 ;
    END
  END cfg_data[82]
  PIN cfg_data[83]
    DIRECTION INPUT ;
    USE SIGNAL ;
    PORT
      LAYER M5 ;
        RECT  21.744 60.396 21.768 60.48 ;
    END
  END cfg_data[83]
  PIN cfg_data[84]
    DIRECTION INPUT ;
    USE SIGNAL ;
    PORT
      LAYER M5 ;
        RECT  21.888 60.396 21.912 60.48 ;
    END
  END cfg_data[84]
  PIN cfg_data[85]
    DIRECTION INPUT ;
    USE SIGNAL ;
    PORT
      LAYER M5 ;
        RECT  22.032 60.396 22.056 60.48 ;
    END
  END cfg_data[85]
  PIN cfg_data[86]
    DIRECTION INPUT ;
    USE SIGNAL ;
    PORT
      LAYER M5 ;
        RECT  22.176 60.396 22.2 60.48 ;
    END
  END cfg_data[86]
  PIN cfg_data[87]
    DIRECTION INPUT ;
    USE SIGNAL ;
    PORT
      LAYER M5 ;
        RECT  22.32 60.396 22.344 60.48 ;
    END
  END cfg_data[87]
  PIN cfg_data[88]
    DIRECTION INPUT ;
    USE SIGNAL ;
    PORT
      LAYER M5 ;
        RECT  22.464 60.396 22.488 60.48 ;
    END
  END cfg_data[88]
  PIN cfg_data[89]
    DIRECTION INPUT ;
    USE SIGNAL ;
    PORT
      LAYER M5 ;
        RECT  22.608 60.396 22.632 60.48 ;
    END
  END cfg_data[89]
  PIN cfg_data[8]
    DIRECTION INPUT ;
    USE SIGNAL ;
    PORT
      LAYER M5 ;
        RECT  29.376 60.396 29.4 60.48 ;
    END
  END cfg_data[8]
  PIN cfg_data[90]
    DIRECTION INPUT ;
    USE SIGNAL ;
    PORT
      LAYER M5 ;
        RECT  22.752 60.396 22.776 60.48 ;
    END
  END cfg_data[90]
  PIN cfg_data[91]
    DIRECTION INPUT ;
    USE SIGNAL ;
    PORT
      LAYER M5 ;
        RECT  22.896 60.396 22.92 60.48 ;
    END
  END cfg_data[91]
  PIN cfg_data[92]
    DIRECTION INPUT ;
    USE SIGNAL ;
    PORT
      LAYER M5 ;
        RECT  23.04 60.396 23.064 60.48 ;
    END
  END cfg_data[92]
  PIN cfg_data[93]
    DIRECTION INPUT ;
    USE SIGNAL ;
    PORT
      LAYER M5 ;
        RECT  23.184 60.396 23.208 60.48 ;
    END
  END cfg_data[93]
  PIN cfg_data[94]
    DIRECTION INPUT ;
    USE SIGNAL ;
    PORT
      LAYER M5 ;
        RECT  23.328 60.396 23.352 60.48 ;
    END
  END cfg_data[94]
  PIN cfg_data[95]
    DIRECTION INPUT ;
    USE SIGNAL ;
    PORT
      LAYER M5 ;
        RECT  23.472 60.396 23.496 60.48 ;
    END
  END cfg_data[95]
  PIN cfg_data[96]
    DIRECTION INPUT ;
    USE SIGNAL ;
    PORT
      LAYER M5 ;
        RECT  23.616 60.396 23.64 60.48 ;
    END
  END cfg_data[96]
  PIN cfg_data[97]
    DIRECTION INPUT ;
    USE SIGNAL ;
    PORT
      LAYER M5 ;
        RECT  23.76 60.396 23.784 60.48 ;
    END
  END cfg_data[97]
  PIN cfg_data[98]
    DIRECTION INPUT ;
    USE SIGNAL ;
    PORT
      LAYER M5 ;
        RECT  23.904 60.396 23.928 60.48 ;
    END
  END cfg_data[98]
  PIN cfg_data[99]
    DIRECTION INPUT ;
    USE SIGNAL ;
    PORT
      LAYER M5 ;
        RECT  24.048 60.396 24.072 60.48 ;
    END
  END cfg_data[99]
  PIN cfg_data[9]
    DIRECTION INPUT ;
    USE SIGNAL ;
    PORT
      LAYER M5 ;
        RECT  29.52 60.396 29.544 60.48 ;
    END
  END cfg_data[9]
  PIN cfg_target[0]
    DIRECTION INPUT ;
    USE SIGNAL ;
    PORT
      LAYER M5 ;
        RECT  14.4 60.396 14.424 60.48 ;
    END
  END cfg_target[0]
  PIN cfg_target[1]
    DIRECTION INPUT ;
    USE SIGNAL ;
    PORT
      LAYER M5 ;
        RECT  14.544 60.396 14.568 60.48 ;
    END
  END cfg_target[1]
  PIN cfg_target[2]
    DIRECTION INPUT ;
    USE SIGNAL ;
    PORT
      LAYER M5 ;
        RECT  14.688 60.396 14.712 60.48 ;
    END
  END cfg_target[2]
  PIN cfg_target[3]
    DIRECTION INPUT ;
    USE SIGNAL ;
    PORT
      LAYER M5 ;
        RECT  14.832 60.396 14.856 60.48 ;
    END
  END cfg_target[3]
  PIN cfg_target[4]
    DIRECTION INPUT ;
    USE SIGNAL ;
    PORT
      LAYER M5 ;
        RECT  14.976 60.396 15 60.48 ;
    END
  END cfg_target[4]
  PIN cfg_target[5]
    DIRECTION INPUT ;
    USE SIGNAL ;
    PORT
      LAYER M5 ;
        RECT  15.12 60.396 15.144 60.48 ;
    END
  END cfg_target[5]
  PIN cfg_target[6]
    DIRECTION INPUT ;
    USE SIGNAL ;
    PORT
      LAYER M5 ;
        RECT  15.264 60.396 15.288 60.48 ;
    END
  END cfg_target[6]
  PIN cfg_target[7]
    DIRECTION INPUT ;
    USE SIGNAL ;
    PORT
      LAYER M5 ;
        RECT  15.408 60.396 15.432 60.48 ;
    END
  END cfg_target[7]
  PIN cfg_v
    DIRECTION INPUT ;
    USE SIGNAL ;
    PORT
      LAYER M5 ;
        RECT  15.552 60.396 15.576 60.48 ;
    END
  END cfg_v
  PIN clk
    DIRECTION INPUT ;
    USE SIGNAL ;
    PORT
      LAYER M5 ;
        RECT  15.696 60.396 15.72 60.48 ;
    END
  END clk
  PIN cmd[0]
    DIRECTION OUTPUT ;
    USE SIGNAL ;
    PORT
      LAYER M4 ;
        RECT  0 12.528 0.084 12.552 ;
    END
  END cmd[0]
  PIN cmd_v
    DIRECTION OUTPUT ;
    USE SIGNAL ;
    PORT
      LAYER M4 ;
        RECT  0 12.672 0.084 12.696 ;
    END
  END cmd_v
  PIN configured
    DIRECTION OUTPUT ;
    USE SIGNAL ;
    PORT
      LAYER M5 ;
        RECT  15.84 60.396 15.864 60.48 ;
    END
  END configured
  PIN cycle[0]
    DIRECTION OUTPUT ;
    USE SIGNAL ;
    PORT
      LAYER M4 ;
        RECT  0 12.816 0.084 12.84 ;
    END
  END cycle[0]
  PIN cycle[10]
    DIRECTION OUTPUT ;
    USE SIGNAL ;
    PORT
      LAYER M4 ;
        RECT  0 14.256 0.084 14.28 ;
    END
  END cycle[10]
  PIN cycle[11]
    DIRECTION OUTPUT ;
    USE SIGNAL ;
    PORT
      LAYER M4 ;
        RECT  0 14.4 0.084 14.424 ;
    END
  END cycle[11]
  PIN cycle[12]
    DIRECTION OUTPUT ;
    USE SIGNAL ;
    PORT
      LAYER M4 ;
        RECT  0 14.544 0.084 14.568 ;
    END
  END cycle[12]
  PIN cycle[13]
    DIRECTION OUTPUT ;
    USE SIGNAL ;
    PORT
      LAYER M4 ;
        RECT  0 14.688 0.084 14.712 ;
    END
  END cycle[13]
  PIN cycle[14]
    DIRECTION OUTPUT ;
    USE SIGNAL ;
    PORT
      LAYER M4 ;
        RECT  0 14.832 0.084 14.856 ;
    END
  END cycle[14]
  PIN cycle[15]
    DIRECTION OUTPUT ;
    USE SIGNAL ;
    PORT
      LAYER M4 ;
        RECT  0 14.976 0.084 15 ;
    END
  END cycle[15]
  PIN cycle[16]
    DIRECTION OUTPUT ;
    USE SIGNAL ;
    PORT
      LAYER M4 ;
        RECT  0 15.12 0.084 15.144 ;
    END
  END cycle[16]
  PIN cycle[17]
    DIRECTION OUTPUT ;
    USE SIGNAL ;
    PORT
      LAYER M4 ;
        RECT  0 15.264 0.084 15.288 ;
    END
  END cycle[17]
  PIN cycle[18]
    DIRECTION OUTPUT ;
    USE SIGNAL ;
    PORT
      LAYER M4 ;
        RECT  0 15.408 0.084 15.432 ;
    END
  END cycle[18]
  PIN cycle[19]
    DIRECTION OUTPUT ;
    USE SIGNAL ;
    PORT
      LAYER M4 ;
        RECT  0 15.552 0.084 15.576 ;
    END
  END cycle[19]
  PIN cycle[1]
    DIRECTION OUTPUT ;
    USE SIGNAL ;
    PORT
      LAYER M4 ;
        RECT  0 12.96 0.084 12.984 ;
    END
  END cycle[1]
  PIN cycle[20]
    DIRECTION OUTPUT ;
    USE SIGNAL ;
    PORT
      LAYER M4 ;
        RECT  0 15.696 0.084 15.72 ;
    END
  END cycle[20]
  PIN cycle[21]
    DIRECTION OUTPUT ;
    USE SIGNAL ;
    PORT
      LAYER M4 ;
        RECT  0 15.84 0.084 15.864 ;
    END
  END cycle[21]
  PIN cycle[22]
    DIRECTION OUTPUT ;
    USE SIGNAL ;
    PORT
      LAYER M4 ;
        RECT  0 15.984 0.084 16.008 ;
    END
  END cycle[22]
  PIN cycle[23]
    DIRECTION OUTPUT ;
    USE SIGNAL ;
    PORT
      LAYER M4 ;
        RECT  0 16.128 0.084 16.152 ;
    END
  END cycle[23]
  PIN cycle[24]
    DIRECTION OUTPUT ;
    USE SIGNAL ;
    PORT
      LAYER M4 ;
        RECT  0 16.272 0.084 16.296 ;
    END
  END cycle[24]
  PIN cycle[25]
    DIRECTION OUTPUT ;
    USE SIGNAL ;
    PORT
      LAYER M4 ;
        RECT  0 16.416 0.084 16.44 ;
    END
  END cycle[25]
  PIN cycle[26]
    DIRECTION OUTPUT ;
    USE SIGNAL ;
    PORT
      LAYER M4 ;
        RECT  0 16.56 0.084 16.584 ;
    END
  END cycle[26]
  PIN cycle[27]
    DIRECTION OUTPUT ;
    USE SIGNAL ;
    PORT
      LAYER M4 ;
        RECT  0 16.704 0.084 16.728 ;
    END
  END cycle[27]
  PIN cycle[28]
    DIRECTION OUTPUT ;
    USE SIGNAL ;
    PORT
      LAYER M4 ;
        RECT  0 16.848 0.084 16.872 ;
    END
  END cycle[28]
  PIN cycle[29]
    DIRECTION OUTPUT ;
    USE SIGNAL ;
    PORT
      LAYER M4 ;
        RECT  0 16.992 0.084 17.016 ;
    END
  END cycle[29]
  PIN cycle[2]
    DIRECTION OUTPUT ;
    USE SIGNAL ;
    PORT
      LAYER M4 ;
        RECT  0 13.104 0.084 13.128 ;
    END
  END cycle[2]
  PIN cycle[30]
    DIRECTION OUTPUT ;
    USE SIGNAL ;
    PORT
      LAYER M4 ;
        RECT  0 21.456 0.084 21.48 ;
    END
  END cycle[30]
  PIN cycle[31]
    DIRECTION OUTPUT ;
    USE SIGNAL ;
    PORT
      LAYER M4 ;
        RECT  0 21.6 0.084 21.624 ;
    END
  END cycle[31]
  PIN cycle[3]
    DIRECTION OUTPUT ;
    USE SIGNAL ;
    PORT
      LAYER M4 ;
        RECT  0 13.248 0.084 13.272 ;
    END
  END cycle[3]
  PIN cycle[4]
    DIRECTION OUTPUT ;
    USE SIGNAL ;
    PORT
      LAYER M4 ;
        RECT  0 13.392 0.084 13.416 ;
    END
  END cycle[4]
  PIN cycle[5]
    DIRECTION OUTPUT ;
    USE SIGNAL ;
    PORT
      LAYER M4 ;
        RECT  0 13.536 0.084 13.56 ;
    END
  END cycle[5]
  PIN cycle[6]
    DIRECTION OUTPUT ;
    USE SIGNAL ;
    PORT
      LAYER M4 ;
        RECT  0 13.68 0.084 13.704 ;
    END
  END cycle[6]
  PIN cycle[7]
    DIRECTION OUTPUT ;
    USE SIGNAL ;
    PORT
      LAYER M4 ;
        RECT  0 13.824 0.084 13.848 ;
    END
  END cycle[7]
  PIN cycle[8]
    DIRECTION OUTPUT ;
    USE SIGNAL ;
    PORT
      LAYER M4 ;
        RECT  0 13.968 0.084 13.992 ;
    END
  END cycle[8]
  PIN cycle[9]
    DIRECTION OUTPUT ;
    USE SIGNAL ;
    PORT
      LAYER M4 ;
        RECT  0 14.112 0.084 14.136 ;
    END
  END cycle[9]
  PIN desc_base[0]
    DIRECTION INPUT ;
    USE SIGNAL ;
    PORT
      LAYER M5 ;
        RECT  15.984 60.396 16.008 60.48 ;
    END
  END desc_base[0]
  PIN desc_base[10]
    DIRECTION INPUT ;
    USE SIGNAL ;
    PORT
      LAYER M5 ;
        RECT  8.208 60.396 8.232 60.48 ;
    END
  END desc_base[10]
  PIN desc_base[11]
    DIRECTION INPUT ;
    USE SIGNAL ;
    PORT
      LAYER M5 ;
        RECT  8.352 60.396 8.376 60.48 ;
    END
  END desc_base[11]
  PIN desc_base[1]
    DIRECTION INPUT ;
    USE SIGNAL ;
    PORT
      LAYER M5 ;
        RECT  16.128 60.396 16.152 60.48 ;
    END
  END desc_base[1]
  PIN desc_base[2]
    DIRECTION INPUT ;
    USE SIGNAL ;
    PORT
      LAYER M5 ;
        RECT  16.272 60.396 16.296 60.48 ;
    END
  END desc_base[2]
  PIN desc_base[3]
    DIRECTION INPUT ;
    USE SIGNAL ;
    PORT
      LAYER M5 ;
        RECT  16.416 60.396 16.44 60.48 ;
    END
  END desc_base[3]
  PIN desc_base[4]
    DIRECTION INPUT ;
    USE SIGNAL ;
    PORT
      LAYER M5 ;
        RECT  16.56 60.396 16.584 60.48 ;
    END
  END desc_base[4]
  PIN desc_base[5]
    DIRECTION INPUT ;
    USE SIGNAL ;
    PORT
      LAYER M5 ;
        RECT  16.704 60.396 16.728 60.48 ;
    END
  END desc_base[5]
  PIN desc_base[6]
    DIRECTION INPUT ;
    USE SIGNAL ;
    PORT
      LAYER M5 ;
        RECT  16.848 60.396 16.872 60.48 ;
    END
  END desc_base[6]
  PIN desc_base[7]
    DIRECTION INPUT ;
    USE SIGNAL ;
    PORT
      LAYER M5 ;
        RECT  16.992 60.396 17.016 60.48 ;
    END
  END desc_base[7]
  PIN desc_base[8]
    DIRECTION INPUT ;
    USE SIGNAL ;
    PORT
      LAYER M5 ;
        RECT  7.92 60.396 7.944 60.48 ;
    END
  END desc_base[8]
  PIN desc_base[9]
    DIRECTION INPUT ;
    USE SIGNAL ;
    PORT
      LAYER M5 ;
        RECT  8.064 60.396 8.088 60.48 ;
    END
  END desc_base[9]
  PIN desc_limit[0]
    DIRECTION INPUT ;
    USE SIGNAL ;
    PORT
      LAYER M5 ;
        RECT  8.496 60.396 8.52 60.48 ;
    END
  END desc_limit[0]
  PIN desc_limit[10]
    DIRECTION INPUT ;
    USE SIGNAL ;
    PORT
      LAYER M5 ;
        RECT  9.936 60.396 9.96 60.48 ;
    END
  END desc_limit[10]
  PIN desc_limit[11]
    DIRECTION INPUT ;
    USE SIGNAL ;
    PORT
      LAYER M5 ;
        RECT  10.08 60.396 10.104 60.48 ;
    END
  END desc_limit[11]
  PIN desc_limit[12]
    DIRECTION INPUT ;
    USE SIGNAL ;
    PORT
      LAYER M5 ;
        RECT  10.224 60.396 10.248 60.48 ;
    END
  END desc_limit[12]
  PIN desc_limit[1]
    DIRECTION INPUT ;
    USE SIGNAL ;
    PORT
      LAYER M5 ;
        RECT  8.64 60.396 8.664 60.48 ;
    END
  END desc_limit[1]
  PIN desc_limit[2]
    DIRECTION INPUT ;
    USE SIGNAL ;
    PORT
      LAYER M5 ;
        RECT  8.784 60.396 8.808 60.48 ;
    END
  END desc_limit[2]
  PIN desc_limit[3]
    DIRECTION INPUT ;
    USE SIGNAL ;
    PORT
      LAYER M5 ;
        RECT  8.928 60.396 8.952 60.48 ;
    END
  END desc_limit[3]
  PIN desc_limit[4]
    DIRECTION INPUT ;
    USE SIGNAL ;
    PORT
      LAYER M5 ;
        RECT  9.072 60.396 9.096 60.48 ;
    END
  END desc_limit[4]
  PIN desc_limit[5]
    DIRECTION INPUT ;
    USE SIGNAL ;
    PORT
      LAYER M5 ;
        RECT  9.216 60.396 9.24 60.48 ;
    END
  END desc_limit[5]
  PIN desc_limit[6]
    DIRECTION INPUT ;
    USE SIGNAL ;
    PORT
      LAYER M5 ;
        RECT  9.36 60.396 9.384 60.48 ;
    END
  END desc_limit[6]
  PIN desc_limit[7]
    DIRECTION INPUT ;
    USE SIGNAL ;
    PORT
      LAYER M5 ;
        RECT  9.504 60.396 9.528 60.48 ;
    END
  END desc_limit[7]
  PIN desc_limit[8]
    DIRECTION INPUT ;
    USE SIGNAL ;
    PORT
      LAYER M5 ;
        RECT  9.648 60.396 9.672 60.48 ;
    END
  END desc_limit[8]
  PIN desc_limit[9]
    DIRECTION INPUT ;
    USE SIGNAL ;
    PORT
      LAYER M5 ;
        RECT  9.792 60.396 9.816 60.48 ;
    END
  END desc_limit[9]
  PIN desc_loops[0]
    DIRECTION INPUT ;
    USE SIGNAL ;
    PORT
      LAYER M5 ;
        RECT  10.368 60.396 10.392 60.48 ;
    END
  END desc_loops[0]
  PIN desc_loops[10]
    DIRECTION INPUT ;
    USE SIGNAL ;
    PORT
      LAYER M5 ;
        RECT  11.808 60.396 11.832 60.48 ;
    END
  END desc_loops[10]
  PIN desc_loops[11]
    DIRECTION INPUT ;
    USE SIGNAL ;
    PORT
      LAYER M5 ;
        RECT  11.952 60.396 11.976 60.48 ;
    END
  END desc_loops[11]
  PIN desc_loops[12]
    DIRECTION INPUT ;
    USE SIGNAL ;
    PORT
      LAYER M5 ;
        RECT  12.096 60.396 12.12 60.48 ;
    END
  END desc_loops[12]
  PIN desc_loops[13]
    DIRECTION INPUT ;
    USE SIGNAL ;
    PORT
      LAYER M5 ;
        RECT  12.24 60.396 12.264 60.48 ;
    END
  END desc_loops[13]
  PIN desc_loops[14]
    DIRECTION INPUT ;
    USE SIGNAL ;
    PORT
      LAYER M5 ;
        RECT  12.384 60.396 12.408 60.48 ;
    END
  END desc_loops[14]
  PIN desc_loops[15]
    DIRECTION INPUT ;
    USE SIGNAL ;
    PORT
      LAYER M5 ;
        RECT  6.048 60.396 6.072 60.48 ;
    END
  END desc_loops[15]
  PIN desc_loops[1]
    DIRECTION INPUT ;
    USE SIGNAL ;
    PORT
      LAYER M5 ;
        RECT  10.512 60.396 10.536 60.48 ;
    END
  END desc_loops[1]
  PIN desc_loops[2]
    DIRECTION INPUT ;
    USE SIGNAL ;
    PORT
      LAYER M5 ;
        RECT  10.656 60.396 10.68 60.48 ;
    END
  END desc_loops[2]
  PIN desc_loops[3]
    DIRECTION INPUT ;
    USE SIGNAL ;
    PORT
      LAYER M5 ;
        RECT  10.8 60.396 10.824 60.48 ;
    END
  END desc_loops[3]
  PIN desc_loops[4]
    DIRECTION INPUT ;
    USE SIGNAL ;
    PORT
      LAYER M5 ;
        RECT  10.944 60.396 10.968 60.48 ;
    END
  END desc_loops[4]
  PIN desc_loops[5]
    DIRECTION INPUT ;
    USE SIGNAL ;
    PORT
      LAYER M5 ;
        RECT  11.088 60.396 11.112 60.48 ;
    END
  END desc_loops[5]
  PIN desc_loops[6]
    DIRECTION INPUT ;
    USE SIGNAL ;
    PORT
      LAYER M5 ;
        RECT  11.232 60.396 11.256 60.48 ;
    END
  END desc_loops[6]
  PIN desc_loops[7]
    DIRECTION INPUT ;
    USE SIGNAL ;
    PORT
      LAYER M5 ;
        RECT  11.376 60.396 11.4 60.48 ;
    END
  END desc_loops[7]
  PIN desc_loops[8]
    DIRECTION INPUT ;
    USE SIGNAL ;
    PORT
      LAYER M5 ;
        RECT  11.52 60.396 11.544 60.48 ;
    END
  END desc_loops[8]
  PIN desc_loops[9]
    DIRECTION INPUT ;
    USE SIGNAL ;
    PORT
      LAYER M5 ;
        RECT  11.664 60.396 11.688 60.48 ;
    END
  END desc_loops[9]
  PIN desc_v
    DIRECTION INPUT ;
    USE SIGNAL ;
    PORT
      LAYER M5 ;
        RECT  6.192 60.396 6.216 60.48 ;
    END
  END desc_v
  PIN fault
    DIRECTION OUTPUT ;
    USE SIGNAL ;
    PORT
      LAYER M5 ;
        RECT  6.336 60.396 6.36 60.48 ;
    END
  END fault
  PIN launch_v
    DIRECTION INPUT ;
    USE SIGNAL ;
    PORT
      LAYER M5 ;
        RECT  6.48 60.396 6.504 60.48 ;
    END
  END launch_v
  PIN rst_n
    DIRECTION INPUT ;
    USE SIGNAL ;
    PORT
      LAYER M5 ;
        RECT  6.624 60.396 6.648 60.48 ;
    END
  END rst_n
  PIN run_base[0]
    DIRECTION OUTPUT ;
    USE SIGNAL ;
    PORT
      LAYER M5 ;
        RECT  11.52 0 11.544 0.084 ;
    END
  END run_base[0]
  PIN run_base[1]
    DIRECTION OUTPUT ;
    USE SIGNAL ;
    PORT
      LAYER M5 ;
        RECT  11.664 0 11.688 0.084 ;
    END
  END run_base[1]
  PIN run_base[2]
    DIRECTION OUTPUT ;
    USE SIGNAL ;
    PORT
      LAYER M5 ;
        RECT  11.808 0 11.832 0.084 ;
    END
  END run_base[2]
  PIN run_base[3]
    DIRECTION OUTPUT ;
    USE SIGNAL ;
    PORT
      LAYER M5 ;
        RECT  11.952 0 11.976 0.084 ;
    END
  END run_base[3]
  PIN run_base[4]
    DIRECTION OUTPUT ;
    USE SIGNAL ;
    PORT
      LAYER M5 ;
        RECT  12.096 0 12.12 0.084 ;
    END
  END run_base[4]
  PIN run_base[5]
    DIRECTION OUTPUT ;
    USE SIGNAL ;
    PORT
      LAYER M5 ;
        RECT  12.24 0 12.264 0.084 ;
    END
  END run_base[5]
  PIN run_base[6]
    DIRECTION OUTPUT ;
    USE SIGNAL ;
    PORT
      LAYER M5 ;
        RECT  12.384 0 12.408 0.084 ;
    END
  END run_base[6]
  PIN run_count[0]
    DIRECTION OUTPUT ;
    USE SIGNAL ;
    PORT
      LAYER M5 ;
        RECT  12.528 0 12.552 0.084 ;
    END
  END run_count[0]
  PIN run_count[1]
    DIRECTION OUTPUT ;
    USE SIGNAL ;
    PORT
      LAYER M5 ;
        RECT  12.672 0 12.696 0.084 ;
    END
  END run_count[1]
  PIN run_count[2]
    DIRECTION OUTPUT ;
    USE SIGNAL ;
    PORT
      LAYER M5 ;
        RECT  12.816 0 12.84 0.084 ;
    END
  END run_count[2]
  PIN run_count[3]
    DIRECTION OUTPUT ;
    USE SIGNAL ;
    PORT
      LAYER M5 ;
        RECT  12.96 0 12.984 0.084 ;
    END
  END run_count[3]
  PIN run_count[4]
    DIRECTION OUTPUT ;
    USE SIGNAL ;
    PORT
      LAYER M5 ;
        RECT  13.104 0 13.128 0.084 ;
    END
  END run_count[4]
  PIN run_count[5]
    DIRECTION OUTPUT ;
    USE SIGNAL ;
    PORT
      LAYER M5 ;
        RECT  13.248 0 13.272 0.084 ;
    END
  END run_count[5]
  PIN run_count[6]
    DIRECTION OUTPUT ;
    USE SIGNAL ;
    PORT
      LAYER M5 ;
        RECT  13.392 0 13.416 0.084 ;
    END
  END run_count[6]
  PIN run_count[7]
    DIRECTION OUTPUT ;
    USE SIGNAL ;
    PORT
      LAYER M5 ;
        RECT  13.536 0 13.56 0.084 ;
    END
  END run_count[7]
  PIN run_v
    DIRECTION OUTPUT ;
    USE SIGNAL ;
    PORT
      LAYER M5 ;
        RECT  13.68 0 13.704 0.084 ;
    END
  END run_v
  PIN tgt[0]
    DIRECTION INPUT ;
    USE SIGNAL ;
    PORT
      LAYER M5 ;
        RECT  6.768 60.396 6.792 60.48 ;
    END
  END tgt[0]
  PIN tgt[1]
    DIRECTION INPUT ;
    USE SIGNAL ;
    PORT
      LAYER M5 ;
        RECT  6.912 60.396 6.936 60.48 ;
    END
  END tgt[1]
  PIN tgt[2]
    DIRECTION INPUT ;
    USE SIGNAL ;
    PORT
      LAYER M5 ;
        RECT  7.056 60.396 7.08 60.48 ;
    END
  END tgt[2]
  PIN tgt[3]
    DIRECTION INPUT ;
    USE SIGNAL ;
    PORT
      LAYER M5 ;
        RECT  7.2 60.396 7.224 60.48 ;
    END
  END tgt[3]
  PIN tgt[4]
    DIRECTION INPUT ;
    USE SIGNAL ;
    PORT
      LAYER M5 ;
        RECT  7.344 60.396 7.368 60.48 ;
    END
  END tgt[4]
  PIN tgt[5]
    DIRECTION INPUT ;
    USE SIGNAL ;
    PORT
      LAYER M5 ;
        RECT  7.488 60.396 7.512 60.48 ;
    END
  END tgt[5]
  PIN tgt[6]
    DIRECTION INPUT ;
    USE SIGNAL ;
    PORT
      LAYER M5 ;
        RECT  7.632 60.396 7.656 60.48 ;
    END
  END tgt[6]
  PIN tgt[7]
    DIRECTION INPUT ;
    USE SIGNAL ;
    PORT
      LAYER M5 ;
        RECT  7.776 60.396 7.8 60.48 ;
    END
  END tgt[7]
  PIN tgt_active[0]
    DIRECTION INPUT ;
    USE SIGNAL ;
    PORT
      LAYER M5 ;
        RECT  13.824 0 13.848 0.084 ;
    END
  END tgt_active[0]
  PIN tgt_active[1]
    DIRECTION INPUT ;
    USE SIGNAL ;
    PORT
      LAYER M5 ;
        RECT  13.968 0 13.992 0.084 ;
    END
  END tgt_active[1]
  PIN tgt_fault[0]
    DIRECTION INPUT ;
    USE SIGNAL ;
    PORT
      LAYER M5 ;
        RECT  14.112 0 14.136 0.084 ;
    END
  END tgt_fault[0]
  PIN VDD
    DIRECTION INOUT ;
    USE POWER ;
    PORT
      LAYER M5 ;
        RECT  56.592 2.151 56.712 58.329 ;
        RECT  51.192 2.151 51.312 58.329 ;
        RECT  45.792 2.151 45.912 58.329 ;
        RECT  40.392 2.151 40.512 58.329 ;
        RECT  34.992 2.151 35.112 58.329 ;
        RECT  29.592 2.151 29.712 58.329 ;
        RECT  24.192 2.151 24.312 58.329 ;
        RECT  18.792 2.151 18.912 58.329 ;
        RECT  13.392 2.151 13.512 58.329 ;
        RECT  7.992 2.151 8.112 58.329 ;
        RECT  2.592 2.151 2.712 58.329 ;
    END
  END VDD
  PIN VSS
    DIRECTION INOUT ;
    USE GROUND ;
    PORT
      LAYER M5 ;
        RECT  56.4 2.137 56.52 58.343 ;
        RECT  51 2.137 51.12 58.343 ;
        RECT  45.6 2.137 45.72 58.343 ;
        RECT  40.2 2.137 40.32 58.343 ;
        RECT  34.8 2.137 34.92 58.343 ;
        RECT  29.4 2.137 29.52 58.343 ;
        RECT  24 2.137 24.12 58.343 ;
        RECT  18.6 2.137 18.72 58.343 ;
        RECT  13.2 2.137 13.32 58.343 ;
        RECT  7.8 2.137 7.92 58.343 ;
        RECT  2.4 2.137 2.52 58.343 ;
    END
  END VSS
  OBS
    LAYER RVTN ;
     RECT  2.16 2.16 58.32 2.295 ;
     RECT  2.16 2.565 58.32 2.835 ;
     RECT  2.16 3.105 58.32 3.375 ;
     RECT  2.16 3.645 58.32 3.915 ;
     RECT  2.16 4.185 58.32 4.455 ;
     RECT  2.16 4.725 58.32 4.995 ;
     RECT  2.16 5.265 58.32 5.535 ;
     RECT  2.16 5.805 58.32 6.075 ;
     RECT  2.16 6.345 58.32 6.615 ;
     RECT  2.16 6.885 58.32 7.155 ;
     RECT  2.16 7.425 58.32 7.695 ;
     RECT  2.16 7.965 58.32 8.235 ;
     RECT  2.16 8.505 58.32 8.775 ;
     RECT  2.16 9.045 58.32 9.315 ;
     RECT  2.16 9.585 58.32 9.855 ;
     RECT  2.16 10.125 58.32 10.395 ;
     RECT  2.16 10.665 58.32 10.935 ;
     RECT  2.16 11.205 58.32 11.475 ;
     RECT  2.16 11.745 58.32 12.015 ;
     RECT  2.16 12.285 58.32 12.555 ;
     RECT  2.16 12.825 58.32 13.095 ;
     RECT  2.16 13.365 58.32 13.635 ;
     RECT  2.16 13.905 58.32 14.175 ;
     RECT  2.16 14.445 58.32 14.715 ;
     RECT  2.16 14.985 58.32 15.255 ;
     RECT  2.16 15.525 58.32 15.795 ;
     RECT  2.16 16.065 58.32 16.335 ;
     RECT  2.16 16.605 58.32 16.875 ;
     RECT  2.16 17.145 58.32 17.415 ;
     RECT  2.16 17.685 58.32 17.955 ;
     RECT  2.16 18.225 58.32 18.495 ;
     RECT  2.16 18.765 58.32 19.035 ;
     RECT  2.16 19.305 58.32 19.575 ;
     RECT  2.16 19.845 58.32 20.115 ;
     RECT  2.16 20.385 58.32 20.655 ;
     RECT  2.16 20.925 58.32 21.195 ;
     RECT  2.16 21.465 58.32 21.735 ;
     RECT  2.16 22.005 58.32 22.275 ;
     RECT  2.16 22.545 58.32 22.815 ;
     RECT  2.16 23.085 58.32 23.355 ;
     RECT  2.16 23.625 58.32 23.895 ;
     RECT  2.16 24.165 58.32 24.435 ;
     RECT  2.16 24.705 58.32 24.975 ;
     RECT  2.16 25.245 58.32 25.515 ;
     RECT  2.16 25.785 58.32 26.055 ;
     RECT  2.16 26.325 58.32 26.595 ;
     RECT  2.16 26.865 58.32 27.135 ;
     RECT  2.16 27.405 58.32 27.675 ;
     RECT  2.16 27.945 58.32 28.215 ;
     RECT  2.16 28.485 58.32 28.755 ;
     RECT  2.16 29.025 58.32 29.295 ;
     RECT  2.16 29.565 58.32 29.835 ;
     RECT  2.16 30.105 58.32 30.375 ;
     RECT  2.16 30.645 58.32 30.915 ;
     RECT  2.16 31.185 58.32 31.455 ;
     RECT  2.16 31.725 58.32 31.995 ;
     RECT  2.16 32.265 58.32 32.535 ;
     RECT  2.16 32.805 58.32 33.075 ;
     RECT  2.16 33.345 58.32 33.615 ;
     RECT  2.16 33.885 58.32 34.155 ;
     RECT  2.16 34.425 58.32 34.695 ;
     RECT  2.16 34.965 58.32 35.235 ;
     RECT  2.16 35.505 58.32 35.775 ;
     RECT  2.16 36.045 58.32 36.315 ;
     RECT  2.16 36.585 58.32 36.855 ;
     RECT  2.16 37.125 58.32 37.395 ;
     RECT  2.16 37.665 58.32 37.935 ;
     RECT  2.16 38.205 58.32 38.475 ;
     RECT  2.16 38.745 58.32 39.015 ;
     RECT  2.16 39.285 58.32 39.555 ;
     RECT  2.16 39.825 58.32 40.095 ;
     RECT  2.16 40.365 58.32 40.635 ;
     RECT  2.16 40.905 58.32 41.175 ;
     RECT  2.16 41.445 58.32 41.715 ;
     RECT  2.16 41.985 58.32 42.255 ;
     RECT  2.16 42.525 58.32 42.795 ;
     RECT  2.16 43.065 58.32 43.335 ;
     RECT  2.16 43.605 58.32 43.875 ;
     RECT  2.16 44.145 58.32 44.415 ;
     RECT  2.16 44.685 58.32 44.955 ;
     RECT  2.16 45.225 58.32 45.495 ;
     RECT  2.16 45.765 58.32 46.035 ;
     RECT  2.16 46.305 58.32 46.575 ;
     RECT  2.16 46.845 58.32 47.115 ;
     RECT  2.16 47.385 58.32 47.655 ;
     RECT  2.16 47.925 58.32 48.195 ;
     RECT  2.16 48.465 58.32 48.735 ;
     RECT  2.16 49.005 58.32 49.275 ;
     RECT  2.16 49.545 58.32 49.815 ;
     RECT  2.16 50.085 58.32 50.355 ;
     RECT  2.16 50.625 58.32 50.895 ;
     RECT  2.16 51.165 58.32 51.435 ;
     RECT  2.16 51.705 58.32 51.975 ;
     RECT  2.16 52.245 58.32 52.515 ;
     RECT  2.16 52.785 58.32 53.055 ;
     RECT  2.16 53.325 58.32 53.595 ;
     RECT  2.16 53.865 58.32 54.135 ;
     RECT  2.16 54.405 58.32 54.675 ;
     RECT  2.16 54.945 58.32 55.215 ;
     RECT  2.16 55.485 58.32 55.755 ;
     RECT  2.16 56.025 58.32 56.295 ;
     RECT  2.16 56.565 58.32 56.835 ;
     RECT  2.16 57.105 58.32 57.375 ;
     RECT  2.16 57.645 58.32 57.915 ;
     RECT  2.16 58.185 58.32 58.32 ;
    LAYER RVTP ;
     RECT  2.16 2.295 58.32 2.565 ;
     RECT  2.16 2.835 58.32 3.105 ;
     RECT  2.16 3.375 58.32 3.645 ;
     RECT  2.16 3.915 58.32 4.185 ;
     RECT  2.16 4.455 58.32 4.725 ;
     RECT  2.16 4.995 58.32 5.265 ;
     RECT  2.16 5.535 58.32 5.805 ;
     RECT  2.16 6.075 58.32 6.345 ;
     RECT  2.16 6.615 58.32 6.885 ;
     RECT  2.16 7.155 58.32 7.425 ;
     RECT  2.16 7.695 58.32 7.965 ;
     RECT  2.16 8.235 58.32 8.505 ;
     RECT  2.16 8.775 58.32 9.045 ;
     RECT  2.16 9.315 58.32 9.585 ;
     RECT  2.16 9.855 58.32 10.125 ;
     RECT  2.16 10.395 58.32 10.665 ;
     RECT  2.16 10.935 58.32 11.205 ;
     RECT  2.16 11.475 58.32 11.745 ;
     RECT  2.16 12.015 58.32 12.285 ;
     RECT  2.16 12.555 58.32 12.825 ;
     RECT  2.16 13.095 58.32 13.365 ;
     RECT  2.16 13.635 58.32 13.905 ;
     RECT  2.16 14.175 58.32 14.445 ;
     RECT  2.16 14.715 58.32 14.985 ;
     RECT  2.16 15.255 58.32 15.525 ;
     RECT  2.16 15.795 58.32 16.065 ;
     RECT  2.16 16.335 58.32 16.605 ;
     RECT  2.16 16.875 58.32 17.145 ;
     RECT  2.16 17.415 58.32 17.685 ;
     RECT  2.16 17.955 58.32 18.225 ;
     RECT  2.16 18.495 58.32 18.765 ;
     RECT  2.16 19.035 58.32 19.305 ;
     RECT  2.16 19.575 58.32 19.845 ;
     RECT  2.16 20.115 58.32 20.385 ;
     RECT  2.16 20.655 58.32 20.925 ;
     RECT  2.16 21.195 58.32 21.465 ;
     RECT  2.16 21.735 58.32 22.005 ;
     RECT  2.16 22.275 58.32 22.545 ;
     RECT  2.16 22.815 58.32 23.085 ;
     RECT  2.16 23.355 58.32 23.625 ;
     RECT  2.16 23.895 58.32 24.165 ;
     RECT  2.16 24.435 58.32 24.705 ;
     RECT  2.16 24.975 58.32 25.245 ;
     RECT  2.16 25.515 58.32 25.785 ;
     RECT  2.16 26.055 58.32 26.325 ;
     RECT  2.16 26.595 58.32 26.865 ;
     RECT  2.16 27.135 58.32 27.405 ;
     RECT  2.16 27.675 58.32 27.945 ;
     RECT  2.16 28.215 58.32 28.485 ;
     RECT  2.16 28.755 58.32 29.025 ;
     RECT  2.16 29.295 58.32 29.565 ;
     RECT  2.16 29.835 58.32 30.105 ;
     RECT  2.16 30.375 58.32 30.645 ;
     RECT  2.16 30.915 58.32 31.185 ;
     RECT  2.16 31.455 58.32 31.725 ;
     RECT  2.16 31.995 58.32 32.265 ;
     RECT  2.16 32.535 58.32 32.805 ;
     RECT  2.16 33.075 58.32 33.345 ;
     RECT  2.16 33.615 58.32 33.885 ;
     RECT  2.16 34.155 58.32 34.425 ;
     RECT  2.16 34.695 58.32 34.965 ;
     RECT  2.16 35.235 58.32 35.505 ;
     RECT  2.16 35.775 58.32 36.045 ;
     RECT  2.16 36.315 58.32 36.585 ;
     RECT  2.16 36.855 58.32 37.125 ;
     RECT  2.16 37.395 58.32 37.665 ;
     RECT  2.16 37.935 58.32 38.205 ;
     RECT  2.16 38.475 58.32 38.745 ;
     RECT  2.16 39.015 58.32 39.285 ;
     RECT  2.16 39.555 58.32 39.825 ;
     RECT  2.16 40.095 58.32 40.365 ;
     RECT  2.16 40.635 58.32 40.905 ;
     RECT  2.16 41.175 58.32 41.445 ;
     RECT  2.16 41.715 58.32 41.985 ;
     RECT  2.16 42.255 58.32 42.525 ;
     RECT  2.16 42.795 58.32 43.065 ;
     RECT  2.16 43.335 58.32 43.605 ;
     RECT  2.16 43.875 58.32 44.145 ;
     RECT  2.16 44.415 58.32 44.685 ;
     RECT  2.16 44.955 58.32 45.225 ;
     RECT  2.16 45.495 58.32 45.765 ;
     RECT  2.16 46.035 58.32 46.305 ;
     RECT  2.16 46.575 58.32 46.845 ;
     RECT  2.16 47.115 58.32 47.385 ;
     RECT  2.16 47.655 58.32 47.925 ;
     RECT  2.16 48.195 58.32 48.465 ;
     RECT  2.16 48.735 58.32 49.005 ;
     RECT  2.16 49.275 58.32 49.545 ;
     RECT  2.16 49.815 58.32 50.085 ;
     RECT  2.16 50.355 58.32 50.625 ;
     RECT  2.16 50.895 58.32 51.165 ;
     RECT  2.16 51.435 58.32 51.705 ;
     RECT  2.16 51.975 58.32 52.245 ;
     RECT  2.16 52.515 58.32 52.785 ;
     RECT  2.16 53.055 58.32 53.325 ;
     RECT  2.16 53.595 58.32 53.865 ;
     RECT  2.16 54.135 58.32 54.405 ;
     RECT  2.16 54.675 58.32 54.945 ;
     RECT  2.16 55.215 58.32 55.485 ;
     RECT  2.16 55.755 58.32 56.025 ;
     RECT  2.16 56.295 58.32 56.565 ;
     RECT  2.16 56.835 58.32 57.105 ;
     RECT  2.16 57.375 58.32 57.645 ;
     RECT  2.16 57.915 58.32 58.185 ;
    LAYER M1 ;
     RECT  2.16 2.151 58.32 58.329 ;
    LAYER M2 ;
     RECT  0.103 12.456 0.535 13.014 ;
     RECT  0.535 12.456 2.16 13.392 ;
     RECT  0.535 16.344 2.16 16.362 ;
     RECT  2.16 2.151 11.983 58.329 ;
     RECT  11.983 2.106 12.335 58.329 ;
     RECT  15.187 1.152 15.287 1.359 ;
     RECT  12.335 2.151 15.295 58.329 ;
     RECT  15.287 1.26 15.359 1.359 ;
     RECT  15.295 2.106 16.223 58.329 ;
     RECT  17.995 1.152 18.095 1.17 ;
     RECT  16.223 2.151 18.787 58.329 ;
     RECT  18.787 2.106 19.075 58.329 ;
     RECT  19.075 2.034 19.859 58.329 ;
     RECT  19.859 2.151 21.775 58.329 ;
     RECT  21.775 2.106 22.531 58.329 ;
     RECT  22.531 2.034 22.991 58.329 ;
     RECT  22.991 2.106 25.583 58.329 ;
     RECT  25.583 2.151 27.535 58.329 ;
     RECT  27.535 2.106 27.607 58.329 ;
     RECT  27.607 2.034 28.823 58.329 ;
     RECT  32.575 1.152 32.675 1.17 ;
     RECT  28.823 2.151 42.475 58.329 ;
     RECT  42.475 2.106 43.331 58.329 ;
     RECT  43.331 2.151 44.383 58.329 ;
     RECT  44.383 2.106 44.843 58.329 ;
     RECT  44.843 2.151 46.759 58.329 ;
     RECT  46.759 2.106 48.191 58.329 ;
     RECT  48.191 2.151 49.567 58.329 ;
     RECT  49.567 2.106 49.919 58.329 ;
     RECT  49.919 2.151 51.151 58.329 ;
     RECT  51.151 2.106 52.331 58.329 ;
     RECT  52.331 2.151 58.32 58.329 ;
     RECT  58.32 19.044 58.703 57.564 ;
     RECT  58.703 56.88 58.739 57.024 ;
     RECT  58.703 19.044 59.279 56.052 ;
     RECT  59.279 24.75 59.315 34.452 ;
     RECT  59.279 36.666 59.315 40.59 ;
     RECT  59.279 51.444 59.315 56.052 ;
     RECT  59.315 51.48 59.819 56.052 ;
     RECT  59.279 19.044 59.855 22.608 ;
     RECT  59.315 24.75 59.855 29.394 ;
     RECT  59.315 33.426 59.855 34.452 ;
     RECT  59.279 41.994 59.855 46.404 ;
     RECT  59.819 51.48 59.855 54.09 ;
     RECT  59.819 55.152 59.855 56.052 ;
     RECT  58.739 57.006 59.855 57.024 ;
     RECT  59.855 19.044 59.891 22.338 ;
     RECT  59.855 24.75 59.891 26.784 ;
     RECT  59.855 28.026 59.891 28.044 ;
     RECT  59.855 29.034 59.891 29.394 ;
     RECT  59.315 30.456 59.891 30.474 ;
     RECT  59.315 31.23 59.891 32.634 ;
     RECT  59.855 33.426 59.891 34.254 ;
     RECT  59.279 35.208 59.891 35.874 ;
     RECT  59.315 36.666 59.891 40.356 ;
     RECT  59.855 41.994 59.891 42.084 ;
     RECT  59.855 42.876 59.891 45.594 ;
     RECT  59.855 46.386 59.891 46.404 ;
     RECT  59.279 47.196 59.891 50.652 ;
     RECT  59.855 53.334 59.891 54.09 ;
     RECT  59.855 55.152 59.891 55.854 ;
     RECT  59.891 29.376 59.927 29.394 ;
     RECT  59.891 36.864 59.927 36.882 ;
     RECT  59.891 38.016 59.927 38.034 ;
     RECT  59.855 51.48 59.927 52.236 ;
     RECT  59.891 39.834 60.359 40.356 ;
     RECT  59.891 20.196 60.395 22.032 ;
     RECT  59.279 23.634 60.395 23.652 ;
     RECT  59.891 25.29 60.395 26.784 ;
     RECT  59.891 31.23 60.395 32.292 ;
     RECT  59.891 33.426 60.395 33.444 ;
     RECT  59.891 35.208 60.395 35.226 ;
     RECT  60.359 39.834 60.395 40.194 ;
     RECT  59.891 42.066 60.395 42.084 ;
     RECT  59.891 43.074 60.395 44.244 ;
     RECT  59.891 45.576 60.395 45.594 ;
     RECT  59.891 48.402 60.395 48.42 ;
     RECT  59.891 50.058 60.395 50.652 ;
     RECT  59.927 51.714 60.395 52.236 ;
     RECT  59.891 53.37 60.395 54.09 ;
     RECT  59.891 55.224 60.395 55.854 ;
     RECT  60.395 54.072 60.467 54.09 ;
     RECT  60.395 55.836 60.467 55.854 ;
    LAYER M3 ;
     RECT  17.784 0.091 17.802 0.139 ;
     RECT  22.572 0.091 23.67 0.139 ;
     RECT  29.844 0.091 30.33 0.139 ;
     RECT  31.212 0.091 31.23 0.139 ;
     RECT  35.352 0.091 37.71 0.139 ;
     RECT  39.708 0.091 39.726 0.139 ;
     RECT  41.256 0.091 41.274 0.139 ;
     RECT  17.784 0.139 18.018 0.187 ;
     RECT  41.256 0.139 41.346 0.187 ;
     RECT  11.772 0.091 11.79 0.235 ;
     RECT  39.348 0.139 39.726 0.523 ;
     RECT  41.22 0.187 41.346 0.523 ;
     RECT  42.804 0.091 42.822 0.523 ;
     RECT  44.172 0.091 44.19 0.523 ;
     RECT  48.708 0.091 49.122 0.523 ;
     RECT  52.056 0.091 52.074 0.523 ;
     RECT  17.712 0.187 18.018 0.571 ;
     RECT  25.776 0.091 26.334 0.571 ;
     RECT  27.108 0.091 27.126 0.571 ;
     RECT  28.08 0.091 28.098 0.571 ;
     RECT  33.372 0.091 34.398 0.571 ;
     RECT  35.352 0.139 38.142 0.571 ;
     RECT  42.696 0.523 42.894 0.571 ;
     RECT  46.44 0.091 47.934 0.571 ;
     RECT  50.292 0.091 50.31 0.571 ;
     RECT  10.08 0.091 10.098 1.099 ;
     RECT  11.34 0.235 11.79 1.099 ;
     RECT  12.852 0.571 13.914 1.099 ;
     RECT  15.336 0.091 15.966 1.099 ;
     RECT  20.268 0.523 20.286 1.099 ;
     RECT  21.276 0.091 21.294 1.099 ;
     RECT  22.5 0.139 23.67 1.099 ;
     RECT  43.92 0.523 44.19 1.099 ;
     RECT  52.056 0.523 52.146 1.099 ;
     RECT  15.264 1.099 15.966 1.147 ;
     RECT  32.58 0.571 34.398 1.147 ;
     RECT  35.352 0.571 38.394 1.147 ;
     RECT  39.348 0.523 41.346 1.147 ;
     RECT  46.044 0.571 47.934 1.147 ;
     RECT  48.708 0.523 49.158 1.147 ;
     RECT  49.932 0.571 50.31 1.147 ;
     RECT  35.28 1.147 38.394 1.195 ;
     RECT  25.02 1.147 25.038 1.243 ;
     RECT  25.776 0.571 28.098 1.243 ;
     RECT  49.932 1.147 50.634 1.627 ;
     RECT  51.552 1.099 52.146 1.627 ;
     RECT  10.08 1.099 10.278 1.723 ;
     RECT  11.34 1.099 13.914 1.723 ;
     RECT  15.192 1.147 15.966 1.723 ;
     RECT  17.712 0.571 18.198 1.723 ;
     RECT  19.548 1.099 20.286 1.723 ;
     RECT  21.276 1.099 21.402 1.723 ;
     RECT  22.176 1.099 23.67 1.723 ;
     RECT  25.02 1.243 28.098 1.723 ;
     RECT  29.844 0.139 31.23 1.723 ;
     RECT  32.112 1.147 34.398 1.723 ;
     RECT  35.136 1.195 38.394 1.723 ;
     RECT  39.168 1.147 41.346 1.723 ;
     RECT  42.624 0.571 42.894 1.723 ;
     RECT  43.92 1.099 44.73 1.723 ;
     RECT  46.044 1.147 49.158 1.723 ;
     RECT  49.932 1.627 52.146 1.723 ;
     RECT  9.936 1.723 18.378 1.771 ;
     RECT  19.152 1.723 23.67 1.771 ;
     RECT  24.48 1.723 28.098 1.771 ;
     RECT  29.088 1.723 34.398 1.771 ;
     RECT  35.136 1.723 52.866 1.771 ;
     RECT  35.136 1.771 53.37 1.819 ;
     RECT  9.936 1.771 34.398 2.143 ;
     RECT  35.136 1.819 53.622 2.143 ;
     RECT  9.936 2.143 53.622 2.227 ;
     RECT  2.415 2.143 2.505 2.413 ;
     RECT  7.815 2.143 7.905 2.413 ;
     RECT  56.415 2.143 56.505 2.413 ;
     RECT  9.756 2.227 53.622 2.641 ;
     RECT  9.756 2.641 54.234 2.759 ;
     RECT  9 3.145 9.018 3.299 ;
     RECT  9.756 2.759 54.126 3.343 ;
     RECT  9.144 3.343 54.126 3.605 ;
     RECT  9.9 3.605 54.126 3.721 ;
     RECT  9.9 3.721 54.378 3.839 ;
     RECT  9.9 3.839 54.306 3.875 ;
     RECT  9.144 3.605 9.162 4.109 ;
     RECT  9.9 3.875 54.126 4.415 ;
     RECT  9.972 4.415 54.126 5.297 ;
     RECT  9.972 5.297 53.946 5.495 ;
     RECT  10.008 5.495 53.946 6.035 ;
     RECT  14.76 6.035 53.946 6.179 ;
     RECT  10.008 6.035 14.022 6.377 ;
     RECT  14.832 6.179 53.946 7.223 ;
     RECT  17.532 7.223 53.946 7.349 ;
     RECT  17.676 7.349 53.946 7.385 ;
     RECT  17.748 7.385 53.946 7.465 ;
     RECT  14.832 7.223 16.506 8.131 ;
     RECT  17.748 7.465 54.558 8.131 ;
     RECT  14.832 8.131 54.558 8.203 ;
     RECT  55.332 7.195 55.35 8.203 ;
     RECT  10.008 6.377 13.95 8.311 ;
     RECT  14.832 8.203 55.35 8.311 ;
     RECT  10.008 8.311 55.35 8.429 ;
     RECT  16.488 8.429 55.35 8.501 ;
     RECT  18.396 8.501 55.35 8.537 ;
     RECT  18.396 8.537 43.866 8.699 ;
     RECT  10.008 8.429 10.098 8.879 ;
     RECT  10.08 8.879 10.098 8.969 ;
     RECT  18.396 8.699 36.918 8.969 ;
     RECT  44.748 8.537 55.35 9.013 ;
     RECT  10.836 8.429 15.39 9.113 ;
     RECT  56.415 2.413 56.697 9.121 ;
     RECT  37.8 8.699 43.866 9.275 ;
     RECT  18.504 8.969 36.918 9.625 ;
     RECT  18.504 9.625 36.99 9.661 ;
     RECT  37.8 9.275 43.794 9.661 ;
     RECT  44.748 9.013 55.458 9.689 ;
     RECT  44.748 9.689 44.874 9.815 ;
     RECT  18.504 9.661 43.794 10.121 ;
     RECT  33.192 10.121 43.794 10.229 ;
     RECT  44.856 9.815 44.874 10.391 ;
     RECT  33.336 10.229 43.794 10.427 ;
     RECT  45.615 9.689 55.458 10.589 ;
     RECT  5.976 10.597 5.994 10.633 ;
     RECT  47.088 10.589 55.458 10.661 ;
     RECT  5.148 10.597 5.166 10.741 ;
     RECT  5.976 10.633 6.174 10.741 ;
     RECT  5.148 10.741 6.21 10.795 ;
     RECT  5.148 10.795 6.246 10.831 ;
     RECT  7.815 2.413 8.097 10.939 ;
     RECT  7.815 10.939 8.73 10.975 ;
     RECT  4.572 10.831 6.246 10.987 ;
     RECT  2.415 2.413 2.697 11.011 ;
     RECT  4.5 10.987 6.246 11.011 ;
     RECT  7.74 10.975 8.73 11.011 ;
     RECT  2.415 11.011 3.114 11.137 ;
     RECT  4.284 11.011 9.054 11.137 ;
     RECT  2.415 11.137 9.054 11.515 ;
     RECT  2.415 11.515 9.198 11.551 ;
     RECT  2.415 11.551 9.63 11.849 ;
     RECT  2.415 11.849 9.414 12.829 ;
     RECT  2.304 12.829 9.414 12.991 ;
     RECT  0.108 12.451 0.126 13.133 ;
     RECT  0.54 13.369 0.558 13.709 ;
     RECT  10.332 13.981 10.35 14.099 ;
     RECT  2.304 12.991 9.522 14.179 ;
     RECT  2.304 14.179 9.954 14.917 ;
     RECT  2.304 14.917 10.026 15.061 ;
     RECT  2.304 15.061 10.566 15.323 ;
     RECT  2.304 15.323 10.134 15.827 ;
     RECT  2.304 15.827 9.702 16.025 ;
     RECT  2.304 16.025 8.946 16.123 ;
     RECT  2.268 16.123 8.946 16.259 ;
     RECT  9.684 16.025 9.702 16.439 ;
     RECT  0.54 16.339 0.558 16.589 ;
     RECT  2.304 16.259 8.946 16.807 ;
     RECT  2.304 16.807 9.594 16.979 ;
     RECT  2.34 16.979 9.594 17.069 ;
     RECT  2.415 17.069 9.378 17.483 ;
     RECT  3.528 17.483 9.378 17.609 ;
     RECT  3.528 17.609 8.946 17.681 ;
     RECT  3.528 17.681 8.55 18.149 ;
     RECT  47.376 10.661 55.458 18.535 ;
     RECT  7.815 18.149 8.55 18.571 ;
     RECT  47.376 18.535 55.602 18.571 ;
     RECT  56.34 9.121 56.697 18.571 ;
     RECT  7.815 18.571 8.586 18.697 ;
     RECT  7.815 18.697 8.73 18.841 ;
     RECT  47.376 18.571 56.697 18.841 ;
     RECT  3.528 18.149 6.858 18.931 ;
     RECT  3.528 18.931 7.074 18.967 ;
     RECT  7.815 18.841 9.126 18.967 ;
     RECT  3.528 18.967 9.126 19.103 ;
     RECT  2.415 17.483 2.697 19.111 ;
     RECT  47.376 18.841 57.078 19.111 ;
     RECT  58.14 19.111 58.158 19.181 ;
     RECT  59.868 19.039 59.886 19.201 ;
     RECT  47.376 19.111 57.186 19.229 ;
     RECT  2.415 19.111 3.258 19.277 ;
     RECT  4.032 19.103 8.586 19.277 ;
     RECT  59.292 19.201 59.886 19.291 ;
     RECT  4.176 19.277 8.586 19.301 ;
     RECT  59.256 19.291 59.886 19.723 ;
     RECT  58.68 19.723 59.886 19.769 ;
     RECT  58.716 19.769 59.886 19.901 ;
     RECT  58.716 19.901 58.734 20.045 ;
     RECT  59.832 19.901 59.886 20.155 ;
     RECT  47.376 19.229 57.15 20.191 ;
     RECT  4.32 19.301 8.097 20.309 ;
     RECT  59.832 20.155 60.39 20.345 ;
     RECT  4.608 20.309 8.097 20.381 ;
     RECT  47.376 20.191 57.33 20.389 ;
     RECT  47.376 20.389 57.402 20.425 ;
     RECT  4.896 20.381 8.097 20.615 ;
     RECT  4.896 20.615 6.966 20.723 ;
     RECT  5.04 20.723 6.858 20.849 ;
     RECT  5.364 20.849 6.858 20.885 ;
     RECT  47.376 20.425 57.546 21.119 ;
     RECT  2.415 19.277 2.697 21.433 ;
     RECT  7.776 20.615 8.097 21.499 ;
     RECT  2.415 21.433 2.862 21.533 ;
     RECT  5.652 20.885 6.858 21.541 ;
     RECT  7.776 21.499 8.442 21.541 ;
     RECT  2.415 21.533 2.718 21.569 ;
     RECT  58.716 20.821 58.734 21.595 ;
     RECT  0.144 21.499 0.162 21.629 ;
     RECT  5.652 21.541 8.802 21.659 ;
     RECT  58.68 21.595 58.734 21.659 ;
     RECT  5.652 21.659 6.822 21.677 ;
     RECT  59.868 20.345 60.39 21.739 ;
     RECT  5.868 21.677 6.822 21.821 ;
     RECT  7.704 21.659 8.514 21.821 ;
     RECT  7.815 21.821 8.514 21.929 ;
     RECT  6.084 21.821 6.822 21.965 ;
     RECT  6.228 21.965 6.822 22.001 ;
     RECT  7.815 21.929 8.262 22.001 ;
     RECT  59.832 21.739 60.39 22.027 ;
     RECT  59.256 22.027 60.39 22.037 ;
     RECT  47.376 21.119 57.186 22.351 ;
     RECT  47.376 22.351 57.258 22.441 ;
     RECT  59.256 22.037 59.886 22.493 ;
     RECT  59.256 22.493 59.85 22.603 ;
     RECT  59.22 22.603 59.85 22.613 ;
     RECT  46.8 22.441 57.258 22.711 ;
     RECT  46.8 22.711 57.762 22.781 ;
     RECT  59.22 22.613 59.274 22.891 ;
     RECT  46.8 22.781 57.258 23.009 ;
     RECT  46.8 23.009 57.186 23.161 ;
     RECT  46.764 23.161 57.186 23.351 ;
     RECT  60.372 23.467 60.39 23.657 ;
     RECT  47.376 23.351 57.186 23.791 ;
     RECT  58.716 22.891 59.274 23.899 ;
     RECT  47.376 23.791 57.582 24.089 ;
     RECT  47.376 24.089 57.258 24.133 ;
     RECT  46.764 24.133 57.258 24.233 ;
     RECT  45.615 10.589 45.897 24.331 ;
     RECT  45.504 24.331 45.897 24.368 ;
     RECT  58.68 23.899 59.274 24.619 ;
     RECT  58.14 24.619 59.274 24.745 ;
     RECT  58.14 24.745 59.886 24.797 ;
     RECT  58.14 24.797 59.31 24.809 ;
     RECT  58.68 24.809 59.31 25.373 ;
     RECT  47.376 24.233 57.186 25.591 ;
     RECT  47.376 25.591 57.258 25.717 ;
     RECT  60.372 25.051 60.39 25.771 ;
     RECT  59.832 25.771 60.39 25.817 ;
     RECT  47.376 25.717 57.51 25.825 ;
     RECT  58.68 25.373 59.022 25.825 ;
     RECT  47.376 25.825 59.022 25.889 ;
     RECT  47.376 25.889 58.698 26.015 ;
     RECT  58.68 26.015 58.698 26.429 ;
     RECT  59.868 25.817 60.39 26.626 ;
     RECT  47.376 26.015 57.474 26.789 ;
     RECT  59.832 26.626 60.39 26.813 ;
     RECT  47.376 26.789 57.402 27.059 ;
     RECT  58.896 26.671 58.914 27.211 ;
     RECT  47.376 27.059 57.366 27.329 ;
     RECT  58.86 27.211 58.914 27.445 ;
     RECT  58.716 27.445 58.914 27.499 ;
     RECT  59.832 26.813 59.85 27.499 ;
     RECT  47.376 27.329 57.294 27.607 ;
     RECT  47.304 27.607 57.294 27.643 ;
     RECT  46.764 27.643 57.294 27.743 ;
     RECT  58.716 27.499 59.85 27.869 ;
     RECT  59.832 27.869 59.85 28.021 ;
     RECT  47.52 27.743 57.294 28.111 ;
     RECT  59.832 28.021 59.886 28.253 ;
     RECT  47.52 28.111 57.726 28.283 ;
     RECT  58.716 27.869 58.734 28.651 ;
     RECT  59.832 28.253 59.85 28.651 ;
     RECT  58.716 28.651 59.85 28.795 ;
     RECT  47.52 28.283 57.546 28.949 ;
     RECT  47.52 28.949 57.402 29.021 ;
     RECT  58.68 28.795 59.85 29.029 ;
     RECT  58.68 29.029 59.886 29.261 ;
     RECT  58.716 29.261 59.886 29.365 ;
     RECT  58.716 29.365 59.922 29.405 ;
     RECT  46.764 28.687 46.782 29.561 ;
     RECT  33.336 10.427 43.362 29.911 ;
     RECT  33.336 29.911 43.542 30.037 ;
     RECT  58.716 29.405 59.886 30.091 ;
     RECT  47.52 29.021 57.258 30.145 ;
     RECT  58.14 30.091 59.886 30.209 ;
     RECT  58.716 30.209 59.886 30.557 ;
     RECT  47.52 30.145 57.402 30.811 ;
     RECT  47.52 30.811 57.438 30.911 ;
     RECT  33.336 30.037 44.262 30.991 ;
     RECT  45.615 24.368 45.897 31.081 ;
     RECT  33.336 30.991 44.622 31.153 ;
     RECT  58.716 30.557 59.31 31.243 ;
     RECT  33.336 31.153 44.694 31.261 ;
     RECT  45.468 31.081 45.897 31.261 ;
     RECT  58.14 31.243 59.31 31.421 ;
     RECT  59.256 31.421 59.31 31.459 ;
     RECT  60.372 31.099 60.39 31.459 ;
     RECT  59.256 31.459 60.39 31.919 ;
     RECT  47.52 30.911 57.294 32.035 ;
     RECT  58.14 31.421 58.158 32.035 ;
     RECT  33.336 31.261 45.897 32.161 ;
     RECT  46.764 32.071 46.782 32.161 ;
     RECT  47.52 32.035 58.158 32.189 ;
     RECT  33.336 32.161 46.782 32.233 ;
     RECT  47.52 32.189 57.294 32.233 ;
     RECT  58.14 32.189 58.158 32.233 ;
     RECT  59.868 31.919 60.39 32.297 ;
     RECT  33.336 32.233 57.294 32.369 ;
     RECT  58.14 32.233 58.194 32.369 ;
     RECT  58.176 32.369 58.194 32.395 ;
     RECT  58.176 32.395 58.698 32.459 ;
     RECT  58.176 32.459 58.194 32.573 ;
     RECT  59.868 32.297 59.886 32.683 ;
     RECT  59.256 32.683 59.886 32.861 ;
     RECT  33.336 32.369 46.674 33.151 ;
     RECT  47.52 32.369 57.294 33.151 ;
     RECT  33.336 33.151 57.294 33.259 ;
     RECT  59.256 32.861 59.31 33.259 ;
     RECT  59.22 33.259 59.31 33.377 ;
     RECT  60.372 33.403 60.39 33.449 ;
     RECT  33.336 33.259 57.51 33.547 ;
     RECT  58.788 33.541 58.806 33.581 ;
     RECT  33.336 33.547 57.546 33.647 ;
     RECT  59.868 33.583 60.318 34.109 ;
     RECT  58.68 33.691 58.698 34.157 ;
     RECT  59.868 34.109 59.886 34.411 ;
     RECT  59.832 34.411 59.886 34.589 ;
     RECT  33.336 33.647 57.33 34.771 ;
     RECT  58.14 34.267 58.158 34.771 ;
     RECT  33.336 34.771 58.158 35.231 ;
     RECT  60.372 35.131 60.39 35.231 ;
     RECT  58.14 35.231 58.158 35.269 ;
     RECT  59.256 34.699 59.274 35.269 ;
     RECT  33.336 35.231 57.33 35.429 ;
     RECT  58.14 35.269 59.274 35.851 ;
     RECT  58.14 35.851 59.886 35.885 ;
     RECT  58.68 35.885 59.886 36.029 ;
     RECT  33.336 35.429 57.258 36.391 ;
     RECT  33.336 36.391 57.582 36.625 ;
     RECT  33.336 36.625 57.834 36.715 ;
     RECT  59.256 36.029 59.886 36.859 ;
     RECT  33.336 36.715 58.158 36.959 ;
     RECT  59.256 36.859 59.922 37.181 ;
     RECT  59.256 37.181 59.886 37.291 ;
     RECT  58.68 37.291 59.886 37.328 ;
     RECT  33.336 36.959 57.87 37.625 ;
     RECT  59.256 37.328 59.886 37.859 ;
     RECT  58.14 37.867 58.158 37.967 ;
     RECT  59.868 37.859 59.886 38.011 ;
     RECT  59.868 38.011 59.922 38.333 ;
     RECT  33.336 37.625 57.258 38.641 ;
     RECT  58.716 38.101 58.734 39.019 ;
     RECT  59.868 38.333 59.886 39.019 ;
     RECT  33.336 38.641 57.726 39.055 ;
     RECT  33.336 39.055 57.762 39.209 ;
     RECT  33.336 39.209 57.618 39.281 ;
     RECT  58.716 39.019 59.886 39.289 ;
     RECT  33.336 39.281 57.402 39.293 ;
     RECT  33.336 39.293 57.366 39.317 ;
     RECT  58.68 39.289 59.886 39.341 ;
     RECT  59.292 39.341 59.886 39.739 ;
     RECT  33.336 39.317 57.258 40.019 ;
     RECT  59.292 39.739 60.39 40.199 ;
     RECT  59.292 40.199 60.354 40.349 ;
     RECT  60.336 40.349 60.354 40.361 ;
     RECT  59.292 40.349 59.31 40.459 ;
     RECT  59.256 40.459 59.31 40.603 ;
     RECT  58.68 40.603 59.31 40.781 ;
     RECT  58.68 40.781 59.274 40.891 ;
     RECT  58.14 40.891 59.274 41.099 ;
     RECT  33.336 40.019 57.222 41.611 ;
     RECT  33.336 41.611 57.33 41.647 ;
     RECT  58.14 41.099 58.158 41.747 ;
     RECT  33.336 41.647 57.402 41.755 ;
     RECT  59.256 41.099 59.274 41.989 ;
     RECT  33.336 41.755 57.942 42.029 ;
     RECT  59.256 41.989 59.886 42.043 ;
     RECT  33.336 42.029 57.87 42.089 ;
     RECT  59.256 42.043 60.39 42.089 ;
     RECT  11.628 9.113 15.39 42.295 ;
     RECT  59.256 42.089 59.886 42.421 ;
     RECT  18.504 10.121 32.418 42.457 ;
     RECT  11.592 42.295 15.39 42.493 ;
     RECT  58.716 42.421 59.886 42.509 ;
     RECT  33.336 42.089 57.15 42.557 ;
     RECT  59.256 42.509 59.886 42.557 ;
     RECT  11.448 42.493 15.39 42.601 ;
     RECT  18.468 42.457 32.418 42.719 ;
     RECT  59.832 42.557 59.886 42.907 ;
     RECT  18.468 42.719 32.058 43.033 ;
     RECT  18.432 43.033 32.058 43.061 ;
     RECT  10.512 42.763 10.53 43.141 ;
     RECT  59.832 42.907 60.39 43.339 ;
     RECT  10.512 43.141 10.674 43.375 ;
     RECT  10.44 43.375 10.674 43.501 ;
     RECT  33.336 42.557 57.114 43.501 ;
     RECT  59.256 43.339 60.39 43.529 ;
     RECT  10.332 43.501 10.674 43.573 ;
     RECT  11.412 42.601 15.39 43.573 ;
     RECT  58.14 43.483 58.158 43.709 ;
     RECT  33.336 43.501 57.222 43.771 ;
     RECT  33.336 43.771 57.258 43.879 ;
     RECT  33.336 43.879 57.33 43.979 ;
     RECT  10.332 43.573 15.39 44.185 ;
     RECT  59.868 43.529 60.39 44.249 ;
     RECT  10.188 44.185 15.39 44.477 ;
     RECT  33.336 43.979 57.186 44.761 ;
     RECT  58.68 43.915 58.698 44.779 ;
     RECT  59.868 44.249 59.886 44.779 ;
     RECT  58.68 44.779 59.886 44.879 ;
     RECT  10.44 44.477 15.39 44.987 ;
     RECT  33.336 44.761 57.258 44.995 ;
     RECT  59.868 44.879 59.886 45.355 ;
     RECT  59.868 45.355 60.39 45.599 ;
     RECT  58.68 44.879 58.698 45.841 ;
     RECT  58.68 45.841 58.734 45.959 ;
     RECT  33.336 44.995 57.618 46.201 ;
     RECT  10.512 44.987 15.39 46.219 ;
     RECT  33.336 46.201 57.978 46.301 ;
     RECT  58.716 45.959 58.734 46.363 ;
     RECT  59.832 46.219 59.85 46.363 ;
     RECT  33.336 46.301 57.618 46.373 ;
     RECT  58.716 46.363 59.85 46.381 ;
     RECT  10.476 46.219 15.39 46.471 ;
     RECT  33.336 46.373 57.258 46.499 ;
     RECT  58.716 46.381 59.886 46.541 ;
     RECT  18.432 43.061 23.094 47.281 ;
     RECT  23.976 43.061 32.058 47.281 ;
     RECT  33.336 46.499 57.186 47.281 ;
     RECT  59.256 46.541 59.886 47.281 ;
     RECT  33.336 47.281 57.33 47.381 ;
     RECT  58.716 47.281 59.886 47.425 ;
     RECT  58.68 47.425 59.886 47.515 ;
     RECT  58.14 47.515 59.886 47.759 ;
     RECT  33.336 47.381 57.186 48.127 ;
     RECT  10.44 46.471 15.39 48.199 ;
     RECT  58.14 47.759 58.158 48.271 ;
     RECT  59.292 47.759 59.886 48.379 ;
     RECT  58.104 48.271 58.158 48.425 ;
     RECT  59.292 48.379 60.39 48.425 ;
     RECT  59.292 48.425 59.886 48.661 ;
     RECT  33.336 48.127 57.294 48.715 ;
     RECT  10.404 48.199 15.39 48.929 ;
     RECT  58.716 48.661 59.886 48.929 ;
     RECT  33.336 48.715 57.546 48.965 ;
     RECT  33.336 48.965 57.258 49.001 ;
     RECT  58.716 48.929 58.734 49.171 ;
     RECT  33.336 49.001 57.15 49.565 ;
     RECT  58.68 49.171 58.734 49.675 ;
     RECT  59.868 48.929 59.886 49.675 ;
     RECT  10.44 48.929 15.39 49.855 ;
     RECT  58.68 49.675 59.886 49.963 ;
     RECT  10.332 49.855 15.39 50.279 ;
     RECT  7.815 22.001 8.097 50.359 ;
     RECT  33.336 49.565 57.078 50.431 ;
     RECT  9.396 50.431 9.558 50.477 ;
     RECT  18.432 47.281 32.058 50.521 ;
     RECT  9.54 50.477 9.558 50.549 ;
     RECT  33.336 50.431 57.294 50.549 ;
     RECT  10.404 50.279 15.39 50.585 ;
     RECT  33.336 50.549 57.222 50.585 ;
     RECT  10.548 50.585 15.39 50.621 ;
     RECT  58.68 49.963 60.39 50.657 ;
     RECT  58.68 50.657 59.886 50.717 ;
     RECT  58.68 50.717 59.31 51.161 ;
     RECT  33.336 50.585 57.078 51.331 ;
     RECT  33.336 51.331 57.582 51.403 ;
     RECT  16.956 50.629 16.974 51.439 ;
     RECT  59.22 51.161 59.31 51.475 ;
     RECT  33.336 51.403 57.618 51.511 ;
     RECT  59.22 51.475 59.922 51.547 ;
     RECT  33.336 51.511 57.762 51.673 ;
     RECT  10.584 50.621 15.39 51.745 ;
     RECT  33.336 51.673 58.014 51.773 ;
     RECT  59.22 51.547 60.39 51.809 ;
     RECT  10.548 51.745 15.39 52.015 ;
     RECT  10.44 52.015 15.39 52.051 ;
     RECT  16.884 51.439 16.974 52.051 ;
     RECT  18 50.521 32.058 52.051 ;
     RECT  59.832 51.809 60.39 52.241 ;
     RECT  7.815 50.359 8.262 52.321 ;
     RECT  10.404 52.051 15.39 52.321 ;
     RECT  10.404 52.321 15.714 52.411 ;
     RECT  9.54 52.411 15.714 52.519 ;
     RECT  9.252 52.519 15.714 52.555 ;
     RECT  9.036 52.555 15.714 52.681 ;
     RECT  59.832 52.241 59.922 52.699 ;
     RECT  9.036 52.681 15.786 52.789 ;
     RECT  58.68 52.267 58.698 52.889 ;
     RECT  9.036 52.789 16.11 53.059 ;
     RECT  16.884 52.051 32.058 53.059 ;
     RECT  9.036 53.059 32.058 53.123 ;
     RECT  59.796 52.699 59.922 53.131 ;
     RECT  58.716 53.131 59.922 53.275 ;
     RECT  9.108 53.123 32.058 53.321 ;
     RECT  9.18 53.321 32.058 53.519 ;
     RECT  9.432 53.519 32.058 53.591 ;
     RECT  9.612 53.591 32.058 53.627 ;
     RECT  33.336 51.773 57.762 53.761 ;
     RECT  33.336 53.761 57.978 53.869 ;
     RECT  58.716 53.275 60.39 53.869 ;
     RECT  33.336 53.869 60.39 54.029 ;
     RECT  59.256 54.029 60.39 54.067 ;
     RECT  7.524 52.321 8.262 54.373 ;
     RECT  33.336 54.029 58.158 54.509 ;
     RECT  7.524 54.373 8.514 54.571 ;
     RECT  7.524 54.571 8.91 54.607 ;
     RECT  9.684 53.627 32.058 54.607 ;
     RECT  7.164 54.607 32.058 54.841 ;
     RECT  6.588 54.841 32.058 54.893 ;
     RECT  59.256 54.067 60.462 54.985 ;
     RECT  58.68 54.985 60.462 55.049 ;
     RECT  33.336 54.509 57.762 55.111 ;
     RECT  33.192 55.111 57.762 55.139 ;
     RECT  33.192 55.139 33.714 55.255 ;
     RECT  59.796 55.049 60.462 55.325 ;
     RECT  33.048 55.255 33.714 55.381 ;
     RECT  6.732 54.893 32.058 55.72 ;
     RECT  32.868 55.381 33.714 55.72 ;
     RECT  58.68 55.049 58.698 55.831 ;
     RECT  59.832 55.325 60.462 55.859 ;
     RECT  59.832 55.859 60.39 55.901 ;
     RECT  6.732 55.72 33.714 56.065 ;
     RECT  34.452 55.139 57.762 56.065 ;
     RECT  6.624 56.065 57.762 56.101 ;
     RECT  58.68 55.831 58.734 56.101 ;
     RECT  6.624 56.101 58.734 56.189 ;
     RECT  6.624 56.189 57.762 56.335 ;
     RECT  6.552 56.335 57.762 56.569 ;
     RECT  6.444 56.569 57.762 56.731 ;
     RECT  58.68 56.189 58.734 56.909 ;
     RECT  59.832 55.901 59.85 57.029 ;
     RECT  6.3 56.731 57.762 57.173 ;
     RECT  6.3 57.173 56.898 57.299 ;
     RECT  57.744 57.173 57.762 57.299 ;
     RECT  6.3 57.299 31.266 57.415 ;
     RECT  6.012 57.415 31.266 57.569 ;
     RECT  32.148 57.299 56.898 57.569 ;
     RECT  58.68 56.909 58.698 57.569 ;
     RECT  2.415 21.569 2.697 58.067 ;
     RECT  32.148 57.569 56.697 58.067 ;
     RECT  32.148 58.067 56.574 58.109 ;
     RECT  32.148 58.109 56.505 58.145 ;
     RECT  6.012 57.569 31.086 58.157 ;
     RECT  32.148 58.145 55.278 58.157 ;
     RECT  6.192 58.157 31.086 58.205 ;
     RECT  32.436 58.157 35.478 58.205 ;
     RECT  36.216 58.157 46.818 58.205 ;
     RECT  47.808 58.157 52.686 58.205 ;
     RECT  53.496 58.157 55.278 58.205 ;
     RECT  30.744 58.205 30.834 58.217 ;
     RECT  43.884 58.205 46.818 58.217 ;
     RECT  6.192 58.205 15.066 58.253 ;
     RECT  15.912 58.205 21.366 58.253 ;
     RECT  23.868 58.205 27.918 58.253 ;
     RECT  30.744 58.217 30.762 58.253 ;
     RECT  39.816 58.205 41.31 58.253 ;
     RECT  42.084 58.205 42.93 58.253 ;
     RECT  44.352 58.217 46.818 58.253 ;
     RECT  50.472 58.205 52.614 58.253 ;
     RECT  53.496 58.205 55.242 58.253 ;
     RECT  15.912 58.253 20.826 58.301 ;
     RECT  22.176 58.205 22.734 58.301 ;
     RECT  26.208 58.253 27.27 58.301 ;
     RECT  44.352 58.253 45.774 58.301 ;
     RECT  47.808 58.205 49.302 58.301 ;
     RECT  53.496 58.253 53.586 58.301 ;
     RECT  54.648 58.253 55.242 58.301 ;
     RECT  2.415 58.067 2.505 58.337 ;
     RECT  24.015 58.253 25.398 58.337 ;
     RECT  45.615 58.301 45.774 58.337 ;
     RECT  56.415 58.145 56.505 58.337 ;
     RECT  24.156 58.337 25.398 58.349 ;
     RECT  54.648 58.301 54.666 58.397 ;
     RECT  24.156 58.349 24.462 58.445 ;
     RECT  6.192 58.253 7.974 58.493 ;
     RECT  12.492 58.253 13.374 58.493 ;
     RECT  24.156 58.445 24.174 58.493 ;
     RECT  45.756 58.337 45.774 58.493 ;
     RECT  36.216 58.205 39.078 58.589 ;
     RECT  14.184 58.253 15.066 58.637 ;
     RECT  39.816 58.253 40.986 58.637 ;
     RECT  6.192 58.493 7.722 58.685 ;
     RECT  8.892 58.253 11.61 58.685 ;
     RECT  12.492 58.493 12.978 58.685 ;
     RECT  14.184 58.637 14.958 58.685 ;
     RECT  17.244 58.301 20.826 58.685 ;
     RECT  29.088 58.205 29.574 58.685 ;
     RECT  32.472 58.205 35.478 58.685 ;
     RECT  36.216 58.589 39.042 58.685 ;
     RECT  39.816 58.637 40.914 58.685 ;
     RECT  42.912 58.253 42.93 58.685 ;
     RECT  46.8 58.253 46.818 58.685 ;
     RECT  48.888 58.301 49.302 58.685 ;
     RECT  50.472 58.253 52.542 58.685 ;
     RECT  50.472 58.685 50.526 58.702 ;
     RECT  6.336 58.685 6.642 58.733 ;
     RECT  12.492 58.685 12.51 58.733 ;
     RECT  7.704 58.685 7.722 59.309 ;
     RECT  8.892 58.685 8.91 59.309 ;
     RECT  14.184 58.685 14.202 59.309 ;
     RECT  15.912 58.301 16.218 59.309 ;
     RECT  26.208 58.301 26.73 59.309 ;
     RECT  29.556 58.685 29.574 59.309 ;
     RECT  36.9 58.685 36.99 59.309 ;
     RECT  48.996 58.685 49.014 59.309 ;
     RECT  50.508 58.702 50.526 59.309 ;
     RECT  51.768 58.685 51.786 59.309 ;
     RECT  53.496 58.301 53.514 59.309 ;
     RECT  26.64 59.309 26.73 59.837 ;
     RECT  6.624 58.733 6.642 59.885 ;
     RECT  16.2 59.309 16.218 59.885 ;
     RECT  26.712 59.837 26.73 59.885 ;
     RECT  32.472 58.685 33.174 59.885 ;
     RECT  36.972 59.309 36.99 59.885 ;
     RECT  13.572 60.187 13.59 60.365 ;
     RECT  33.156 59.885 33.174 60.365 ;
    LAYER M4 ;
     RECT  0.06 12.528 0.137 17.016 ;
     RECT  0.06 21.456 0.173 21.624 ;
     RECT  0.137 12.672 2.408 17.016 ;
     RECT  0.173 21.456 2.408 21.528 ;
     RECT  2.408 2.148 2.512 58.332 ;
     RECT  2.512 2.418 2.704 58.062 ;
     RECT  2.704 12.816 2.729 17.112 ;
     RECT  2.704 21.456 2.729 21.528 ;
     RECT  2.729 13.008 3.805 17.112 ;
     RECT  3.805 13.008 3.841 17.352 ;
     RECT  2.704 11.664 3.877 11.688 ;
     RECT  3.841 12.768 3.877 17.352 ;
     RECT  3.877 11.664 4.165 17.352 ;
     RECT  2.704 19.248 4.309 19.272 ;
     RECT  4.165 11.664 4.489 17.448 ;
     RECT  4.489 10.992 4.637 17.448 ;
     RECT  4.705 18.24 4.789 18.264 ;
     RECT  4.309 19.248 5.123 19.992 ;
     RECT  4.637 10.992 5.137 17.112 ;
     RECT  5.137 10.8 5.465 17.112 ;
     RECT  5.123 19.968 5.641 19.992 ;
     RECT  2.729 21.504 5.641 21.528 ;
     RECT  5.465 12.624 5.677 17.112 ;
     RECT  5.677 12.624 5.717 17.64 ;
     RECT  5.641 19.968 5.749 20.184 ;
     RECT  5.641 21.504 5.857 21.672 ;
     RECT  5.717 12.624 5.933 16.536 ;
     RECT  5.749 19.968 6.037 20.376 ;
     RECT  5.996 58.128 6.181 58.152 ;
     RECT  6.037 19.968 6.253 20.424 ;
     RECT  5.465 10.8 6.257 11.16 ;
     RECT  6.181 58.128 6.264 58.68 ;
     RECT  6.253 19.248 6.329 20.424 ;
     RECT  6.329 19.248 6.371 19.272 ;
     RECT  6.264 58.128 6.371 58.728 ;
     RECT  5.717 17.616 6.397 17.64 ;
     RECT  5.933 13.584 6.401 16.536 ;
     RECT  6.401 13.584 6.515 13.848 ;
     RECT  6.401 14.832 6.515 16.536 ;
     RECT  6.397 17.616 6.545 17.976 ;
     RECT  6.257 11.136 6.721 11.16 ;
     RECT  6.515 15.12 6.865 16.536 ;
     RECT  6.545 17.616 6.865 17.688 ;
     RECT  6.613 59.856 6.947 59.88 ;
     RECT  6.937 55.92 7.045 55.944 ;
     RECT  6.757 57.024 7.045 57.048 ;
     RECT  6.577 54.864 7.153 54.888 ;
     RECT  6.721 11.136 7.225 12.024 ;
     RECT  7.045 55.92 7.297 57.048 ;
     RECT  6.371 58.128 7.297 58.248 ;
     RECT  7.297 55.92 7.333 58.248 ;
     RECT  7.333 55.92 7.693 58.68 ;
     RECT  7.225 11.136 7.808 12.504 ;
     RECT  6.515 13.584 7.808 13.752 ;
     RECT  6.865 15.12 7.808 17.688 ;
     RECT  6.329 20.256 7.808 20.424 ;
     RECT  5.857 21.504 7.808 21.816 ;
     RECT  7.153 54.672 7.808 54.888 ;
     RECT  7.693 55.92 7.808 59.304 ;
     RECT  7.808 2.148 7.912 59.304 ;
     RECT  7.912 2.418 7.996 59.304 ;
     RECT  7.996 2.418 8.104 58.248 ;
     RECT  8.104 12 8.291 13.128 ;
     RECT  8.291 12 8.345 12.36 ;
     RECT  8.104 15.168 8.345 16.824 ;
     RECT  8.345 12.24 8.381 12.36 ;
     RECT  8.345 15.168 8.453 16.104 ;
     RECT  8.104 21.504 8.453 21.528 ;
     RECT  8.381 12.336 8.489 12.36 ;
     RECT  8.104 58.128 9.061 58.248 ;
     RECT  8.104 14.16 9.065 14.184 ;
     RECT  8.453 15.168 9.065 15.768 ;
     RECT  8.104 54.864 9.133 55.848 ;
     RECT  7.996 59.28 9.251 59.304 ;
     RECT  9.065 15.168 9.281 15.384 ;
     RECT  9.061 58.128 9.313 58.296 ;
     RECT  9.356 50.448 9.443 50.472 ;
     RECT  9.133 54.864 9.745 56.568 ;
     RECT  9.313 58.128 9.745 58.68 ;
     RECT  9.133 3.408 9.889 3.432 ;
     RECT  9.932 5.184 9.973 5.208 ;
     RECT  9.973 4.512 10.019 5.208 ;
     RECT  10.069 0.096 10.153 0.12 ;
     RECT  9.889 3.024 10.177 3.432 ;
     RECT  10.019 4.512 10.177 4.536 ;
     RECT  9.925 1.728 10.249 1.752 ;
     RECT  10.249 1.104 10.403 1.752 ;
     RECT  10.177 3.024 10.505 4.536 ;
     RECT  10.177 44.448 10.537 44.472 ;
     RECT  10.537 44.448 10.577 45 ;
     RECT  9.745 54.864 10.645 58.68 ;
     RECT  10.403 1.728 10.748 1.752 ;
     RECT  10.501 48.336 10.825 48.36 ;
     RECT  10.645 54.768 10.825 58.68 ;
     RECT  10.825 47.472 10.883 48.36 ;
     RECT  10.505 3.024 10.892 4.344 ;
     RECT  9.673 53.568 10.969 53.592 ;
     RECT  10.825 54.672 10.969 58.68 ;
     RECT  10.577 44.976 11.005 45 ;
     RECT  10.465 46.224 11.005 46.248 ;
     RECT  10.969 53.568 11.009 58.68 ;
     RECT  11.005 44.976 11.213 46.248 ;
     RECT  10.883 47.472 11.213 47.496 ;
     RECT  11.213 44.976 11.297 47.496 ;
     RECT  10.748 1.728 11.468 1.848 ;
     RECT  10.892 2.832 11.468 4.344 ;
     RECT  11.329 0.24 11.509 0.264 ;
     RECT  11.468 1.728 11.509 4.344 ;
     RECT  11.297 44.976 11.513 46.248 ;
     RECT  11.509 1.728 11.621 4.776 ;
     RECT  11.509 0.096 11.699 0.264 ;
     RECT  11.621 4.176 11.699 4.776 ;
     RECT  9.281 15.168 11.699 15.192 ;
     RECT  11.699 0.096 11.801 0.12 ;
     RECT  11.009 54.432 11.837 58.68 ;
     RECT  11.513 44.976 11.869 45.72 ;
     RECT  10.501 42.768 11.941 42.792 ;
     RECT  11.869 44.208 11.941 45.72 ;
     RECT  11.297 47.472 11.945 47.496 ;
     RECT  11.545 51.696 11.945 51.72 ;
     RECT  11.941 42.768 11.987 45.72 ;
     RECT  11.621 1.728 12.373 2.904 ;
     RECT  11.837 57.12 12.476 58.68 ;
     RECT  11.689 53.232 12.553 53.256 ;
     RECT  11.837 54.432 12.553 55.992 ;
     RECT  12.373 1.104 12.563 2.904 ;
     RECT  12.476 57.12 12.563 58.728 ;
     RECT  12.553 53.232 12.625 55.992 ;
     RECT  11.699 4.176 12.661 4.68 ;
     RECT  12.625 52.944 12.913 55.992 ;
     RECT  12.563 57.12 12.913 58.68 ;
     RECT  12.661 3.984 12.949 4.68 ;
     RECT  12.733 51.408 12.949 51.432 ;
     RECT  12.913 52.944 13.033 58.68 ;
     RECT  12.949 3.984 13.085 5.16 ;
     RECT  13.045 6.288 13.085 6.312 ;
     RECT  12.563 1.728 13.208 2.904 ;
     RECT  13.085 3.984 13.208 6.312 ;
     RECT  11.149 7.968 13.208 7.992 ;
     RECT  11.987 43.296 13.208 44.616 ;
     RECT  11.987 45.696 13.208 45.72 ;
     RECT  12.949 51.408 13.208 51.96 ;
     RECT  13.033 52.944 13.208 58.488 ;
     RECT  12.797 0.576 13.237 0.6 ;
     RECT  13.208 1.728 13.385 58.488 ;
     RECT  13.385 1.728 13.504 58.248 ;
     RECT  13.381 60.288 13.517 60.312 ;
     RECT  13.517 60.288 13.532 60.36 ;
     RECT  13.504 50.736 13.565 51.96 ;
     RECT  13.532 60.192 13.601 60.36 ;
     RECT  13.237 0.144 13.619 0.6 ;
     RECT  13.504 7.968 13.619 7.992 ;
     RECT  13.601 60.192 13.619 60.312 ;
     RECT  13.504 54.96 13.645 58.248 ;
     RECT  13.619 60.288 13.667 60.312 ;
     RECT  13.504 3.408 13.673 5.208 ;
     RECT  13.565 50.736 13.673 51.432 ;
     RECT  13.645 54.96 13.709 56.28 ;
     RECT  13.673 51.36 13.853 51.432 ;
     RECT  13.504 1.728 13.861 2.328 ;
     RECT  13.619 0.576 13.925 0.6 ;
     RECT  13.504 24.336 14.033 24.504 ;
     RECT  14.173 59.28 14.291 59.304 ;
     RECT  14.033 24.336 14.492 24.36 ;
     RECT  13.645 57.84 14.533 58.248 ;
     RECT  14.533 52.272 14.581 52.296 ;
     RECT  14.581 52.272 14.627 53.208 ;
     RECT  13.709 54.96 14.749 56.088 ;
     RECT  14.492 23.904 14.785 24.36 ;
     RECT  14.627 53.184 14.929 53.208 ;
     RECT  13.861 1.728 15.049 1.8 ;
     RECT  13.673 3.408 15.145 4.68 ;
     RECT  14.533 5.712 15.145 5.736 ;
     RECT  15.049 1.728 15.212 1.752 ;
     RECT  14.929 53.184 15.289 53.352 ;
     RECT  15.212 1.104 15.299 1.752 ;
     RECT  14.533 57.84 15.299 58.68 ;
     RECT  14.749 54.96 15.401 56.472 ;
     RECT  15.145 3.408 15.829 5.736 ;
     RECT  15.299 57.84 15.973 58.2 ;
     RECT  15.829 2.88 15.977 5.736 ;
     RECT  15.325 0.096 16.021 0.12 ;
     RECT  15.977 3.408 16.085 5.736 ;
     RECT  15.289 53.184 16.085 53.544 ;
     RECT  15.401 54.96 16.085 55.944 ;
     RECT  15.299 1.728 16.117 1.752 ;
     RECT  15.901 59.28 16.163 59.304 ;
     RECT  15.973 57.024 16.364 58.2 ;
     RECT  16.364 57.024 16.513 58.296 ;
     RECT  16.189 59.856 16.595 59.88 ;
     RECT  16.085 4.176 16.837 5.736 ;
     RECT  16.837 4.176 16.981 5.784 ;
     RECT  16.513 56.448 17.057 58.296 ;
     RECT  17.057 57.6 17.125 58.296 ;
     RECT  17.057 56.448 17.129 56.472 ;
     RECT  16.117 1.728 17.201 2.232 ;
     RECT  16.981 4.176 17.377 5.832 ;
     RECT  17.125 0.096 17.557 0.12 ;
     RECT  17.125 57.6 17.561 58.68 ;
     RECT  15.577 7.344 17.629 7.368 ;
     RECT  16.085 54.96 17.693 54.984 ;
     RECT  17.557 0.096 17.701 0.168 ;
     RECT  17.693 54.72 17.797 54.984 ;
     RECT  17.701 0.096 17.813 0.216 ;
     RECT  17.377 3.264 17.845 5.832 ;
     RECT  17.813 0.144 18.125 0.216 ;
     RECT  17.629 7.2 18.205 7.368 ;
     RECT  17.797 54.72 18.205 55.272 ;
     RECT  18.125 0.144 18.209 0.6 ;
     RECT  18.205 7.2 18.241 7.416 ;
     RECT  17.845 3.264 18.277 6.12 ;
     RECT  17.201 1.728 18.565 1.8 ;
     RECT  18.565 1.728 18.608 2.04 ;
     RECT  18.277 3.12 18.608 6.12 ;
     RECT  18.241 7.104 18.608 7.416 ;
     RECT  14.785 23.808 18.608 24.36 ;
     RECT  15.685 30.336 18.608 30.36 ;
     RECT  16.085 53.184 18.608 53.208 ;
     RECT  18.205 54.72 18.608 55.752 ;
     RECT  17.561 57.84 18.608 58.68 ;
     RECT  18.608 1.728 18.904 58.68 ;
     RECT  18.904 55.728 18.965 55.752 ;
     RECT  18.904 1.728 19.475 3.048 ;
     RECT  18.209 0.144 19.532 0.168 ;
     RECT  19.475 1.728 19.532 1.8 ;
     RECT  19.532 0.144 19.619 1.8 ;
     RECT  18.904 4.176 19.901 7.416 ;
     RECT  19.475 3.024 19.933 3.048 ;
     RECT  19.901 4.176 19.933 7.176 ;
     RECT  19.619 0.144 20.003 0.552 ;
     RECT  19.933 3.024 20.045 7.176 ;
     RECT  20.003 0.528 20.339 0.552 ;
     RECT  19.619 1.728 20.513 1.8 ;
     RECT  20.045 3.84 20.513 7.176 ;
     RECT  18.904 57.84 20.837 58.68 ;
     RECT  20.401 56.4 20.873 56.424 ;
     RECT  20.533 36.288 21.089 36.312 ;
     RECT  21.157 0.096 21.305 0.12 ;
     RECT  21.013 12.48 21.337 12.504 ;
     RECT  20.513 3.84 21.341 6.648 ;
     RECT  20.513 1.728 21.373 1.752 ;
     RECT  21.337 12 21.421 12.504 ;
     RECT  21.437 2.88 21.521 2.904 ;
     RECT  20.837 57.84 22.124 58.248 ;
     RECT  21.373 1.104 22.211 1.752 ;
     RECT  22.309 0.096 22.445 0.12 ;
     RECT  22.211 1.728 22.556 1.752 ;
     RECT  21.341 4.176 22.777 6.648 ;
     RECT  22.124 57.84 22.787 58.296 ;
     RECT  22.561 55.824 22.889 55.848 ;
     RECT  22.556 1.728 22.961 2.28 ;
     RECT  22.961 2.256 23.173 2.28 ;
     RECT  22.777 3.84 23.173 6.648 ;
     RECT  22.445 0.096 23.681 0.168 ;
     RECT  22.787 57.84 23.785 58.2 ;
     RECT  23.785 57.024 23.852 58.2 ;
     RECT  23.173 2.256 23.857 2.616 ;
     RECT  23.173 3.84 23.857 6.792 ;
     RECT  23.857 2.256 24.008 6.792 ;
     RECT  23.065 8.16 24.008 8.184 ;
     RECT  21.421 12.48 24.008 12.504 ;
     RECT  18.904 23.808 24.008 24.36 ;
     RECT  18.904 30.336 24.008 30.36 ;
     RECT  23.893 53.04 24.008 53.064 ;
     RECT  23.852 57.024 24.008 58.248 ;
     RECT  24.008 2.148 24.037 58.332 ;
     RECT  24.037 1.728 24.185 58.488 ;
     RECT  24.185 1.728 24.304 58.44 ;
     RECT  24.181 60.288 24.419 60.312 ;
     RECT  23.681 0.144 24.467 0.168 ;
     RECT  24.304 57.168 24.473 58.44 ;
     RECT  24.304 55.248 24.515 55.896 ;
     RECT  24.304 1.728 24.581 3.432 ;
     RECT  24.581 1.728 24.757 2.76 ;
     RECT  24.515 55.872 24.869 55.896 ;
     RECT  24.304 50.736 24.905 50.76 ;
     RECT  24.473 57.168 25.667 58.344 ;
     RECT  24.304 5.136 25.693 7.224 ;
     RECT  24.757 1.152 25.729 2.76 ;
     RECT  25.729 1.152 26.017 2.808 ;
     RECT  24.304 8.448 26.021 8.472 ;
     RECT  25.693 5.088 26.057 7.224 ;
     RECT  25.667 57.168 26.099 58.248 ;
     RECT  26.017 1.152 26.165 2.856 ;
     RECT  25.765 0.096 26.197 0.12 ;
     RECT  25.873 47.856 26.197 47.88 ;
     RECT  25.657 55.392 26.201 55.416 ;
     RECT  26.197 47.856 26.243 48.696 ;
     RECT  26.156 59.28 26.243 59.304 ;
     RECT  26.165 1.68 26.309 2.856 ;
     RECT  26.057 5.616 26.309 7.224 ;
     RECT  26.197 0.096 26.417 0.6 ;
     RECT  26.099 57.168 26.557 58.2 ;
     RECT  26.341 59.808 26.668 59.832 ;
     RECT  26.668 59.808 26.669 59.88 ;
     RECT  26.669 59.856 26.819 59.88 ;
     RECT  26.309 1.68 26.963 2.52 ;
     RECT  26.557 56.352 26.993 58.2 ;
     RECT  26.993 57.168 27.029 58.2 ;
     RECT  27.029 57.552 27.205 58.2 ;
     RECT  27.205 57.552 27.292 58.296 ;
     RECT  26.963 1.728 27.313 2.52 ;
     RECT  26.309 5.616 27.313 6.648 ;
     RECT  26.417 0.096 27.629 0.12 ;
     RECT  26.485 55.296 27.637 55.32 ;
     RECT  27.637 55.296 27.677 55.848 ;
     RECT  27.629 0.096 27.713 0.6 ;
     RECT  27.565 53.616 27.857 53.64 ;
     RECT  27.292 57.552 27.929 58.248 ;
     RECT  27.313 5.424 28.001 7.512 ;
     RECT  27.713 0.096 28.109 0.12 ;
     RECT  28.001 5.472 28.253 7.512 ;
     RECT  28.033 46.8 28.316 46.824 ;
     RECT  27.929 57.552 28.357 58.2 ;
     RECT  27.677 55.488 28.393 55.848 ;
     RECT  28.357 56.928 28.393 58.2 ;
     RECT  28.316 46.8 28.403 47.064 ;
     RECT  28.393 55.488 29.077 58.2 ;
     RECT  27.313 1.728 29.408 3.048 ;
     RECT  28.253 5.472 29.408 5.496 ;
     RECT  28.253 6.576 29.408 7.512 ;
     RECT  24.304 12.48 29.408 12.504 ;
     RECT  24.304 23.808 29.408 24.36 ;
     RECT  24.304 30.336 29.408 30.36 ;
     RECT  28.403 46.8 29.408 46.824 ;
     RECT  26.243 48.672 29.408 48.696 ;
     RECT  29.077 55.488 29.408 58.68 ;
     RECT  29.408 1.728 29.512 58.68 ;
     RECT  29.173 60.288 29.555 60.312 ;
     RECT  29.545 59.28 29.699 59.304 ;
     RECT  29.512 1.728 29.704 58.248 ;
     RECT  29.704 1.728 29.765 2.04 ;
     RECT  29.704 3.024 29.837 6.84 ;
     RECT  29.704 30.288 29.909 30.36 ;
     RECT  29.765 1.728 29.941 1.848 ;
     RECT  29.704 57.024 29.945 57.048 ;
     RECT  29.909 30.288 30.275 30.312 ;
     RECT  29.789 0.096 30.34 0.12 ;
     RECT  29.941 1.152 30.377 1.848 ;
     RECT  29.704 46.8 30.515 46.824 ;
     RECT  30.34 0.096 30.593 0.168 ;
     RECT  29.837 3.696 30.701 6.84 ;
     RECT  30.377 1.68 30.764 1.848 ;
     RECT  29.704 53.808 30.773 53.832 ;
     RECT  29.704 58.128 30.806 58.248 ;
     RECT  30.806 58.128 30.809 58.2 ;
     RECT  29.704 55.488 30.989 55.704 ;
     RECT  30.764 1.68 30.995 2.28 ;
     RECT  30.701 4.272 31.093 6.84 ;
     RECT  30.809 58.176 31.097 58.2 ;
     RECT  30.593 0.096 31.241 0.12 ;
     RECT  31.093 4.272 31.313 7.752 ;
     RECT  30.995 1.728 31.34 2.28 ;
     RECT  31.313 4.272 31.601 5.736 ;
     RECT  31.313 6.768 31.885 7.752 ;
     RECT  31.34 1.728 31.889 2.856 ;
     RECT  31.889 1.728 31.957 1.8 ;
     RECT  31.957 1.152 32.141 1.8 ;
     RECT  32.101 58.128 32.356 58.152 ;
     RECT  30.989 55.488 32.497 55.512 ;
     RECT  32.389 0.144 32.525 0.168 ;
     RECT  32.356 58.128 32.533 58.2 ;
     RECT  30.913 57.024 32.537 57.048 ;
     RECT  31.885 6.768 32.569 7.896 ;
     RECT  32.461 59.856 32.723 59.88 ;
     RECT  32.525 0.144 32.897 0.6 ;
     RECT  31.601 4.464 33.113 5.736 ;
     RECT  32.533 58.128 33.113 58.68 ;
     RECT  32.497 55.488 33.185 55.752 ;
     RECT  33.101 60.336 33.185 60.36 ;
     RECT  32.569 6.768 33.217 8.568 ;
     RECT  33.217 6.288 33.301 8.568 ;
     RECT  33.113 4.464 33.397 5.304 ;
     RECT  33.397 3.984 33.653 5.304 ;
     RECT  33.301 6.288 33.761 7.896 ;
     RECT  31.889 2.832 33.865 2.856 ;
     RECT  32.141 1.728 33.925 1.8 ;
     RECT  33.865 2.832 33.925 2.952 ;
     RECT  33.925 1.728 34.048 2.952 ;
     RECT  33.113 58.512 34.076 58.68 ;
     RECT  29.704 23.808 34.213 24.36 ;
     RECT  33.185 55.488 34.477 55.512 ;
     RECT  33.653 5.28 34.693 5.304 ;
     RECT  33.761 6.816 34.765 7.896 ;
     RECT  34.048 1.68 34.808 2.952 ;
     RECT  33.653 3.984 34.808 4.008 ;
     RECT  34.693 5.184 34.808 5.304 ;
     RECT  34.765 6.816 34.808 8.28 ;
     RECT  29.704 12.48 34.808 12.504 ;
     RECT  34.213 23.568 34.808 24.36 ;
     RECT  29.704 43.056 34.808 43.08 ;
     RECT  29.704 48.672 34.808 48.696 ;
     RECT  34.477 55.488 34.808 55.848 ;
     RECT  34.076 58.128 34.808 58.68 ;
     RECT  34.808 1.68 34.837 58.68 ;
     RECT  34.837 1.152 35.104 58.68 ;
     RECT  35.104 1.152 35.245 3.096 ;
     RECT  35.245 1.152 35.26 2.952 ;
     RECT  35.26 1.152 35.309 2.856 ;
     RECT  35.104 55.488 35.425 55.848 ;
     RECT  34.405 60.288 35.603 60.312 ;
     RECT  35.104 4.56 35.633 8.52 ;
     RECT  35.633 4.992 35.741 8.52 ;
     RECT  33.253 0.096 35.989 0.12 ;
     RECT  35.741 5.424 36.389 8.52 ;
     RECT  35.989 0.096 36.461 0.648 ;
     RECT  35.425 55.488 36.713 55.512 ;
     RECT  35.104 58.128 36.889 58.68 ;
     RECT  35.309 1.728 36.929 2.856 ;
     RECT  36.889 58.128 36.961 59.304 ;
     RECT  36.781 57.12 37.037 57.144 ;
     RECT  36.929 1.728 37.141 1.752 ;
     RECT  36.961 2.88 37.145 2.904 ;
     RECT  36.961 58.128 37.187 59.88 ;
     RECT  37.141 1.152 37.253 1.752 ;
     RECT  37.187 59.856 37.331 59.88 ;
     RECT  36.389 5.424 37.573 5.496 ;
     RECT  36.461 0.096 37.717 0.12 ;
     RECT  37.717 0.096 37.721 0.168 ;
     RECT  37.573 5.136 37.757 5.496 ;
     RECT  37.757 5.472 37.825 5.496 ;
     RECT  36.389 6.768 37.825 8.52 ;
     RECT  37.253 1.728 38.005 1.752 ;
     RECT  35.104 12.48 38.117 12.504 ;
     RECT  37.721 0.144 38.153 0.168 ;
     RECT  38.293 0.576 38.405 0.6 ;
     RECT  37.825 5.472 38.477 8.52 ;
     RECT  38.396 12.336 38.483 12.36 ;
     RECT  38.401 54.72 38.653 54.744 ;
     RECT  38.653 54.72 38.765 55.032 ;
     RECT  38.005 1.728 38.869 2.28 ;
     RECT  37.897 3.888 38.972 3.912 ;
     RECT  38.972 3.312 39.017 3.912 ;
     RECT  38.765 55.008 39.089 55.032 ;
     RECT  38.869 1.152 39.197 2.28 ;
     RECT  38.477 5.472 39.197 8.328 ;
     RECT  39.197 1.728 39.229 2.28 ;
     RECT  39.017 3.312 39.229 3.432 ;
     RECT  39.157 0.096 39.589 0.168 ;
     RECT  39.197 5.472 40.129 7.896 ;
     RECT  39.229 1.728 40.208 3.432 ;
     RECT  40.129 5.184 40.208 7.896 ;
     RECT  35.104 23.568 40.208 24.36 ;
     RECT  35.104 43.056 40.208 43.08 ;
     RECT  35.104 48.672 40.208 48.696 ;
     RECT  37.187 58.128 40.208 58.68 ;
     RECT  40.208 1.728 40.504 58.68 ;
     RECT  40.504 57.84 40.925 58.68 ;
     RECT  40.925 57.84 40.997 58.632 ;
     RECT  39.589 0.096 41.219 0.552 ;
     RECT  41.219 0.096 41.249 0.216 ;
     RECT  41.249 0.096 41.285 0.168 ;
     RECT  40.504 4.848 41.497 5.784 ;
     RECT  40.504 6.816 41.497 7.896 ;
     RECT  41.497 4.848 41.641 7.896 ;
     RECT  41.641 4.848 41.653 8.472 ;
     RECT  41.653 4.848 41.753 8.856 ;
     RECT  41.753 5.472 41.929 8.856 ;
     RECT  40.504 1.728 41.965 3.432 ;
     RECT  41.965 1.728 42.109 3.528 ;
     RECT  42.109 1.728 42.131 4.392 ;
     RECT  42.131 1.728 42.275 2.616 ;
     RECT  41.285 0.144 42.325 0.168 ;
     RECT  42.325 0.144 42.613 0.6 ;
     RECT  42.613 0.096 42.653 0.6 ;
     RECT  42.131 4.368 42.689 4.392 ;
     RECT  41.929 5.472 42.757 9.528 ;
     RECT  40.997 57.84 42.901 58.248 ;
     RECT  42.901 57.84 42.985 58.68 ;
     RECT  42.757 4.752 43.085 9.528 ;
     RECT  43.297 3.408 43.441 3.432 ;
     RECT  40.504 55.68 43.621 55.704 ;
     RECT  43.621 55.68 43.697 56.424 ;
     RECT  42.275 1.728 43.909 1.8 ;
     RECT  43.441 2.784 43.909 3.432 ;
     RECT  43.085 5.136 44.053 9.528 ;
     RECT  44.053 4.56 44.108 9.528 ;
     RECT  40.504 43.056 44.165 43.08 ;
     RECT  44.108 4.512 44.195 9.528 ;
     RECT  42.653 0.096 44.201 0.552 ;
     RECT  42.985 57.84 44.3 58.2 ;
     RECT  44.195 4.56 44.309 5.592 ;
     RECT  44.201 0.144 44.627 0.552 ;
     RECT  43.909 1.728 44.701 3.432 ;
     RECT  44.3 57.84 44.732 58.296 ;
     RECT  43.697 56.4 44.773 56.424 ;
     RECT  44.701 1.104 44.963 3.432 ;
     RECT  44.309 5.472 45.308 5.592 ;
     RECT  44.195 6.72 45.565 9.528 ;
     RECT  44.963 1.728 45.608 3.432 ;
     RECT  45.308 4.8 45.608 5.592 ;
     RECT  45.565 6.576 45.608 9.528 ;
     RECT  40.504 23.568 45.608 24.36 ;
     RECT  40.504 48.672 45.608 48.696 ;
     RECT  44.773 55.488 45.608 56.424 ;
     RECT  44.732 57.792 45.608 58.296 ;
     RECT  45.608 1.728 45.637 58.332 ;
     RECT  45.637 1.728 45.785 58.488 ;
     RECT  45.785 1.728 45.904 58.248 ;
     RECT  45.781 0.096 45.925 0.12 ;
     RECT  45.781 60.288 45.925 60.312 ;
     RECT  45.904 55.392 46.001 56.472 ;
     RECT  45.925 60.24 46.067 60.312 ;
     RECT  46.067 60.24 46.163 60.264 ;
     RECT  45.925 0.096 46.357 0.6 ;
     RECT  45.904 1.728 46.357 3.432 ;
     RECT  46.357 0.096 46.361 3.432 ;
     RECT  46.361 0.096 46.577 3.048 ;
     RECT  46.577 1.728 46.613 3.048 ;
     RECT  46.613 2.832 46.685 3.048 ;
     RECT  45.904 58.128 46.789 58.248 ;
     RECT  46.577 0.096 46.835 0.552 ;
     RECT  46.789 58.128 46.873 58.68 ;
     RECT  46.001 55.392 47.293 55.416 ;
     RECT  46.001 56.448 47.293 56.472 ;
     RECT  45.904 5.136 47.585 9.528 ;
     RECT  46.613 1.728 47.797 1.752 ;
     RECT  47.797 1.728 47.941 1.8 ;
     RECT  46.685 2.832 47.941 2.856 ;
     RECT  47.941 1.152 48.053 1.8 ;
     RECT  48.053 1.728 48.085 1.8 ;
     RECT  47.941 2.832 48.085 2.904 ;
     RECT  48.085 1.728 48.125 2.904 ;
     RECT  47.585 5.136 48.265 5.208 ;
     RECT  48.125 1.728 48.269 2.328 ;
     RECT  48.229 54.336 48.301 54.36 ;
     RECT  48.265 4.368 48.365 5.208 ;
     RECT  47.293 55.392 48.377 56.472 ;
     RECT  48.365 3.408 48.449 5.208 ;
     RECT  46.835 0.096 48.517 0.12 ;
     RECT  46.873 58.128 48.805 58.296 ;
     RECT  48.449 3.984 48.841 5.208 ;
     RECT  48.517 0.096 48.845 0.6 ;
     RECT  48.841 3.984 48.925 5.544 ;
     RECT  48.805 58.128 48.985 58.68 ;
     RECT  48.377 55.68 49.061 56.472 ;
     RECT  48.845 0.096 49.133 0.552 ;
     RECT  48.985 58.128 49.139 59.304 ;
     RECT  48.925 3.984 49.421 5.208 ;
     RECT  48.269 1.728 49.597 1.8 ;
     RECT  49.597 1.728 49.715 2.28 ;
     RECT  49.133 0.528 49.813 0.552 ;
     RECT  48.301 54.336 49.957 54.408 ;
     RECT  49.813 0.528 49.961 0.6 ;
     RECT  49.885 26.208 50.065 26.232 ;
     RECT  49.421 4.272 50.209 5.208 ;
     RECT  50.237 0.096 50.321 0.12 ;
     RECT  49.715 1.728 50.389 1.8 ;
     RECT  49.139 58.128 50.497 58.68 ;
     RECT  50.389 1.152 50.677 1.8 ;
     RECT  49.957 54.336 50.713 54.696 ;
     RECT  49.061 55.68 50.713 55.704 ;
     RECT  50.209 4.272 50.725 5.736 ;
     RECT  47.585 6.816 50.725 9.528 ;
     RECT  50.677 1.152 50.813 1.848 ;
     RECT  45.904 48.672 50.821 48.696 ;
     RECT  50.813 1.152 50.849 2.328 ;
     RECT  49.093 44.448 50.869 44.472 ;
     RECT  50.821 46.656 50.869 46.68 ;
     RECT  50.849 1.152 51.008 2.76 ;
     RECT  50.725 4.272 51.008 9.528 ;
     RECT  45.904 23.568 51.008 24.36 ;
     RECT  50.065 26.208 51.008 26.376 ;
     RECT  50.353 29.52 51.008 29.544 ;
     RECT  50.749 31.008 51.008 31.032 ;
     RECT  45.904 43.008 51.008 43.032 ;
     RECT  50.869 44.448 51.008 45 ;
     RECT  50.869 46.224 51.008 46.68 ;
     RECT  50.821 47.904 51.008 48.696 ;
     RECT  50.713 53.616 51.008 55.704 ;
     RECT  50.497 58.128 51.008 59.304 ;
     RECT  50.869 60.288 51.011 60.312 ;
     RECT  51.008 1.152 51.304 59.304 ;
     RECT  51.304 35.52 51.473 36.024 ;
     RECT  51.304 1.152 51.5 3.336 ;
     RECT  51.304 47.136 51.532 59.304 ;
     RECT  51.5 1.104 51.587 3.336 ;
     RECT  51.532 50.016 51.731 59.304 ;
     RECT  51.304 7.344 51.779 9.528 ;
     RECT  51.779 7.344 51.827 9.288 ;
     RECT  51.731 50.016 51.833 56.328 ;
     RECT  51.304 23.568 51.869 27.336 ;
     RECT  51.304 30.816 51.869 34.056 ;
     RECT  51.827 7.728 52.049 9.288 ;
     RECT  51.973 0.096 52.076 0.12 ;
     RECT  52.076 0.096 52.085 0.552 ;
     RECT  52.049 8.208 52.085 9.288 ;
     RECT  52.085 0.528 52.163 0.552 ;
     RECT  51.532 47.136 52.259 48.696 ;
     RECT  51.304 20.64 52.268 20.664 ;
     RECT  51.304 43.008 52.268 43.032 ;
     RECT  51.304 44.832 52.268 44.856 ;
     RECT  52.259 47.136 52.3 48.456 ;
     RECT  51.731 58.128 52.307 59.304 ;
     RECT  52.268 43.008 52.309 44.856 ;
     RECT  52.268 20.544 52.355 20.664 ;
     RECT  51.304 21.744 52.369 21.768 ;
     RECT  51.869 23.568 52.369 26.28 ;
     RECT  51.869 27.312 52.369 27.336 ;
     RECT  51.304 41.664 52.369 41.688 ;
     RECT  52.309 43.008 52.369 44.904 ;
     RECT  51.304 37.056 52.477 37.896 ;
     RECT  51.304 39.696 52.477 39.72 ;
     RECT  51.587 1.728 52.517 3.336 ;
     RECT  51.869 30.912 52.621 34.056 ;
     RECT  51.304 46.128 52.621 46.152 ;
     RECT  52.3 47.136 52.621 47.88 ;
     RECT  52.369 27.312 52.657 27.864 ;
     RECT  51.304 28.944 52.657 29.544 ;
     RECT  52.517 3.312 52.765 3.336 ;
     RECT  52.765 3.312 52.805 3.432 ;
     RECT  52.517 1.728 52.877 2.328 ;
     RECT  52.621 30.912 52.945 34.488 ;
     RECT  51.473 35.52 52.945 35.544 ;
     RECT  52.369 41.664 52.981 44.904 ;
     RECT  52.307 58.128 53.027 58.68 ;
     RECT  52.477 37.056 53.053 39.72 ;
     RECT  52.981 40.704 53.053 44.904 ;
     RECT  53.053 37.056 53.057 44.904 ;
     RECT  52.945 30.912 53.089 35.544 ;
     RECT  53.057 37.056 53.089 38.664 ;
     RECT  52.369 21.744 53.125 26.28 ;
     RECT  52.657 27.312 53.125 29.544 ;
     RECT  53.057 39.696 53.125 44.904 ;
     RECT  53.125 21.744 53.197 29.544 ;
     RECT  53.089 30.912 53.345 38.664 ;
     RECT  52.621 46.128 53.365 47.88 ;
     RECT  52.877 1.776 53.381 2.328 ;
     RECT  52.805 3.408 53.381 3.432 ;
     RECT  53.125 39.696 53.413 45.144 ;
     RECT  53.365 46.128 53.413 48.84 ;
     RECT  53.381 1.824 53.417 2.328 ;
     RECT  53.197 21.744 53.453 29.784 ;
     RECT  53.345 30.912 53.485 34.68 ;
     RECT  53.027 58.128 53.485 58.296 ;
     RECT  53.453 25.248 53.557 29.784 ;
     RECT  53.485 30.816 53.557 34.68 ;
     RECT  51.833 50.016 53.597 55.224 ;
     RECT  53.485 59.28 53.603 59.304 ;
     RECT  53.417 1.824 53.633 1.848 ;
     RECT  52.355 20.64 53.633 20.664 ;
     RECT  51.304 19.44 53.653 19.464 ;
     RECT  53.453 21.744 53.702 24.216 ;
     RECT  53.557 25.248 53.777 34.68 ;
     RECT  51.304 5.184 53.843 5.208 ;
     RECT  53.345 35.712 54.169 38.664 ;
     RECT  53.413 39.696 54.169 48.84 ;
     RECT  52.085 8.208 54.209 8.472 ;
     RECT  53.653 19.44 54.349 19.944 ;
     RECT  51.833 56.304 54.419 56.328 ;
     RECT  53.485 57.552 54.421 58.296 ;
     RECT  54.421 57.552 54.425 58.392 ;
     RECT  53.597 50.016 54.601 50.136 ;
     RECT  53.597 51.12 54.601 55.224 ;
     RECT  53.777 32.208 54.637 34.68 ;
     RECT  54.169 35.712 54.637 48.84 ;
     RECT  54.601 50.016 54.637 55.224 ;
     RECT  54.349 18.912 54.661 19.944 ;
     RECT  53.702 21.744 54.673 22.344 ;
     RECT  53.702 23.328 54.673 24.216 ;
     RECT  54.425 57.648 54.677 58.392 ;
     RECT  54.661 18.912 54.713 20.04 ;
     RECT  54.673 21.744 54.745 24.216 ;
     RECT  53.777 25.248 54.749 31.224 ;
     RECT  54.713 19.488 54.757 20.04 ;
     RECT  54.757 19.488 54.821 20.616 ;
     RECT  54.745 21.6 54.829 24.216 ;
     RECT  54.821 20.016 54.857 20.616 ;
     RECT  54.637 32.208 55.145 55.224 ;
     RECT  54.209 8.208 55.181 8.232 ;
     RECT  54.857 20.304 55.217 20.616 ;
     RECT  54.677 57.648 55.253 58.296 ;
     RECT  55.253 57.648 55.289 58.2 ;
     RECT  55.145 41.472 55.325 55.224 ;
     RECT  54.749 25.296 55.573 31.224 ;
     RECT  55.145 32.208 55.573 40.296 ;
     RECT  55.289 57.648 55.717 57.816 ;
     RECT  55.325 47.136 56.077 55.224 ;
     RECT  55.217 20.304 56.408 20.472 ;
     RECT  54.829 22.32 56.408 24.216 ;
     RECT  55.573 25.296 56.408 40.296 ;
     RECT  55.325 41.472 56.408 46.104 ;
     RECT  56.077 47.136 56.408 55.8 ;
     RECT  55.717 57.456 56.408 57.816 ;
     RECT  56.408 2.148 56.512 58.332 ;
     RECT  56.512 2.418 56.704 58.062 ;
     RECT  56.704 48.144 56.765 51.672 ;
     RECT  56.704 53.856 56.765 55.992 ;
     RECT  56.704 26.544 56.801 31.224 ;
     RECT  56.801 30.432 56.945 31.224 ;
     RECT  56.765 51.264 56.945 51.672 ;
     RECT  56.945 30.432 56.981 30.888 ;
     RECT  56.765 53.856 57.017 54.984 ;
     RECT  56.704 44.88 57.053 46.104 ;
     RECT  56.704 22.224 57.125 22.344 ;
     RECT  56.801 26.784 57.161 29.352 ;
     RECT  56.704 41.472 57.161 42.552 ;
     RECT  56.765 48.144 57.161 50.136 ;
     RECT  57.125 22.32 57.197 22.344 ;
     RECT  56.765 55.968 57.197 55.992 ;
     RECT  57.161 28.8 57.233 29.352 ;
     RECT  57.017 53.856 57.233 54.504 ;
     RECT  57.161 26.784 57.269 27.096 ;
     RECT  56.981 30.432 57.269 30.456 ;
     RECT  56.704 39.216 57.269 39.768 ;
     RECT  57.053 44.88 57.269 44.904 ;
     RECT  57.233 28.8 57.341 28.92 ;
     RECT  56.704 36.768 57.377 36.792 ;
     RECT  57.269 39.216 57.413 39.288 ;
     RECT  56.704 33.264 57.521 35.736 ;
     RECT  57.161 48.144 57.557 48.744 ;
     RECT  57.413 39.216 57.629 39.24 ;
     RECT  56.704 23.616 57.733 24.216 ;
     RECT  57.733 22.752 58.129 24.216 ;
     RECT  57.521 34.08 58.129 35.736 ;
     RECT  57.161 41.472 58.129 42.024 ;
     RECT  58.129 31.248 58.165 32.136 ;
     RECT  58.129 19.152 58.669 19.176 ;
     RECT  56.704 20.592 58.669 20.616 ;
     RECT  58.129 22.752 58.669 24.648 ;
     RECT  57.269 27.072 58.669 27.096 ;
     RECT  57.341 28.8 58.669 28.824 ;
     RECT  58.129 30.096 58.669 30.12 ;
     RECT  58.129 34.08 58.669 36.744 ;
     RECT  58.129 37.872 58.669 37.896 ;
     RECT  58.129 40.896 58.669 42.024 ;
     RECT  58.129 43.488 58.669 43.512 ;
     RECT  57.053 46.08 58.669 46.104 ;
     RECT  57.161 50.112 58.669 50.136 ;
     RECT  56.945 51.264 58.669 51.288 ;
     RECT  57.233 54.432 58.669 54.504 ;
     RECT  58.129 56.16 58.669 56.184 ;
     RECT  58.669 19.152 58.705 20.616 ;
     RECT  58.669 21.6 58.705 21.624 ;
     RECT  58.669 28.8 58.705 30.12 ;
     RECT  58.165 31.248 58.705 32.568 ;
     RECT  58.669 33.696 58.705 37.896 ;
     RECT  58.669 39.312 58.705 39.336 ;
     RECT  58.669 40.608 58.705 42.024 ;
     RECT  58.669 43.488 58.705 46.104 ;
     RECT  58.129 47.52 58.705 48.12 ;
     RECT  58.669 49.248 58.705 51.288 ;
     RECT  58.669 52.272 58.705 52.872 ;
     RECT  58.669 54 58.705 54.504 ;
     RECT  58.669 55.728 58.705 57.048 ;
     RECT  58.705 33.696 58.777 39.336 ;
     RECT  58.669 22.752 58.849 27.096 ;
     RECT  58.705 28.08 58.849 32.568 ;
     RECT  58.849 22.752 59.209 32.568 ;
     RECT  58.777 33.552 59.209 39.336 ;
     RECT  58.705 43.488 59.209 51.288 ;
     RECT  58.705 52.272 59.209 57.048 ;
     RECT  58.705 19.152 59.245 21.624 ;
     RECT  59.209 22.608 59.245 39.336 ;
     RECT  58.705 40.608 59.245 42.504 ;
     RECT  59.209 43.488 59.245 57.048 ;
     RECT  59.245 19.152 59.281 39.336 ;
     RECT  59.245 40.464 59.281 57.048 ;
     RECT  59.281 19.152 60.444 57.048 ;
    LAYER M5 ;
     RECT  9.936 0.016 28.248 1.763 ;
     RECT  29.52 0.016 52.44 1.763 ;
     RECT  10.8 1.763 28.248 1.811 ;
     RECT  41.616 1.763 52.44 1.811 ;
     RECT  10.8 1.811 17.016 1.859 ;
     RECT  29.52 1.763 35.592 1.859 ;
     RECT  50.688 1.811 52.44 1.859 ;
     RECT  29.52 1.859 29.712 2.137 ;
     RECT  2.4 2.137 2.52 2.151 ;
     RECT  7.8 2.137 7.92 2.151 ;
     RECT  56.4 2.137 56.52 2.151 ;
     RECT  26.64 1.811 27.096 2.195 ;
     RECT  28.224 1.811 28.248 2.195 ;
     RECT  50.832 1.859 52.296 2.195 ;
     RECT  10.944 1.859 17.016 2.291 ;
     RECT  18 1.811 25.656 2.291 ;
     RECT  30.816 1.859 35.592 2.291 ;
     RECT  37.584 1.763 38.76 2.291 ;
     RECT  43.488 1.811 49.704 2.291 ;
     RECT  36.576 1.763 36.6 2.339 ;
     RECT  43.488 2.291 49.128 2.339 ;
     RECT  50.832 2.195 51.312 2.339 ;
     RECT  41.616 1.811 42.264 2.771 ;
     RECT  10.944 2.291 11.544 2.867 ;
     RECT  31.392 2.291 31.416 2.867 ;
     RECT  18 2.291 22.056 2.915 ;
     RECT  32.592 2.291 35.592 2.915 ;
     RECT  39.744 1.763 40.512 2.963 ;
     RECT  43.488 2.339 47.4 3.011 ;
     RECT  38.592 2.291 38.616 3.301 ;
     RECT  48.384 2.339 49.128 3.443 ;
     RECT  12.672 2.291 17.016 3.971 ;
     RECT  12.672 3.971 15.144 4.019 ;
     RECT  49.104 3.443 49.128 4.019 ;
     RECT  50.88 2.339 51.312 4.261 ;
     RECT  34.704 2.915 35.592 4.595 ;
     RECT  23.184 2.291 25.656 4.643 ;
     RECT  11.52 2.867 11.544 4.645 ;
     RECT  11.52 4.645 11.688 4.787 ;
     RECT  43.488 3.011 44.52 4.789 ;
     RECT  45.6 3.011 47.4 4.789 ;
     RECT  18 2.915 20.904 4.885 ;
     RECT  22.032 2.915 22.056 4.885 ;
     RECT  12.96 4.019 15.144 5.171 ;
     RECT  23.328 4.643 25.656 5.171 ;
     RECT  37.584 2.291 37.608 5.171 ;
     RECT  43.488 4.789 47.4 5.171 ;
     RECT  9.984 4.501 10.008 5.219 ;
     RECT  13.056 5.171 15.144 5.219 ;
     RECT  34.704 4.595 35.304 5.219 ;
     RECT  38.592 3.301 39.048 5.461 ;
     RECT  38.448 5.461 39.048 5.507 ;
     RECT  48.864 5.125 48.888 5.555 ;
     RECT  18 4.885 22.056 5.557 ;
     RECT  44.16 5.171 47.4 5.603 ;
     RECT  18 5.557 22.152 5.699 ;
     RECT  14.544 5.219 15.144 5.747 ;
     RECT  16.416 3.971 17.016 5.747 ;
     RECT  18 5.699 22.056 5.747 ;
     RECT  23.424 5.171 24.504 5.747 ;
     RECT  25.632 5.171 25.656 5.747 ;
     RECT  26.64 2.195 26.664 5.747 ;
     RECT  30.864 4.261 30.888 5.747 ;
     RECT  50.304 4.261 51.312 5.747 ;
     RECT  34.8 5.219 35.304 5.749 ;
     RECT  16.848 5.747 17.016 5.795 ;
     RECT  16.992 5.795 17.016 5.843 ;
     RECT  18.336 5.747 18.912 5.891 ;
     RECT  23.424 5.747 24.408 5.939 ;
     RECT  44.16 5.603 44.52 5.987 ;
     RECT  34.8 5.749 35.736 6.131 ;
     RECT  13.056 5.219 13.512 6.323 ;
     RECT  23.424 5.939 24.312 6.323 ;
     RECT  32.592 2.915 33.72 6.323 ;
     RECT  38.448 5.507 38.616 6.323 ;
     RECT  45.6 5.603 47.4 6.323 ;
     RECT  19.968 5.747 21.384 6.803 ;
     RECT  50.736 5.747 51.312 7.333 ;
     RECT  34.8 6.131 35.112 7.381 ;
     RECT  47.376 6.323 47.4 7.475 ;
     RECT  13.2 6.323 13.512 7.957 ;
     RECT  44.496 5.987 44.52 8.003 ;
     RECT  48.528 7.669 48.552 8.003 ;
     RECT  32.592 6.323 33.288 8.579 ;
     RECT  41.664 2.771 42.264 8.579 ;
     RECT  41.664 8.579 42.12 8.867 ;
     RECT  45.6 6.323 46.392 8.917 ;
     RECT  45.6 8.917 46.728 9.059 ;
     RECT  42.096 8.867 42.12 9.155 ;
     RECT  20.544 6.803 21.384 12.035 ;
     RECT  7.8 2.151 8.112 12.229 ;
     RECT  38.448 6.323 38.472 12.371 ;
     RECT  29.4 2.137 29.712 12.469 ;
     RECT  7.8 12.229 8.28 13.139 ;
     RECT  11.664 4.787 11.688 15.203 ;
     RECT  6.48 13.813 6.504 15.443 ;
     RECT  4.752 13.045 4.776 17.077 ;
     RECT  4.752 17.077 5.112 18.275 ;
     RECT  53.808 5.173 53.832 19.333 ;
     RECT  50.736 7.333 51.816 19.429 ;
     RECT  53.808 19.333 54.696 19.909 ;
     RECT  53.664 19.909 54.696 19.955 ;
     RECT  5.088 18.275 5.112 20.003 ;
     RECT  54.672 19.955 54.696 20.051 ;
     RECT  6.336 19.237 6.36 20.341 ;
     RECT  6.24 20.341 6.36 20.387 ;
     RECT  50.736 19.429 52.344 20.579 ;
     RECT  54.768 20.581 54.792 21.635 ;
     RECT  6.24 20.387 6.264 21.827 ;
     RECT  53.664 19.955 53.688 23.411 ;
     RECT  34.656 7.381 35.112 23.557 ;
     RECT  34.224 23.557 35.112 23.843 ;
     RECT  13.2 7.957 13.608 23.893 ;
     RECT  50.736 20.579 51.816 26.101 ;
     RECT  56.4 2.151 56.712 27.109 ;
     RECT  56.4 27.109 57.048 27.251 ;
     RECT  50.736 26.101 52.248 27.347 ;
     RECT  54.672 28.693 54.696 30.805 ;
     RECT  54.672 30.805 54.84 31.091 ;
     RECT  56.4 27.251 56.712 31.285 ;
     RECT  54.672 31.091 54.696 32.437 ;
     RECT  54.384 32.437 54.696 32.483 ;
     RECT  56.304 31.285 56.712 32.771 ;
     RECT  20.544 12.035 20.568 36.323 ;
     RECT  54.384 32.483 54.408 41.941 ;
     RECT  53.472 41.941 54.408 42.757 ;
     RECT  53.136 42.757 54.408 42.851 ;
     RECT  53.136 42.851 53.16 43.043 ;
     RECT  29.4 12.469 30.264 43.045 ;
     RECT  50.736 27.347 51.816 43.861 ;
     RECT  54.384 42.851 54.408 43.861 ;
     RECT  53.472 43.861 54.408 44.915 ;
     RECT  11.952 42.757 11.976 45.493 ;
     RECT  11.28 45.493 11.976 45.731 ;
     RECT  11.28 45.731 11.304 46.693 ;
     RECT  29.4 43.045 30.504 46.835 ;
     RECT  50.736 43.861 52.344 47.411 ;
     RECT  11.232 46.693 11.304 47.461 ;
     RECT  10.848 47.461 11.304 48.371 ;
     RECT  50.736 47.411 51.816 48.421 ;
     RECT  26.208 47.845 26.232 48.707 ;
     RECT  50.736 48.421 52.248 48.707 ;
     RECT  54.288 44.915 54.312 48.805 ;
     RECT  53.376 48.805 54.504 48.851 ;
     RECT  54.48 48.851 54.504 49.717 ;
     RECT  53.376 48.851 53.4 50.051 ;
     RECT  54.48 49.717 54.984 50.533 ;
     RECT  54.48 50.533 55.272 50.819 ;
     RECT  56.4 32.771 56.712 51.541 ;
     RECT  55.632 51.541 56.712 51.827 ;
     RECT  13.2 23.893 14.568 52.261 ;
     RECT  23.904 6.323 24.312 53.075 ;
     RECT  18.6 5.891 18.912 53.173 ;
     RECT  13.2 52.261 14.616 53.219 ;
     RECT  50.736 48.707 51.816 53.557 ;
     RECT  54.48 50.819 54.504 53.749 ;
     RECT  54.384 53.749 54.504 54.085 ;
     RECT  50.736 53.557 52.344 54.131 ;
     RECT  50.736 54.131 51.72 54.179 ;
     RECT  54.384 54.085 54.84 54.373 ;
     RECT  7.8 13.139 8.112 54.661 ;
     RECT  53.52 54.373 54.84 54.707 ;
     RECT  17.712 53.173 18.912 54.755 ;
     RECT  54.384 54.707 54.84 54.755 ;
     RECT  9.408 50.437 9.432 54.853 ;
     RECT  24 53.075 24.312 55.237 ;
     RECT  45.6 9.059 45.912 55.477 ;
     RECT  9.408 54.853 10.056 55.667 ;
     RECT  13.2 53.219 14.568 55.813 ;
     RECT  28.368 47.029 28.392 55.813 ;
     RECT  29.4 46.835 29.712 55.813 ;
     RECT  34.8 23.843 35.112 55.813 ;
     RECT  13.104 55.813 14.568 55.907 ;
     RECT  24 55.237 24.504 55.907 ;
     RECT  7.2 54.661 8.112 55.955 ;
     RECT  10.032 55.667 10.056 55.955 ;
     RECT  28.368 55.813 29.712 56.963 ;
     RECT  7.8 55.955 8.112 58.117 ;
     RECT  11.28 48.371 11.304 58.117 ;
     RECT  13.104 55.907 13.656 58.117 ;
     RECT  15.696 30.325 15.72 58.117 ;
     RECT  17.808 54.755 18.912 58.117 ;
     RECT  24 55.907 24.312 58.117 ;
     RECT  28.464 56.963 29.712 58.117 ;
     RECT  34.512 55.813 35.4 58.117 ;
     RECT  40.2 2.963 40.512 58.117 ;
     RECT  44.784 55.477 45.912 58.117 ;
     RECT  51 54.179 51.72 58.117 ;
     RECT  54.384 54.755 54.408 58.117 ;
     RECT  6.048 58.117 30.696 58.165 ;
     RECT  34.128 58.117 54.744 58.165 ;
     RECT  34.128 58.165 54.888 58.261 ;
     RECT  2.4 2.151 2.712 58.329 ;
     RECT  56.4 51.827 56.712 58.329 ;
     RECT  2.4 58.329 2.52 58.343 ;
     RECT  56.4 58.329 56.52 58.343 ;
     RECT  34.128 58.261 55.032 58.501 ;
     RECT  32.112 58.117 33 58.597 ;
     RECT  33.984 58.501 55.032 58.597 ;
     RECT  6.048 58.165 30.84 60.432 ;
     RECT  32.112 58.597 55.032 60.432 ;
  END
END ot_static_cmd_target
END LIBRARY
